VERSION 5.8 ;
BUSBITCHARS "[]" ;
DIVIDERCHAR "/" ;
UNITS
    DATABASE MICRONS 1000 ;
END UNITS

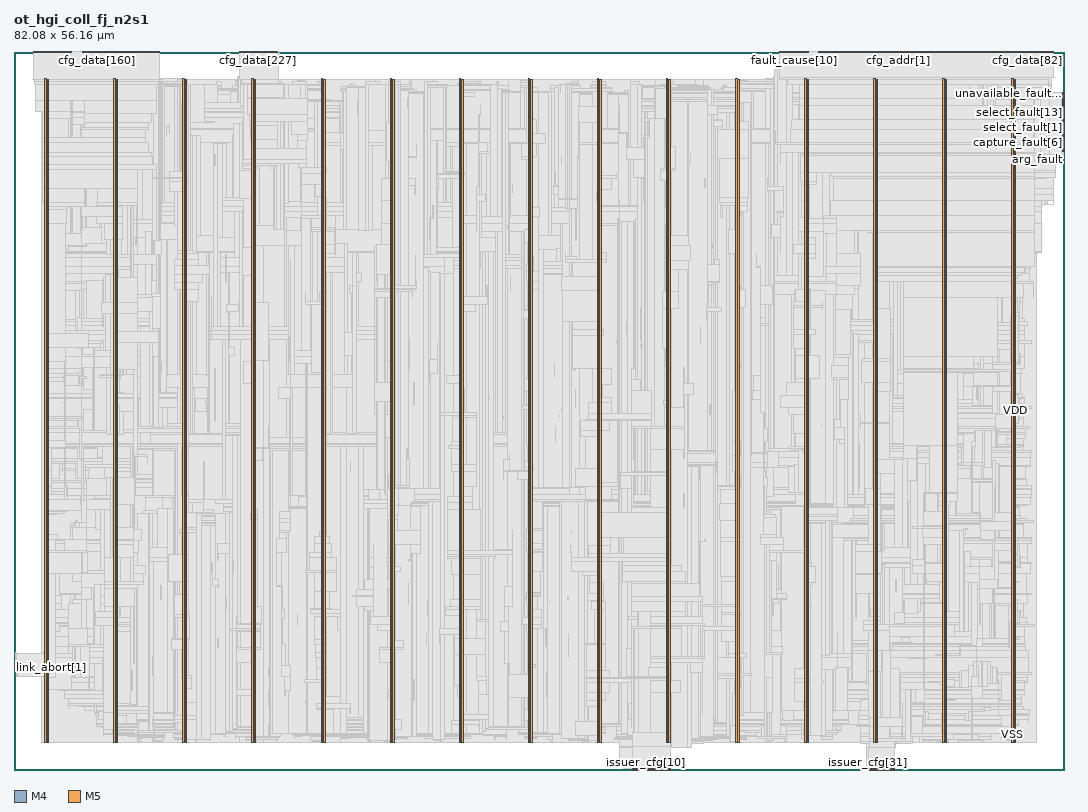
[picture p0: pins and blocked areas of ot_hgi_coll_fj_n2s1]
MACRO ot_hgi_coll_fj_n2s1
  FOREIGN ot_hgi_coll_fj_n2s1 0 0 ;
  CLASS BLOCK ;
  SIZE 82.08 BY 56.16 ;
  PIN arg_fault
    DIRECTION INPUT ;
    USE SIGNAL ;
    PORT
      LAYER M4 ;
        RECT  81.996 48.336 82.08 48.36 ;
    END
  END arg_fault
  PIN capture_fault[0]
    DIRECTION INPUT ;
    USE SIGNAL ;
    PORT
      LAYER M4 ;
        RECT  81.996 48.432 82.08 48.456 ;
    END
  END capture_fault[0]
  PIN capture_fault[1]
    DIRECTION INPUT ;
    USE SIGNAL ;
    PORT
      LAYER M4 ;
        RECT  81.996 48.528 82.08 48.552 ;
    END
  END capture_fault[1]
  PIN capture_fault[2]
    DIRECTION INPUT ;
    USE SIGNAL ;
    PORT
      LAYER M4 ;
        RECT  81.996 48.624 82.08 48.648 ;
    END
  END capture_fault[2]
  PIN capture_fault[3]
    DIRECTION INPUT ;
    USE SIGNAL ;
    PORT
      LAYER M4 ;
        RECT  81.996 48.72 82.08 48.744 ;
    END
  END capture_fault[3]
  PIN capture_fault[4]
    DIRECTION INPUT ;
    USE SIGNAL ;
    PORT
      LAYER M4 ;
        RECT  81.996 48.816 82.08 48.84 ;
    END
  END capture_fault[4]
  PIN capture_fault[5]
    DIRECTION INPUT ;
    USE SIGNAL ;
    PORT
      LAYER M4 ;
        RECT  81.996 48.912 82.08 48.936 ;
    END
  END capture_fault[5]
  PIN capture_fault[6]
    DIRECTION INPUT ;
    USE SIGNAL ;
    PORT
      LAYER M4 ;
        RECT  81.996 49.008 82.08 49.032 ;
    END
  END capture_fault[6]
  PIN capture_fault[7]
    DIRECTION INPUT ;
    USE SIGNAL ;
    PORT
      LAYER M4 ;
        RECT  81.996 49.104 82.08 49.128 ;
    END
  END capture_fault[7]
  PIN capture_fault[8]
    DIRECTION INPUT ;
    USE SIGNAL ;
    PORT
      LAYER M4 ;
        RECT  81.996 49.2 82.08 49.224 ;
    END
  END capture_fault[8]
  PIN capture_fault[9]
    DIRECTION INPUT ;
    USE SIGNAL ;
    PORT
      LAYER M4 ;
        RECT  81.996 49.296 82.08 49.32 ;
    END
  END capture_fault[9]
  PIN cfg_addr[0]
    DIRECTION INPUT ;
    USE SIGNAL ;
    PORT
      LAYER M5 ;
        RECT  69.072 56.076 69.096 56.16 ;
    END
  END cfg_addr[0]
  PIN cfg_addr[10]
    DIRECTION INPUT ;
    USE SIGNAL ;
    PORT
      LAYER M5 ;
        RECT  70.032 56.076 70.056 56.16 ;
    END
  END cfg_addr[10]
  PIN cfg_addr[11]
    DIRECTION INPUT ;
    USE SIGNAL ;
    PORT
      LAYER M5 ;
        RECT  70.128 56.076 70.152 56.16 ;
    END
  END cfg_addr[11]
  PIN cfg_addr[1]
    DIRECTION INPUT ;
    USE SIGNAL ;
    PORT
      LAYER M5 ;
        RECT  69.168 56.076 69.192 56.16 ;
    END
  END cfg_addr[1]
  PIN cfg_addr[2]
    DIRECTION INPUT ;
    USE SIGNAL ;
    PORT
      LAYER M5 ;
        RECT  69.264 56.076 69.288 56.16 ;
    END
  END cfg_addr[2]
  PIN cfg_addr[3]
    DIRECTION INPUT ;
    USE SIGNAL ;
    PORT
      LAYER M5 ;
        RECT  69.36 56.076 69.384 56.16 ;
    END
  END cfg_addr[3]
  PIN cfg_addr[4]
    DIRECTION INPUT ;
    USE SIGNAL ;
    PORT
      LAYER M5 ;
        RECT  69.456 56.076 69.48 56.16 ;
    END
  END cfg_addr[4]
  PIN cfg_addr[5]
    DIRECTION INPUT ;
    USE SIGNAL ;
    PORT
      LAYER M5 ;
        RECT  69.552 56.076 69.576 56.16 ;
    END
  END cfg_addr[5]
  PIN cfg_addr[6]
    DIRECTION INPUT ;
    USE SIGNAL ;
    PORT
      LAYER M5 ;
        RECT  69.648 56.076 69.672 56.16 ;
    END
  END cfg_addr[6]
  PIN cfg_addr[7]
    DIRECTION INPUT ;
    USE SIGNAL ;
    PORT
      LAYER M5 ;
        RECT  69.744 56.076 69.768 56.16 ;
    END
  END cfg_addr[7]
  PIN cfg_addr[8]
    DIRECTION INPUT ;
    USE SIGNAL ;
    PORT
      LAYER M5 ;
        RECT  69.84 56.076 69.864 56.16 ;
    END
  END cfg_addr[8]
  PIN cfg_addr[9]
    DIRECTION INPUT ;
    USE SIGNAL ;
    PORT
      LAYER M5 ;
        RECT  69.936 56.076 69.96 56.16 ;
    END
  END cfg_addr[9]
  PIN cfg_data[0]
    DIRECTION INPUT ;
    USE SIGNAL ;
    PORT
      LAYER M5 ;
        RECT  70.224 56.076 70.248 56.16 ;
    END
  END cfg_data[0]
  PIN cfg_data[100]
    DIRECTION INPUT ;
    USE SIGNAL ;
    PORT
      LAYER M5 ;
        RECT  64.464 56.076 64.488 56.16 ;
    END
  END cfg_data[100]
  PIN cfg_data[101]
    DIRECTION INPUT ;
    USE SIGNAL ;
    PORT
      LAYER M5 ;
        RECT  64.56 56.076 64.584 56.16 ;
    END
  END cfg_data[101]
  PIN cfg_data[102]
    DIRECTION INPUT ;
    USE SIGNAL ;
    PORT
      LAYER M5 ;
        RECT  64.656 56.076 64.68 56.16 ;
    END
  END cfg_data[102]
  PIN cfg_data[103]
    DIRECTION INPUT ;
    USE SIGNAL ;
    PORT
      LAYER M5 ;
        RECT  64.752 56.076 64.776 56.16 ;
    END
  END cfg_data[103]
  PIN cfg_data[104]
    DIRECTION INPUT ;
    USE SIGNAL ;
    PORT
      LAYER M5 ;
        RECT  64.848 56.076 64.872 56.16 ;
    END
  END cfg_data[104]
  PIN cfg_data[105]
    DIRECTION INPUT ;
    USE SIGNAL ;
    PORT
      LAYER M5 ;
        RECT  64.944 56.076 64.968 56.16 ;
    END
  END cfg_data[105]
  PIN cfg_data[106]
    DIRECTION INPUT ;
    USE SIGNAL ;
    PORT
      LAYER M5 ;
        RECT  65.04 56.076 65.064 56.16 ;
    END
  END cfg_data[106]
  PIN cfg_data[107]
    DIRECTION INPUT ;
    USE SIGNAL ;
    PORT
      LAYER M5 ;
        RECT  65.136 56.076 65.16 56.16 ;
    END
  END cfg_data[107]
  PIN cfg_data[108]
    DIRECTION INPUT ;
    USE SIGNAL ;
    PORT
      LAYER M5 ;
        RECT  65.232 56.076 65.256 56.16 ;
    END
  END cfg_data[108]
  PIN cfg_data[109]
    DIRECTION INPUT ;
    USE SIGNAL ;
    PORT
      LAYER M5 ;
        RECT  65.328 56.076 65.352 56.16 ;
    END
  END cfg_data[109]
  PIN cfg_data[10]
    DIRECTION INPUT ;
    USE SIGNAL ;
    PORT
      LAYER M5 ;
        RECT  71.184 56.076 71.208 56.16 ;
    END
  END cfg_data[10]
  PIN cfg_data[110]
    DIRECTION INPUT ;
    USE SIGNAL ;
    PORT
      LAYER M5 ;
        RECT  65.424 56.076 65.448 56.16 ;
    END
  END cfg_data[110]
  PIN cfg_data[111]
    DIRECTION INPUT ;
    USE SIGNAL ;
    PORT
      LAYER M5 ;
        RECT  65.52 56.076 65.544 56.16 ;
    END
  END cfg_data[111]
  PIN cfg_data[112]
    DIRECTION INPUT ;
    USE SIGNAL ;
    PORT
      LAYER M5 ;
        RECT  65.616 56.076 65.64 56.16 ;
    END
  END cfg_data[112]
  PIN cfg_data[113]
    DIRECTION INPUT ;
    USE SIGNAL ;
    PORT
      LAYER M5 ;
        RECT  65.712 56.076 65.736 56.16 ;
    END
  END cfg_data[113]
  PIN cfg_data[114]
    DIRECTION INPUT ;
    USE SIGNAL ;
    PORT
      LAYER M5 ;
        RECT  65.808 56.076 65.832 56.16 ;
    END
  END cfg_data[114]
  PIN cfg_data[115]
    DIRECTION INPUT ;
    USE SIGNAL ;
    PORT
      LAYER M5 ;
        RECT  65.904 56.076 65.928 56.16 ;
    END
  END cfg_data[115]
  PIN cfg_data[116]
    DIRECTION INPUT ;
    USE SIGNAL ;
    PORT
      LAYER M5 ;
        RECT  1.488 56.076 1.512 56.16 ;
    END
  END cfg_data[116]
  PIN cfg_data[117]
    DIRECTION INPUT ;
    USE SIGNAL ;
    PORT
      LAYER M5 ;
        RECT  1.584 56.076 1.608 56.16 ;
    END
  END cfg_data[117]
  PIN cfg_data[118]
    DIRECTION INPUT ;
    USE SIGNAL ;
    PORT
      LAYER M5 ;
        RECT  1.68 56.076 1.704 56.16 ;
    END
  END cfg_data[118]
  PIN cfg_data[119]
    DIRECTION INPUT ;
    USE SIGNAL ;
    PORT
      LAYER M5 ;
        RECT  1.776 56.076 1.8 56.16 ;
    END
  END cfg_data[119]
  PIN cfg_data[11]
    DIRECTION INPUT ;
    USE SIGNAL ;
    PORT
      LAYER M5 ;
        RECT  71.28 56.076 71.304 56.16 ;
    END
  END cfg_data[11]
  PIN cfg_data[120]
    DIRECTION INPUT ;
    USE SIGNAL ;
    PORT
      LAYER M5 ;
        RECT  1.872 56.076 1.896 56.16 ;
    END
  END cfg_data[120]
  PIN cfg_data[121]
    DIRECTION INPUT ;
    USE SIGNAL ;
    PORT
      LAYER M5 ;
        RECT  1.968 56.076 1.992 56.16 ;
    END
  END cfg_data[121]
  PIN cfg_data[122]
    DIRECTION INPUT ;
    USE SIGNAL ;
    PORT
      LAYER M5 ;
        RECT  2.064 56.076 2.088 56.16 ;
    END
  END cfg_data[122]
  PIN cfg_data[123]
    DIRECTION INPUT ;
    USE SIGNAL ;
    PORT
      LAYER M5 ;
        RECT  2.16 56.076 2.184 56.16 ;
    END
  END cfg_data[123]
  PIN cfg_data[124]
    DIRECTION INPUT ;
    USE SIGNAL ;
    PORT
      LAYER M5 ;
        RECT  2.256 56.076 2.28 56.16 ;
    END
  END cfg_data[124]
  PIN cfg_data[125]
    DIRECTION INPUT ;
    USE SIGNAL ;
    PORT
      LAYER M5 ;
        RECT  2.352 56.076 2.376 56.16 ;
    END
  END cfg_data[125]
  PIN cfg_data[126]
    DIRECTION INPUT ;
    USE SIGNAL ;
    PORT
      LAYER M5 ;
        RECT  2.448 56.076 2.472 56.16 ;
    END
  END cfg_data[126]
  PIN cfg_data[127]
    DIRECTION INPUT ;
    USE SIGNAL ;
    PORT
      LAYER M5 ;
        RECT  2.544 56.076 2.568 56.16 ;
    END
  END cfg_data[127]
  PIN cfg_data[128]
    DIRECTION INPUT ;
    USE SIGNAL ;
    PORT
      LAYER M5 ;
        RECT  2.64 56.076 2.664 56.16 ;
    END
  END cfg_data[128]
  PIN cfg_data[129]
    DIRECTION INPUT ;
    USE SIGNAL ;
    PORT
      LAYER M5 ;
        RECT  2.736 56.076 2.76 56.16 ;
    END
  END cfg_data[129]
  PIN cfg_data[12]
    DIRECTION INPUT ;
    USE SIGNAL ;
    PORT
      LAYER M5 ;
        RECT  71.376 56.076 71.4 56.16 ;
    END
  END cfg_data[12]
  PIN cfg_data[130]
    DIRECTION INPUT ;
    USE SIGNAL ;
    PORT
      LAYER M5 ;
        RECT  2.832 56.076 2.856 56.16 ;
    END
  END cfg_data[130]
  PIN cfg_data[131]
    DIRECTION INPUT ;
    USE SIGNAL ;
    PORT
      LAYER M5 ;
        RECT  2.928 56.076 2.952 56.16 ;
    END
  END cfg_data[131]
  PIN cfg_data[132]
    DIRECTION INPUT ;
    USE SIGNAL ;
    PORT
      LAYER M5 ;
        RECT  3.024 56.076 3.048 56.16 ;
    END
  END cfg_data[132]
  PIN cfg_data[133]
    DIRECTION INPUT ;
    USE SIGNAL ;
    PORT
      LAYER M5 ;
        RECT  3.12 56.076 3.144 56.16 ;
    END
  END cfg_data[133]
  PIN cfg_data[134]
    DIRECTION INPUT ;
    USE SIGNAL ;
    PORT
      LAYER M5 ;
        RECT  3.216 56.076 3.24 56.16 ;
    END
  END cfg_data[134]
  PIN cfg_data[135]
    DIRECTION INPUT ;
    USE SIGNAL ;
    PORT
      LAYER M5 ;
        RECT  3.312 56.076 3.336 56.16 ;
    END
  END cfg_data[135]
  PIN cfg_data[136]
    DIRECTION INPUT ;
    USE SIGNAL ;
    PORT
      LAYER M5 ;
        RECT  3.408 56.076 3.432 56.16 ;
    END
  END cfg_data[136]
  PIN cfg_data[137]
    DIRECTION INPUT ;
    USE SIGNAL ;
    PORT
      LAYER M5 ;
        RECT  3.504 56.076 3.528 56.16 ;
    END
  END cfg_data[137]
  PIN cfg_data[138]
    DIRECTION INPUT ;
    USE SIGNAL ;
    PORT
      LAYER M5 ;
        RECT  3.6 56.076 3.624 56.16 ;
    END
  END cfg_data[138]
  PIN cfg_data[139]
    DIRECTION INPUT ;
    USE SIGNAL ;
    PORT
      LAYER M5 ;
        RECT  3.696 56.076 3.72 56.16 ;
    END
  END cfg_data[139]
  PIN cfg_data[13]
    DIRECTION INPUT ;
    USE SIGNAL ;
    PORT
      LAYER M5 ;
        RECT  71.472 56.076 71.496 56.16 ;
    END
  END cfg_data[13]
  PIN cfg_data[140]
    DIRECTION INPUT ;
    USE SIGNAL ;
    PORT
      LAYER M5 ;
        RECT  3.792 56.076 3.816 56.16 ;
    END
  END cfg_data[140]
  PIN cfg_data[141]
    DIRECTION INPUT ;
    USE SIGNAL ;
    PORT
      LAYER M5 ;
        RECT  3.888 56.076 3.912 56.16 ;
    END
  END cfg_data[141]
  PIN cfg_data[142]
    DIRECTION INPUT ;
    USE SIGNAL ;
    PORT
      LAYER M5 ;
        RECT  3.984 56.076 4.008 56.16 ;
    END
  END cfg_data[142]
  PIN cfg_data[143]
    DIRECTION INPUT ;
    USE SIGNAL ;
    PORT
      LAYER M5 ;
        RECT  4.08 56.076 4.104 56.16 ;
    END
  END cfg_data[143]
  PIN cfg_data[144]
    DIRECTION INPUT ;
    USE SIGNAL ;
    PORT
      LAYER M5 ;
        RECT  4.176 56.076 4.2 56.16 ;
    END
  END cfg_data[144]
  PIN cfg_data[145]
    DIRECTION INPUT ;
    USE SIGNAL ;
    PORT
      LAYER M5 ;
        RECT  4.272 56.076 4.296 56.16 ;
    END
  END cfg_data[145]
  PIN cfg_data[146]
    DIRECTION INPUT ;
    USE SIGNAL ;
    PORT
      LAYER M5 ;
        RECT  4.368 56.076 4.392 56.16 ;
    END
  END cfg_data[146]
  PIN cfg_data[147]
    DIRECTION INPUT ;
    USE SIGNAL ;
    PORT
      LAYER M5 ;
        RECT  4.464 56.076 4.488 56.16 ;
    END
  END cfg_data[147]
  PIN cfg_data[148]
    DIRECTION INPUT ;
    USE SIGNAL ;
    PORT
      LAYER M5 ;
        RECT  5.328 56.076 5.352 56.16 ;
    END
  END cfg_data[148]
  PIN cfg_data[149]
    DIRECTION INPUT ;
    USE SIGNAL ;
    PORT
      LAYER M5 ;
        RECT  5.424 56.076 5.448 56.16 ;
    END
  END cfg_data[149]
  PIN cfg_data[14]
    DIRECTION INPUT ;
    USE SIGNAL ;
    PORT
      LAYER M5 ;
        RECT  71.568 56.076 71.592 56.16 ;
    END
  END cfg_data[14]
  PIN cfg_data[150]
    DIRECTION INPUT ;
    USE SIGNAL ;
    PORT
      LAYER M5 ;
        RECT  5.52 56.076 5.544 56.16 ;
    END
  END cfg_data[150]
  PIN cfg_data[151]
    DIRECTION INPUT ;
    USE SIGNAL ;
    PORT
      LAYER M5 ;
        RECT  5.616 56.076 5.64 56.16 ;
    END
  END cfg_data[151]
  PIN cfg_data[152]
    DIRECTION INPUT ;
    USE SIGNAL ;
    PORT
      LAYER M5 ;
        RECT  5.712 56.076 5.736 56.16 ;
    END
  END cfg_data[152]
  PIN cfg_data[153]
    DIRECTION INPUT ;
    USE SIGNAL ;
    PORT
      LAYER M5 ;
        RECT  5.808 56.076 5.832 56.16 ;
    END
  END cfg_data[153]
  PIN cfg_data[154]
    DIRECTION INPUT ;
    USE SIGNAL ;
    PORT
      LAYER M5 ;
        RECT  5.904 56.076 5.928 56.16 ;
    END
  END cfg_data[154]
  PIN cfg_data[155]
    DIRECTION INPUT ;
    USE SIGNAL ;
    PORT
      LAYER M5 ;
        RECT  6 56.076 6.024 56.16 ;
    END
  END cfg_data[155]
  PIN cfg_data[156]
    DIRECTION INPUT ;
    USE SIGNAL ;
    PORT
      LAYER M5 ;
        RECT  6.096 56.076 6.12 56.16 ;
    END
  END cfg_data[156]
  PIN cfg_data[157]
    DIRECTION INPUT ;
    USE SIGNAL ;
    PORT
      LAYER M5 ;
        RECT  6.192 56.076 6.216 56.16 ;
    END
  END cfg_data[157]
  PIN cfg_data[158]
    DIRECTION INPUT ;
    USE SIGNAL ;
    PORT
      LAYER M5 ;
        RECT  6.288 56.076 6.312 56.16 ;
    END
  END cfg_data[158]
  PIN cfg_data[159]
    DIRECTION INPUT ;
    USE SIGNAL ;
    PORT
      LAYER M5 ;
        RECT  6.384 56.076 6.408 56.16 ;
    END
  END cfg_data[159]
  PIN cfg_data[15]
    DIRECTION INPUT ;
    USE SIGNAL ;
    PORT
      LAYER M5 ;
        RECT  71.664 56.076 71.688 56.16 ;
    END
  END cfg_data[15]
  PIN cfg_data[160]
    DIRECTION INPUT ;
    USE SIGNAL ;
    PORT
      LAYER M5 ;
        RECT  6.48 56.076 6.504 56.16 ;
    END
  END cfg_data[160]
  PIN cfg_data[161]
    DIRECTION INPUT ;
    USE SIGNAL ;
    PORT
      LAYER M5 ;
        RECT  6.576 56.076 6.6 56.16 ;
    END
  END cfg_data[161]
  PIN cfg_data[162]
    DIRECTION INPUT ;
    USE SIGNAL ;
    PORT
      LAYER M5 ;
        RECT  6.672 56.076 6.696 56.16 ;
    END
  END cfg_data[162]
  PIN cfg_data[163]
    DIRECTION INPUT ;
    USE SIGNAL ;
    PORT
      LAYER M5 ;
        RECT  6.768 56.076 6.792 56.16 ;
    END
  END cfg_data[163]
  PIN cfg_data[164]
    DIRECTION INPUT ;
    USE SIGNAL ;
    PORT
      LAYER M5 ;
        RECT  6.864 56.076 6.888 56.16 ;
    END
  END cfg_data[164]
  PIN cfg_data[165]
    DIRECTION INPUT ;
    USE SIGNAL ;
    PORT
      LAYER M5 ;
        RECT  6.96 56.076 6.984 56.16 ;
    END
  END cfg_data[165]
  PIN cfg_data[166]
    DIRECTION INPUT ;
    USE SIGNAL ;
    PORT
      LAYER M5 ;
        RECT  7.056 56.076 7.08 56.16 ;
    END
  END cfg_data[166]
  PIN cfg_data[167]
    DIRECTION INPUT ;
    USE SIGNAL ;
    PORT
      LAYER M5 ;
        RECT  7.152 56.076 7.176 56.16 ;
    END
  END cfg_data[167]
  PIN cfg_data[168]
    DIRECTION INPUT ;
    USE SIGNAL ;
    PORT
      LAYER M5 ;
        RECT  7.248 56.076 7.272 56.16 ;
    END
  END cfg_data[168]
  PIN cfg_data[169]
    DIRECTION INPUT ;
    USE SIGNAL ;
    PORT
      LAYER M5 ;
        RECT  7.344 56.076 7.368 56.16 ;
    END
  END cfg_data[169]
  PIN cfg_data[16]
    DIRECTION INPUT ;
    USE SIGNAL ;
    PORT
      LAYER M5 ;
        RECT  71.76 56.076 71.784 56.16 ;
    END
  END cfg_data[16]
  PIN cfg_data[170]
    DIRECTION INPUT ;
    USE SIGNAL ;
    PORT
      LAYER M5 ;
        RECT  7.44 56.076 7.464 56.16 ;
    END
  END cfg_data[170]
  PIN cfg_data[171]
    DIRECTION INPUT ;
    USE SIGNAL ;
    PORT
      LAYER M5 ;
        RECT  7.536 56.076 7.56 56.16 ;
    END
  END cfg_data[171]
  PIN cfg_data[172]
    DIRECTION INPUT ;
    USE SIGNAL ;
    PORT
      LAYER M5 ;
        RECT  7.632 56.076 7.656 56.16 ;
    END
  END cfg_data[172]
  PIN cfg_data[173]
    DIRECTION INPUT ;
    USE SIGNAL ;
    PORT
      LAYER M5 ;
        RECT  7.728 56.076 7.752 56.16 ;
    END
  END cfg_data[173]
  PIN cfg_data[174]
    DIRECTION INPUT ;
    USE SIGNAL ;
    PORT
      LAYER M5 ;
        RECT  7.824 56.076 7.848 56.16 ;
    END
  END cfg_data[174]
  PIN cfg_data[175]
    DIRECTION INPUT ;
    USE SIGNAL ;
    PORT
      LAYER M5 ;
        RECT  7.92 56.076 7.944 56.16 ;
    END
  END cfg_data[175]
  PIN cfg_data[176]
    DIRECTION INPUT ;
    USE SIGNAL ;
    PORT
      LAYER M5 ;
        RECT  8.016 56.076 8.04 56.16 ;
    END
  END cfg_data[176]
  PIN cfg_data[177]
    DIRECTION INPUT ;
    USE SIGNAL ;
    PORT
      LAYER M5 ;
        RECT  8.112 56.076 8.136 56.16 ;
    END
  END cfg_data[177]
  PIN cfg_data[178]
    DIRECTION INPUT ;
    USE SIGNAL ;
    PORT
      LAYER M5 ;
        RECT  8.208 56.076 8.232 56.16 ;
    END
  END cfg_data[178]
  PIN cfg_data[179]
    DIRECTION INPUT ;
    USE SIGNAL ;
    PORT
      LAYER M5 ;
        RECT  8.304 56.076 8.328 56.16 ;
    END
  END cfg_data[179]
  PIN cfg_data[17]
    DIRECTION INPUT ;
    USE SIGNAL ;
    PORT
      LAYER M5 ;
        RECT  71.856 56.076 71.88 56.16 ;
    END
  END cfg_data[17]
  PIN cfg_data[180]
    DIRECTION INPUT ;
    USE SIGNAL ;
    PORT
      LAYER M5 ;
        RECT  8.4 56.076 8.424 56.16 ;
    END
  END cfg_data[180]
  PIN cfg_data[181]
    DIRECTION INPUT ;
    USE SIGNAL ;
    PORT
      LAYER M5 ;
        RECT  8.496 56.076 8.52 56.16 ;
    END
  END cfg_data[181]
  PIN cfg_data[182]
    DIRECTION INPUT ;
    USE SIGNAL ;
    PORT
      LAYER M5 ;
        RECT  8.592 56.076 8.616 56.16 ;
    END
  END cfg_data[182]
  PIN cfg_data[183]
    DIRECTION INPUT ;
    USE SIGNAL ;
    PORT
      LAYER M5 ;
        RECT  8.688 56.076 8.712 56.16 ;
    END
  END cfg_data[183]
  PIN cfg_data[184]
    DIRECTION INPUT ;
    USE SIGNAL ;
    PORT
      LAYER M5 ;
        RECT  8.784 56.076 8.808 56.16 ;
    END
  END cfg_data[184]
  PIN cfg_data[185]
    DIRECTION INPUT ;
    USE SIGNAL ;
    PORT
      LAYER M5 ;
        RECT  8.88 56.076 8.904 56.16 ;
    END
  END cfg_data[185]
  PIN cfg_data[186]
    DIRECTION INPUT ;
    USE SIGNAL ;
    PORT
      LAYER M5 ;
        RECT  8.976 56.076 9 56.16 ;
    END
  END cfg_data[186]
  PIN cfg_data[187]
    DIRECTION INPUT ;
    USE SIGNAL ;
    PORT
      LAYER M5 ;
        RECT  9.072 56.076 9.096 56.16 ;
    END
  END cfg_data[187]
  PIN cfg_data[188]
    DIRECTION INPUT ;
    USE SIGNAL ;
    PORT
      LAYER M5 ;
        RECT  9.168 56.076 9.192 56.16 ;
    END
  END cfg_data[188]
  PIN cfg_data[189]
    DIRECTION INPUT ;
    USE SIGNAL ;
    PORT
      LAYER M5 ;
        RECT  9.264 56.076 9.288 56.16 ;
    END
  END cfg_data[189]
  PIN cfg_data[18]
    DIRECTION INPUT ;
    USE SIGNAL ;
    PORT
      LAYER M5 ;
        RECT  71.952 56.076 71.976 56.16 ;
    END
  END cfg_data[18]
  PIN cfg_data[190]
    DIRECTION INPUT ;
    USE SIGNAL ;
    PORT
      LAYER M5 ;
        RECT  9.36 56.076 9.384 56.16 ;
    END
  END cfg_data[190]
  PIN cfg_data[191]
    DIRECTION INPUT ;
    USE SIGNAL ;
    PORT
      LAYER M5 ;
        RECT  9.456 56.076 9.48 56.16 ;
    END
  END cfg_data[191]
  PIN cfg_data[192]
    DIRECTION INPUT ;
    USE SIGNAL ;
    PORT
      LAYER M5 ;
        RECT  9.552 56.076 9.576 56.16 ;
    END
  END cfg_data[192]
  PIN cfg_data[193]
    DIRECTION INPUT ;
    USE SIGNAL ;
    PORT
      LAYER M5 ;
        RECT  9.648 56.076 9.672 56.16 ;
    END
  END cfg_data[193]
  PIN cfg_data[194]
    DIRECTION INPUT ;
    USE SIGNAL ;
    PORT
      LAYER M5 ;
        RECT  9.744 56.076 9.768 56.16 ;
    END
  END cfg_data[194]
  PIN cfg_data[195]
    DIRECTION INPUT ;
    USE SIGNAL ;
    PORT
      LAYER M5 ;
        RECT  9.84 56.076 9.864 56.16 ;
    END
  END cfg_data[195]
  PIN cfg_data[196]
    DIRECTION INPUT ;
    USE SIGNAL ;
    PORT
      LAYER M5 ;
        RECT  9.936 56.076 9.96 56.16 ;
    END
  END cfg_data[196]
  PIN cfg_data[197]
    DIRECTION INPUT ;
    USE SIGNAL ;
    PORT
      LAYER M5 ;
        RECT  10.032 56.076 10.056 56.16 ;
    END
  END cfg_data[197]
  PIN cfg_data[198]
    DIRECTION INPUT ;
    USE SIGNAL ;
    PORT
      LAYER M5 ;
        RECT  10.128 56.076 10.152 56.16 ;
    END
  END cfg_data[198]
  PIN cfg_data[199]
    DIRECTION INPUT ;
    USE SIGNAL ;
    PORT
      LAYER M5 ;
        RECT  10.224 56.076 10.248 56.16 ;
    END
  END cfg_data[199]
  PIN cfg_data[19]
    DIRECTION INPUT ;
    USE SIGNAL ;
    PORT
      LAYER M5 ;
        RECT  72.048 56.076 72.072 56.16 ;
    END
  END cfg_data[19]
  PIN cfg_data[1]
    DIRECTION INPUT ;
    USE SIGNAL ;
    PORT
      LAYER M5 ;
        RECT  70.32 56.076 70.344 56.16 ;
    END
  END cfg_data[1]
  PIN cfg_data[200]
    DIRECTION INPUT ;
    USE SIGNAL ;
    PORT
      LAYER M5 ;
        RECT  10.32 56.076 10.344 56.16 ;
    END
  END cfg_data[200]
  PIN cfg_data[201]
    DIRECTION INPUT ;
    USE SIGNAL ;
    PORT
      LAYER M5 ;
        RECT  10.416 56.076 10.44 56.16 ;
    END
  END cfg_data[201]
  PIN cfg_data[202]
    DIRECTION INPUT ;
    USE SIGNAL ;
    PORT
      LAYER M5 ;
        RECT  10.512 56.076 10.536 56.16 ;
    END
  END cfg_data[202]
  PIN cfg_data[203]
    DIRECTION INPUT ;
    USE SIGNAL ;
    PORT
      LAYER M5 ;
        RECT  10.608 56.076 10.632 56.16 ;
    END
  END cfg_data[203]
  PIN cfg_data[204]
    DIRECTION INPUT ;
    USE SIGNAL ;
    PORT
      LAYER M5 ;
        RECT  10.704 56.076 10.728 56.16 ;
    END
  END cfg_data[204]
  PIN cfg_data[205]
    DIRECTION INPUT ;
    USE SIGNAL ;
    PORT
      LAYER M5 ;
        RECT  10.8 56.076 10.824 56.16 ;
    END
  END cfg_data[205]
  PIN cfg_data[206]
    DIRECTION INPUT ;
    USE SIGNAL ;
    PORT
      LAYER M5 ;
        RECT  10.896 56.076 10.92 56.16 ;
    END
  END cfg_data[206]
  PIN cfg_data[207]
    DIRECTION INPUT ;
    USE SIGNAL ;
    PORT
      LAYER M5 ;
        RECT  10.992 56.076 11.016 56.16 ;
    END
  END cfg_data[207]
  PIN cfg_data[208]
    DIRECTION INPUT ;
    USE SIGNAL ;
    PORT
      LAYER M5 ;
        RECT  11.088 56.076 11.112 56.16 ;
    END
  END cfg_data[208]
  PIN cfg_data[209]
    DIRECTION INPUT ;
    USE SIGNAL ;
    PORT
      LAYER M5 ;
        RECT  11.184 56.076 11.208 56.16 ;
    END
  END cfg_data[209]
  PIN cfg_data[20]
    DIRECTION INPUT ;
    USE SIGNAL ;
    PORT
      LAYER M5 ;
        RECT  72.144 56.076 72.168 56.16 ;
    END
  END cfg_data[20]
  PIN cfg_data[210]
    DIRECTION INPUT ;
    USE SIGNAL ;
    PORT
      LAYER M5 ;
        RECT  11.28 56.076 11.304 56.16 ;
    END
  END cfg_data[210]
  PIN cfg_data[211]
    DIRECTION INPUT ;
    USE SIGNAL ;
    PORT
      LAYER M5 ;
        RECT  11.376 56.076 11.4 56.16 ;
    END
  END cfg_data[211]
  PIN cfg_data[212]
    DIRECTION INPUT ;
    USE SIGNAL ;
    PORT
      LAYER M5 ;
        RECT  17.616 56.076 17.64 56.16 ;
    END
  END cfg_data[212]
  PIN cfg_data[213]
    DIRECTION INPUT ;
    USE SIGNAL ;
    PORT
      LAYER M5 ;
        RECT  17.712 56.076 17.736 56.16 ;
    END
  END cfg_data[213]
  PIN cfg_data[214]
    DIRECTION INPUT ;
    USE SIGNAL ;
    PORT
      LAYER M5 ;
        RECT  17.808 56.076 17.832 56.16 ;
    END
  END cfg_data[214]
  PIN cfg_data[215]
    DIRECTION INPUT ;
    USE SIGNAL ;
    PORT
      LAYER M5 ;
        RECT  17.904 56.076 17.928 56.16 ;
    END
  END cfg_data[215]
  PIN cfg_data[216]
    DIRECTION INPUT ;
    USE SIGNAL ;
    PORT
      LAYER M5 ;
        RECT  18 56.076 18.024 56.16 ;
    END
  END cfg_data[216]
  PIN cfg_data[217]
    DIRECTION INPUT ;
    USE SIGNAL ;
    PORT
      LAYER M5 ;
        RECT  18.096 56.076 18.12 56.16 ;
    END
  END cfg_data[217]
  PIN cfg_data[218]
    DIRECTION INPUT ;
    USE SIGNAL ;
    PORT
      LAYER M5 ;
        RECT  18.192 56.076 18.216 56.16 ;
    END
  END cfg_data[218]
  PIN cfg_data[219]
    DIRECTION INPUT ;
    USE SIGNAL ;
    PORT
      LAYER M5 ;
        RECT  18.288 56.076 18.312 56.16 ;
    END
  END cfg_data[219]
  PIN cfg_data[21]
    DIRECTION INPUT ;
    USE SIGNAL ;
    PORT
      LAYER M5 ;
        RECT  72.24 56.076 72.264 56.16 ;
    END
  END cfg_data[21]
  PIN cfg_data[220]
    DIRECTION INPUT ;
    USE SIGNAL ;
    PORT
      LAYER M5 ;
        RECT  18.384 56.076 18.408 56.16 ;
    END
  END cfg_data[220]
  PIN cfg_data[221]
    DIRECTION INPUT ;
    USE SIGNAL ;
    PORT
      LAYER M5 ;
        RECT  18.48 56.076 18.504 56.16 ;
    END
  END cfg_data[221]
  PIN cfg_data[222]
    DIRECTION INPUT ;
    USE SIGNAL ;
    PORT
      LAYER M5 ;
        RECT  18.576 56.076 18.6 56.16 ;
    END
  END cfg_data[222]
  PIN cfg_data[223]
    DIRECTION INPUT ;
    USE SIGNAL ;
    PORT
      LAYER M5 ;
        RECT  18.672 56.076 18.696 56.16 ;
    END
  END cfg_data[223]
  PIN cfg_data[224]
    DIRECTION INPUT ;
    USE SIGNAL ;
    PORT
      LAYER M5 ;
        RECT  18.768 56.076 18.792 56.16 ;
    END
  END cfg_data[224]
  PIN cfg_data[225]
    DIRECTION INPUT ;
    USE SIGNAL ;
    PORT
      LAYER M5 ;
        RECT  18.864 56.076 18.888 56.16 ;
    END
  END cfg_data[225]
  PIN cfg_data[226]
    DIRECTION INPUT ;
    USE SIGNAL ;
    PORT
      LAYER M5 ;
        RECT  18.96 56.076 18.984 56.16 ;
    END
  END cfg_data[226]
  PIN cfg_data[227]
    DIRECTION INPUT ;
    USE SIGNAL ;
    PORT
      LAYER M5 ;
        RECT  19.056 56.076 19.08 56.16 ;
    END
  END cfg_data[227]
  PIN cfg_data[228]
    DIRECTION INPUT ;
    USE SIGNAL ;
    PORT
      LAYER M5 ;
        RECT  19.152 56.076 19.176 56.16 ;
    END
  END cfg_data[228]
  PIN cfg_data[229]
    DIRECTION INPUT ;
    USE SIGNAL ;
    PORT
      LAYER M5 ;
        RECT  19.248 56.076 19.272 56.16 ;
    END
  END cfg_data[229]
  PIN cfg_data[22]
    DIRECTION INPUT ;
    USE SIGNAL ;
    PORT
      LAYER M5 ;
        RECT  72.336 56.076 72.36 56.16 ;
    END
  END cfg_data[22]
  PIN cfg_data[230]
    DIRECTION INPUT ;
    USE SIGNAL ;
    PORT
      LAYER M5 ;
        RECT  19.344 56.076 19.368 56.16 ;
    END
  END cfg_data[230]
  PIN cfg_data[231]
    DIRECTION INPUT ;
    USE SIGNAL ;
    PORT
      LAYER M5 ;
        RECT  19.44 56.076 19.464 56.16 ;
    END
  END cfg_data[231]
  PIN cfg_data[232]
    DIRECTION INPUT ;
    USE SIGNAL ;
    PORT
      LAYER M5 ;
        RECT  19.536 56.076 19.56 56.16 ;
    END
  END cfg_data[232]
  PIN cfg_data[233]
    DIRECTION INPUT ;
    USE SIGNAL ;
    PORT
      LAYER M5 ;
        RECT  19.632 56.076 19.656 56.16 ;
    END
  END cfg_data[233]
  PIN cfg_data[234]
    DIRECTION INPUT ;
    USE SIGNAL ;
    PORT
      LAYER M5 ;
        RECT  19.728 56.076 19.752 56.16 ;
    END
  END cfg_data[234]
  PIN cfg_data[235]
    DIRECTION INPUT ;
    USE SIGNAL ;
    PORT
      LAYER M5 ;
        RECT  19.824 56.076 19.848 56.16 ;
    END
  END cfg_data[235]
  PIN cfg_data[236]
    DIRECTION INPUT ;
    USE SIGNAL ;
    PORT
      LAYER M5 ;
        RECT  19.92 56.076 19.944 56.16 ;
    END
  END cfg_data[236]
  PIN cfg_data[237]
    DIRECTION INPUT ;
    USE SIGNAL ;
    PORT
      LAYER M5 ;
        RECT  20.016 56.076 20.04 56.16 ;
    END
  END cfg_data[237]
  PIN cfg_data[238]
    DIRECTION INPUT ;
    USE SIGNAL ;
    PORT
      LAYER M5 ;
        RECT  20.112 56.076 20.136 56.16 ;
    END
  END cfg_data[238]
  PIN cfg_data[239]
    DIRECTION INPUT ;
    USE SIGNAL ;
    PORT
      LAYER M5 ;
        RECT  20.208 56.076 20.232 56.16 ;
    END
  END cfg_data[239]
  PIN cfg_data[23]
    DIRECTION INPUT ;
    USE SIGNAL ;
    PORT
      LAYER M5 ;
        RECT  72.432 56.076 72.456 56.16 ;
    END
  END cfg_data[23]
  PIN cfg_data[240]
    DIRECTION INPUT ;
    USE SIGNAL ;
    PORT
      LAYER M5 ;
        RECT  20.304 56.076 20.328 56.16 ;
    END
  END cfg_data[240]
  PIN cfg_data[241]
    DIRECTION INPUT ;
    USE SIGNAL ;
    PORT
      LAYER M5 ;
        RECT  20.4 56.076 20.424 56.16 ;
    END
  END cfg_data[241]
  PIN cfg_data[242]
    DIRECTION INPUT ;
    USE SIGNAL ;
    PORT
      LAYER M5 ;
        RECT  20.496 56.076 20.52 56.16 ;
    END
  END cfg_data[242]
  PIN cfg_data[243]
    DIRECTION INPUT ;
    USE SIGNAL ;
    PORT
      LAYER M5 ;
        RECT  20.592 56.076 20.616 56.16 ;
    END
  END cfg_data[243]
  PIN cfg_data[244]
    DIRECTION INPUT ;
    USE SIGNAL ;
    PORT
      LAYER M5 ;
        RECT  66 56.076 66.024 56.16 ;
    END
  END cfg_data[244]
  PIN cfg_data[245]
    DIRECTION INPUT ;
    USE SIGNAL ;
    PORT
      LAYER M5 ;
        RECT  66.096 56.076 66.12 56.16 ;
    END
  END cfg_data[245]
  PIN cfg_data[246]
    DIRECTION INPUT ;
    USE SIGNAL ;
    PORT
      LAYER M5 ;
        RECT  66.192 56.076 66.216 56.16 ;
    END
  END cfg_data[246]
  PIN cfg_data[247]
    DIRECTION INPUT ;
    USE SIGNAL ;
    PORT
      LAYER M5 ;
        RECT  66.288 56.076 66.312 56.16 ;
    END
  END cfg_data[247]
  PIN cfg_data[248]
    DIRECTION INPUT ;
    USE SIGNAL ;
    PORT
      LAYER M5 ;
        RECT  66.384 56.076 66.408 56.16 ;
    END
  END cfg_data[248]
  PIN cfg_data[249]
    DIRECTION INPUT ;
    USE SIGNAL ;
    PORT
      LAYER M5 ;
        RECT  66.48 56.076 66.504 56.16 ;
    END
  END cfg_data[249]
  PIN cfg_data[24]
    DIRECTION INPUT ;
    USE SIGNAL ;
    PORT
      LAYER M5 ;
        RECT  72.528 56.076 72.552 56.16 ;
    END
  END cfg_data[24]
  PIN cfg_data[250]
    DIRECTION INPUT ;
    USE SIGNAL ;
    PORT
      LAYER M5 ;
        RECT  66.576 56.076 66.6 56.16 ;
    END
  END cfg_data[250]
  PIN cfg_data[251]
    DIRECTION INPUT ;
    USE SIGNAL ;
    PORT
      LAYER M5 ;
        RECT  66.672 56.076 66.696 56.16 ;
    END
  END cfg_data[251]
  PIN cfg_data[252]
    DIRECTION INPUT ;
    USE SIGNAL ;
    PORT
      LAYER M5 ;
        RECT  66.768 56.076 66.792 56.16 ;
    END
  END cfg_data[252]
  PIN cfg_data[253]
    DIRECTION INPUT ;
    USE SIGNAL ;
    PORT
      LAYER M5 ;
        RECT  66.864 56.076 66.888 56.16 ;
    END
  END cfg_data[253]
  PIN cfg_data[254]
    DIRECTION INPUT ;
    USE SIGNAL ;
    PORT
      LAYER M5 ;
        RECT  66.96 56.076 66.984 56.16 ;
    END
  END cfg_data[254]
  PIN cfg_data[255]
    DIRECTION INPUT ;
    USE SIGNAL ;
    PORT
      LAYER M5 ;
        RECT  67.056 56.076 67.08 56.16 ;
    END
  END cfg_data[255]
  PIN cfg_data[25]
    DIRECTION INPUT ;
    USE SIGNAL ;
    PORT
      LAYER M5 ;
        RECT  72.624 56.076 72.648 56.16 ;
    END
  END cfg_data[25]
  PIN cfg_data[26]
    DIRECTION INPUT ;
    USE SIGNAL ;
    PORT
      LAYER M5 ;
        RECT  72.72 56.076 72.744 56.16 ;
    END
  END cfg_data[26]
  PIN cfg_data[27]
    DIRECTION INPUT ;
    USE SIGNAL ;
    PORT
      LAYER M5 ;
        RECT  72.816 56.076 72.84 56.16 ;
    END
  END cfg_data[27]
  PIN cfg_data[28]
    DIRECTION INPUT ;
    USE SIGNAL ;
    PORT
      LAYER M5 ;
        RECT  72.912 56.076 72.936 56.16 ;
    END
  END cfg_data[28]
  PIN cfg_data[29]
    DIRECTION INPUT ;
    USE SIGNAL ;
    PORT
      LAYER M5 ;
        RECT  73.008 56.076 73.032 56.16 ;
    END
  END cfg_data[29]
  PIN cfg_data[2]
    DIRECTION INPUT ;
    USE SIGNAL ;
    PORT
      LAYER M5 ;
        RECT  70.416 56.076 70.44 56.16 ;
    END
  END cfg_data[2]
  PIN cfg_data[30]
    DIRECTION INPUT ;
    USE SIGNAL ;
    PORT
      LAYER M5 ;
        RECT  73.104 56.076 73.128 56.16 ;
    END
  END cfg_data[30]
  PIN cfg_data[31]
    DIRECTION INPUT ;
    USE SIGNAL ;
    PORT
      LAYER M5 ;
        RECT  73.2 56.076 73.224 56.16 ;
    END
  END cfg_data[31]
  PIN cfg_data[32]
    DIRECTION INPUT ;
    USE SIGNAL ;
    PORT
      LAYER M5 ;
        RECT  73.296 56.076 73.32 56.16 ;
    END
  END cfg_data[32]
  PIN cfg_data[33]
    DIRECTION INPUT ;
    USE SIGNAL ;
    PORT
      LAYER M5 ;
        RECT  73.392 56.076 73.416 56.16 ;
    END
  END cfg_data[33]
  PIN cfg_data[34]
    DIRECTION INPUT ;
    USE SIGNAL ;
    PORT
      LAYER M5 ;
        RECT  73.488 56.076 73.512 56.16 ;
    END
  END cfg_data[34]
  PIN cfg_data[35]
    DIRECTION INPUT ;
    USE SIGNAL ;
    PORT
      LAYER M5 ;
        RECT  73.584 56.076 73.608 56.16 ;
    END
  END cfg_data[35]
  PIN cfg_data[36]
    DIRECTION INPUT ;
    USE SIGNAL ;
    PORT
      LAYER M5 ;
        RECT  73.68 56.076 73.704 56.16 ;
    END
  END cfg_data[36]
  PIN cfg_data[37]
    DIRECTION INPUT ;
    USE SIGNAL ;
    PORT
      LAYER M5 ;
        RECT  73.776 56.076 73.8 56.16 ;
    END
  END cfg_data[37]
  PIN cfg_data[38]
    DIRECTION INPUT ;
    USE SIGNAL ;
    PORT
      LAYER M5 ;
        RECT  73.872 56.076 73.896 56.16 ;
    END
  END cfg_data[38]
  PIN cfg_data[39]
    DIRECTION INPUT ;
    USE SIGNAL ;
    PORT
      LAYER M5 ;
        RECT  73.968 56.076 73.992 56.16 ;
    END
  END cfg_data[39]
  PIN cfg_data[3]
    DIRECTION INPUT ;
    USE SIGNAL ;
    PORT
      LAYER M5 ;
        RECT  70.512 56.076 70.536 56.16 ;
    END
  END cfg_data[3]
  PIN cfg_data[40]
    DIRECTION INPUT ;
    USE SIGNAL ;
    PORT
      LAYER M5 ;
        RECT  74.064 56.076 74.088 56.16 ;
    END
  END cfg_data[40]
  PIN cfg_data[41]
    DIRECTION INPUT ;
    USE SIGNAL ;
    PORT
      LAYER M5 ;
        RECT  74.16 56.076 74.184 56.16 ;
    END
  END cfg_data[41]
  PIN cfg_data[42]
    DIRECTION INPUT ;
    USE SIGNAL ;
    PORT
      LAYER M5 ;
        RECT  74.256 56.076 74.28 56.16 ;
    END
  END cfg_data[42]
  PIN cfg_data[43]
    DIRECTION INPUT ;
    USE SIGNAL ;
    PORT
      LAYER M5 ;
        RECT  74.352 56.076 74.376 56.16 ;
    END
  END cfg_data[43]
  PIN cfg_data[44]
    DIRECTION INPUT ;
    USE SIGNAL ;
    PORT
      LAYER M5 ;
        RECT  74.448 56.076 74.472 56.16 ;
    END
  END cfg_data[44]
  PIN cfg_data[45]
    DIRECTION INPUT ;
    USE SIGNAL ;
    PORT
      LAYER M5 ;
        RECT  74.544 56.076 74.568 56.16 ;
    END
  END cfg_data[45]
  PIN cfg_data[46]
    DIRECTION INPUT ;
    USE SIGNAL ;
    PORT
      LAYER M5 ;
        RECT  74.64 56.076 74.664 56.16 ;
    END
  END cfg_data[46]
  PIN cfg_data[47]
    DIRECTION INPUT ;
    USE SIGNAL ;
    PORT
      LAYER M5 ;
        RECT  74.736 56.076 74.76 56.16 ;
    END
  END cfg_data[47]
  PIN cfg_data[48]
    DIRECTION INPUT ;
    USE SIGNAL ;
    PORT
      LAYER M5 ;
        RECT  74.832 56.076 74.856 56.16 ;
    END
  END cfg_data[48]
  PIN cfg_data[49]
    DIRECTION INPUT ;
    USE SIGNAL ;
    PORT
      LAYER M5 ;
        RECT  74.928 56.076 74.952 56.16 ;
    END
  END cfg_data[49]
  PIN cfg_data[4]
    DIRECTION INPUT ;
    USE SIGNAL ;
    PORT
      LAYER M5 ;
        RECT  70.608 56.076 70.632 56.16 ;
    END
  END cfg_data[4]
  PIN cfg_data[50]
    DIRECTION INPUT ;
    USE SIGNAL ;
    PORT
      LAYER M5 ;
        RECT  75.024 56.076 75.048 56.16 ;
    END
  END cfg_data[50]
  PIN cfg_data[51]
    DIRECTION INPUT ;
    USE SIGNAL ;
    PORT
      LAYER M5 ;
        RECT  75.12 56.076 75.144 56.16 ;
    END
  END cfg_data[51]
  PIN cfg_data[52]
    DIRECTION INPUT ;
    USE SIGNAL ;
    PORT
      LAYER M5 ;
        RECT  78.288 56.076 78.312 56.16 ;
    END
  END cfg_data[52]
  PIN cfg_data[53]
    DIRECTION INPUT ;
    USE SIGNAL ;
    PORT
      LAYER M5 ;
        RECT  78.384 56.076 78.408 56.16 ;
    END
  END cfg_data[53]
  PIN cfg_data[54]
    DIRECTION INPUT ;
    USE SIGNAL ;
    PORT
      LAYER M5 ;
        RECT  78.48 56.076 78.504 56.16 ;
    END
  END cfg_data[54]
  PIN cfg_data[55]
    DIRECTION INPUT ;
    USE SIGNAL ;
    PORT
      LAYER M5 ;
        RECT  78.576 56.076 78.6 56.16 ;
    END
  END cfg_data[55]
  PIN cfg_data[56]
    DIRECTION INPUT ;
    USE SIGNAL ;
    PORT
      LAYER M5 ;
        RECT  78.672 56.076 78.696 56.16 ;
    END
  END cfg_data[56]
  PIN cfg_data[57]
    DIRECTION INPUT ;
    USE SIGNAL ;
    PORT
      LAYER M5 ;
        RECT  78.768 56.076 78.792 56.16 ;
    END
  END cfg_data[57]
  PIN cfg_data[58]
    DIRECTION INPUT ;
    USE SIGNAL ;
    PORT
      LAYER M5 ;
        RECT  78.864 56.076 78.888 56.16 ;
    END
  END cfg_data[58]
  PIN cfg_data[59]
    DIRECTION INPUT ;
    USE SIGNAL ;
    PORT
      LAYER M5 ;
        RECT  78.96 56.076 78.984 56.16 ;
    END
  END cfg_data[59]
  PIN cfg_data[5]
    DIRECTION INPUT ;
    USE SIGNAL ;
    PORT
      LAYER M5 ;
        RECT  70.704 56.076 70.728 56.16 ;
    END
  END cfg_data[5]
  PIN cfg_data[60]
    DIRECTION INPUT ;
    USE SIGNAL ;
    PORT
      LAYER M5 ;
        RECT  79.056 56.076 79.08 56.16 ;
    END
  END cfg_data[60]
  PIN cfg_data[61]
    DIRECTION INPUT ;
    USE SIGNAL ;
    PORT
      LAYER M5 ;
        RECT  79.152 56.076 79.176 56.16 ;
    END
  END cfg_data[61]
  PIN cfg_data[62]
    DIRECTION INPUT ;
    USE SIGNAL ;
    PORT
      LAYER M5 ;
        RECT  79.248 56.076 79.272 56.16 ;
    END
  END cfg_data[62]
  PIN cfg_data[63]
    DIRECTION INPUT ;
    USE SIGNAL ;
    PORT
      LAYER M5 ;
        RECT  79.344 56.076 79.368 56.16 ;
    END
  END cfg_data[63]
  PIN cfg_data[64]
    DIRECTION INPUT ;
    USE SIGNAL ;
    PORT
      LAYER M5 ;
        RECT  79.44 56.076 79.464 56.16 ;
    END
  END cfg_data[64]
  PIN cfg_data[65]
    DIRECTION INPUT ;
    USE SIGNAL ;
    PORT
      LAYER M5 ;
        RECT  79.536 56.076 79.56 56.16 ;
    END
  END cfg_data[65]
  PIN cfg_data[66]
    DIRECTION INPUT ;
    USE SIGNAL ;
    PORT
      LAYER M5 ;
        RECT  79.632 56.076 79.656 56.16 ;
    END
  END cfg_data[66]
  PIN cfg_data[67]
    DIRECTION INPUT ;
    USE SIGNAL ;
    PORT
      LAYER M5 ;
        RECT  79.728 56.076 79.752 56.16 ;
    END
  END cfg_data[67]
  PIN cfg_data[68]
    DIRECTION INPUT ;
    USE SIGNAL ;
    PORT
      LAYER M5 ;
        RECT  79.824 56.076 79.848 56.16 ;
    END
  END cfg_data[68]
  PIN cfg_data[69]
    DIRECTION INPUT ;
    USE SIGNAL ;
    PORT
      LAYER M5 ;
        RECT  79.92 56.076 79.944 56.16 ;
    END
  END cfg_data[69]
  PIN cfg_data[6]
    DIRECTION INPUT ;
    USE SIGNAL ;
    PORT
      LAYER M5 ;
        RECT  70.8 56.076 70.824 56.16 ;
    END
  END cfg_data[6]
  PIN cfg_data[70]
    DIRECTION INPUT ;
    USE SIGNAL ;
    PORT
      LAYER M5 ;
        RECT  80.016 56.076 80.04 56.16 ;
    END
  END cfg_data[70]
  PIN cfg_data[71]
    DIRECTION INPUT ;
    USE SIGNAL ;
    PORT
      LAYER M5 ;
        RECT  80.112 56.076 80.136 56.16 ;
    END
  END cfg_data[71]
  PIN cfg_data[72]
    DIRECTION INPUT ;
    USE SIGNAL ;
    PORT
      LAYER M5 ;
        RECT  80.208 56.076 80.232 56.16 ;
    END
  END cfg_data[72]
  PIN cfg_data[73]
    DIRECTION INPUT ;
    USE SIGNAL ;
    PORT
      LAYER M5 ;
        RECT  80.304 56.076 80.328 56.16 ;
    END
  END cfg_data[73]
  PIN cfg_data[74]
    DIRECTION INPUT ;
    USE SIGNAL ;
    PORT
      LAYER M5 ;
        RECT  80.4 56.076 80.424 56.16 ;
    END
  END cfg_data[74]
  PIN cfg_data[75]
    DIRECTION INPUT ;
    USE SIGNAL ;
    PORT
      LAYER M5 ;
        RECT  80.496 56.076 80.52 56.16 ;
    END
  END cfg_data[75]
  PIN cfg_data[76]
    DIRECTION INPUT ;
    USE SIGNAL ;
    PORT
      LAYER M5 ;
        RECT  80.592 56.076 80.616 56.16 ;
    END
  END cfg_data[76]
  PIN cfg_data[77]
    DIRECTION INPUT ;
    USE SIGNAL ;
    PORT
      LAYER M5 ;
        RECT  80.688 56.076 80.712 56.16 ;
    END
  END cfg_data[77]
  PIN cfg_data[78]
    DIRECTION INPUT ;
    USE SIGNAL ;
    PORT
      LAYER M5 ;
        RECT  80.784 56.076 80.808 56.16 ;
    END
  END cfg_data[78]
  PIN cfg_data[79]
    DIRECTION INPUT ;
    USE SIGNAL ;
    PORT
      LAYER M5 ;
        RECT  80.88 56.076 80.904 56.16 ;
    END
  END cfg_data[79]
  PIN cfg_data[7]
    DIRECTION INPUT ;
    USE SIGNAL ;
    PORT
      LAYER M5 ;
        RECT  70.896 56.076 70.92 56.16 ;
    END
  END cfg_data[7]
  PIN cfg_data[80]
    DIRECTION INPUT ;
    USE SIGNAL ;
    PORT
      LAYER M5 ;
        RECT  80.976 56.076 81 56.16 ;
    END
  END cfg_data[80]
  PIN cfg_data[81]
    DIRECTION INPUT ;
    USE SIGNAL ;
    PORT
      LAYER M5 ;
        RECT  81.072 56.076 81.096 56.16 ;
    END
  END cfg_data[81]
  PIN cfg_data[82]
    DIRECTION INPUT ;
    USE SIGNAL ;
    PORT
      LAYER M5 ;
        RECT  81.168 56.076 81.192 56.16 ;
    END
  END cfg_data[82]
  PIN cfg_data[83]
    DIRECTION INPUT ;
    USE SIGNAL ;
    PORT
      LAYER M5 ;
        RECT  81.264 56.076 81.288 56.16 ;
    END
  END cfg_data[83]
  PIN cfg_data[84]
    DIRECTION INPUT ;
    USE SIGNAL ;
    PORT
      LAYER M5 ;
        RECT  62.928 56.076 62.952 56.16 ;
    END
  END cfg_data[84]
  PIN cfg_data[85]
    DIRECTION INPUT ;
    USE SIGNAL ;
    PORT
      LAYER M5 ;
        RECT  63.024 56.076 63.048 56.16 ;
    END
  END cfg_data[85]
  PIN cfg_data[86]
    DIRECTION INPUT ;
    USE SIGNAL ;
    PORT
      LAYER M5 ;
        RECT  63.12 56.076 63.144 56.16 ;
    END
  END cfg_data[86]
  PIN cfg_data[87]
    DIRECTION INPUT ;
    USE SIGNAL ;
    PORT
      LAYER M5 ;
        RECT  63.216 56.076 63.24 56.16 ;
    END
  END cfg_data[87]
  PIN cfg_data[88]
    DIRECTION INPUT ;
    USE SIGNAL ;
    PORT
      LAYER M5 ;
        RECT  63.312 56.076 63.336 56.16 ;
    END
  END cfg_data[88]
  PIN cfg_data[89]
    DIRECTION INPUT ;
    USE SIGNAL ;
    PORT
      LAYER M5 ;
        RECT  63.408 56.076 63.432 56.16 ;
    END
  END cfg_data[89]
  PIN cfg_data[8]
    DIRECTION INPUT ;
    USE SIGNAL ;
    PORT
      LAYER M5 ;
        RECT  70.992 56.076 71.016 56.16 ;
    END
  END cfg_data[8]
  PIN cfg_data[90]
    DIRECTION INPUT ;
    USE SIGNAL ;
    PORT
      LAYER M5 ;
        RECT  63.504 56.076 63.528 56.16 ;
    END
  END cfg_data[90]
  PIN cfg_data[91]
    DIRECTION INPUT ;
    USE SIGNAL ;
    PORT
      LAYER M5 ;
        RECT  63.6 56.076 63.624 56.16 ;
    END
  END cfg_data[91]
  PIN cfg_data[92]
    DIRECTION INPUT ;
    USE SIGNAL ;
    PORT
      LAYER M5 ;
        RECT  63.696 56.076 63.72 56.16 ;
    END
  END cfg_data[92]
  PIN cfg_data[93]
    DIRECTION INPUT ;
    USE SIGNAL ;
    PORT
      LAYER M5 ;
        RECT  63.792 56.076 63.816 56.16 ;
    END
  END cfg_data[93]
  PIN cfg_data[94]
    DIRECTION INPUT ;
    USE SIGNAL ;
    PORT
      LAYER M5 ;
        RECT  63.888 56.076 63.912 56.16 ;
    END
  END cfg_data[94]
  PIN cfg_data[95]
    DIRECTION INPUT ;
    USE SIGNAL ;
    PORT
      LAYER M5 ;
        RECT  63.984 56.076 64.008 56.16 ;
    END
  END cfg_data[95]
  PIN cfg_data[96]
    DIRECTION INPUT ;
    USE SIGNAL ;
    PORT
      LAYER M5 ;
        RECT  64.08 56.076 64.104 56.16 ;
    END
  END cfg_data[96]
  PIN cfg_data[97]
    DIRECTION INPUT ;
    USE SIGNAL ;
    PORT
      LAYER M5 ;
        RECT  64.176 56.076 64.2 56.16 ;
    END
  END cfg_data[97]
  PIN cfg_data[98]
    DIRECTION INPUT ;
    USE SIGNAL ;
    PORT
      LAYER M5 ;
        RECT  64.272 56.076 64.296 56.16 ;
    END
  END cfg_data[98]
  PIN cfg_data[99]
    DIRECTION INPUT ;
    USE SIGNAL ;
    PORT
      LAYER M5 ;
        RECT  64.368 56.076 64.392 56.16 ;
    END
  END cfg_data[99]
  PIN cfg_data[9]
    DIRECTION INPUT ;
    USE SIGNAL ;
    PORT
      LAYER M5 ;
        RECT  71.088 56.076 71.112 56.16 ;
    END
  END cfg_data[9]
  PIN cfg_target[0]
    DIRECTION INPUT ;
    USE SIGNAL ;
    PORT
      LAYER M5 ;
        RECT  67.152 56.076 67.176 56.16 ;
    END
  END cfg_target[0]
  PIN cfg_target[1]
    DIRECTION INPUT ;
    USE SIGNAL ;
    PORT
      LAYER M5 ;
        RECT  67.248 56.076 67.272 56.16 ;
    END
  END cfg_target[1]
  PIN cfg_target[2]
    DIRECTION INPUT ;
    USE SIGNAL ;
    PORT
      LAYER M5 ;
        RECT  67.344 56.076 67.368 56.16 ;
    END
  END cfg_target[2]
  PIN cfg_target[3]
    DIRECTION INPUT ;
    USE SIGNAL ;
    PORT
      LAYER M5 ;
        RECT  67.44 56.076 67.464 56.16 ;
    END
  END cfg_target[3]
  PIN cfg_target[4]
    DIRECTION INPUT ;
    USE SIGNAL ;
    PORT
      LAYER M5 ;
        RECT  67.536 56.076 67.56 56.16 ;
    END
  END cfg_target[4]
  PIN cfg_target[5]
    DIRECTION INPUT ;
    USE SIGNAL ;
    PORT
      LAYER M5 ;
        RECT  67.632 56.076 67.656 56.16 ;
    END
  END cfg_target[5]
  PIN cfg_target[6]
    DIRECTION INPUT ;
    USE SIGNAL ;
    PORT
      LAYER M5 ;
        RECT  67.728 56.076 67.752 56.16 ;
    END
  END cfg_target[6]
  PIN cfg_target[7]
    DIRECTION INPUT ;
    USE SIGNAL ;
    PORT
      LAYER M5 ;
        RECT  67.824 56.076 67.848 56.16 ;
    END
  END cfg_target[7]
  PIN cfg_v
    DIRECTION INPUT ;
    USE SIGNAL ;
    PORT
      LAYER M5 ;
        RECT  67.92 56.076 67.944 56.16 ;
    END
  END cfg_v
  PIN clk
    DIRECTION INPUT ;
    USE SIGNAL ;
    PORT
      LAYER M5 ;
        RECT  68.016 56.076 68.04 56.16 ;
    END
  END clk
  PIN configured
    DIRECTION OUTPUT ;
    USE SIGNAL ;
    PORT
      LAYER M5 ;
        RECT  68.112 56.076 68.136 56.16 ;
    END
  END configured
  PIN desc_base[0]
    DIRECTION INPUT ;
    USE SIGNAL ;
    PORT
      LAYER M5 ;
        RECT  68.208 56.076 68.232 56.16 ;
    END
  END desc_base[0]
  PIN desc_base[10]
    DIRECTION INPUT ;
    USE SIGNAL ;
    PORT
      LAYER M5 ;
        RECT  75.312 56.076 75.336 56.16 ;
    END
  END desc_base[10]
  PIN desc_base[11]
    DIRECTION INPUT ;
    USE SIGNAL ;
    PORT
      LAYER M5 ;
        RECT  75.408 56.076 75.432 56.16 ;
    END
  END desc_base[11]
  PIN desc_base[1]
    DIRECTION INPUT ;
    USE SIGNAL ;
    PORT
      LAYER M5 ;
        RECT  68.304 56.076 68.328 56.16 ;
    END
  END desc_base[1]
  PIN desc_base[2]
    DIRECTION INPUT ;
    USE SIGNAL ;
    PORT
      LAYER M5 ;
        RECT  68.4 56.076 68.424 56.16 ;
    END
  END desc_base[2]
  PIN desc_base[3]
    DIRECTION INPUT ;
    USE SIGNAL ;
    PORT
      LAYER M5 ;
        RECT  68.496 56.076 68.52 56.16 ;
    END
  END desc_base[3]
  PIN desc_base[4]
    DIRECTION INPUT ;
    USE SIGNAL ;
    PORT
      LAYER M5 ;
        RECT  68.592 56.076 68.616 56.16 ;
    END
  END desc_base[4]
  PIN desc_base[5]
    DIRECTION INPUT ;
    USE SIGNAL ;
    PORT
      LAYER M5 ;
        RECT  68.688 56.076 68.712 56.16 ;
    END
  END desc_base[5]
  PIN desc_base[6]
    DIRECTION INPUT ;
    USE SIGNAL ;
    PORT
      LAYER M5 ;
        RECT  68.784 56.076 68.808 56.16 ;
    END
  END desc_base[6]
  PIN desc_base[7]
    DIRECTION INPUT ;
    USE SIGNAL ;
    PORT
      LAYER M5 ;
        RECT  68.88 56.076 68.904 56.16 ;
    END
  END desc_base[7]
  PIN desc_base[8]
    DIRECTION INPUT ;
    USE SIGNAL ;
    PORT
      LAYER M5 ;
        RECT  68.976 56.076 69 56.16 ;
    END
  END desc_base[8]
  PIN desc_base[9]
    DIRECTION INPUT ;
    USE SIGNAL ;
    PORT
      LAYER M5 ;
        RECT  75.216 56.076 75.24 56.16 ;
    END
  END desc_base[9]
  PIN desc_limit[0]
    DIRECTION INPUT ;
    USE SIGNAL ;
    PORT
      LAYER M5 ;
        RECT  75.504 56.076 75.528 56.16 ;
    END
  END desc_limit[0]
  PIN desc_limit[10]
    DIRECTION INPUT ;
    USE SIGNAL ;
    PORT
      LAYER M5 ;
        RECT  76.464 56.076 76.488 56.16 ;
    END
  END desc_limit[10]
  PIN desc_limit[11]
    DIRECTION INPUT ;
    USE SIGNAL ;
    PORT
      LAYER M5 ;
        RECT  76.56 56.076 76.584 56.16 ;
    END
  END desc_limit[11]
  PIN desc_limit[12]
    DIRECTION INPUT ;
    USE SIGNAL ;
    PORT
      LAYER M5 ;
        RECT  76.656 56.076 76.68 56.16 ;
    END
  END desc_limit[12]
  PIN desc_limit[1]
    DIRECTION INPUT ;
    USE SIGNAL ;
    PORT
      LAYER M5 ;
        RECT  75.6 56.076 75.624 56.16 ;
    END
  END desc_limit[1]
  PIN desc_limit[2]
    DIRECTION INPUT ;
    USE SIGNAL ;
    PORT
      LAYER M5 ;
        RECT  75.696 56.076 75.72 56.16 ;
    END
  END desc_limit[2]
  PIN desc_limit[3]
    DIRECTION INPUT ;
    USE SIGNAL ;
    PORT
      LAYER M5 ;
        RECT  75.792 56.076 75.816 56.16 ;
    END
  END desc_limit[3]
  PIN desc_limit[4]
    DIRECTION INPUT ;
    USE SIGNAL ;
    PORT
      LAYER M5 ;
        RECT  75.888 56.076 75.912 56.16 ;
    END
  END desc_limit[4]
  PIN desc_limit[5]
    DIRECTION INPUT ;
    USE SIGNAL ;
    PORT
      LAYER M5 ;
        RECT  75.984 56.076 76.008 56.16 ;
    END
  END desc_limit[5]
  PIN desc_limit[6]
    DIRECTION INPUT ;
    USE SIGNAL ;
    PORT
      LAYER M5 ;
        RECT  76.08 56.076 76.104 56.16 ;
    END
  END desc_limit[6]
  PIN desc_limit[7]
    DIRECTION INPUT ;
    USE SIGNAL ;
    PORT
      LAYER M5 ;
        RECT  76.176 56.076 76.2 56.16 ;
    END
  END desc_limit[7]
  PIN desc_limit[8]
    DIRECTION INPUT ;
    USE SIGNAL ;
    PORT
      LAYER M5 ;
        RECT  76.272 56.076 76.296 56.16 ;
    END
  END desc_limit[8]
  PIN desc_limit[9]
    DIRECTION INPUT ;
    USE SIGNAL ;
    PORT
      LAYER M5 ;
        RECT  76.368 56.076 76.392 56.16 ;
    END
  END desc_limit[9]
  PIN desc_loops[0]
    DIRECTION INPUT ;
    USE SIGNAL ;
    PORT
      LAYER M5 ;
        RECT  76.752 56.076 76.776 56.16 ;
    END
  END desc_loops[0]
  PIN desc_loops[10]
    DIRECTION INPUT ;
    USE SIGNAL ;
    PORT
      LAYER M5 ;
        RECT  77.712 56.076 77.736 56.16 ;
    END
  END desc_loops[10]
  PIN desc_loops[11]
    DIRECTION INPUT ;
    USE SIGNAL ;
    PORT
      LAYER M5 ;
        RECT  77.808 56.076 77.832 56.16 ;
    END
  END desc_loops[11]
  PIN desc_loops[12]
    DIRECTION INPUT ;
    USE SIGNAL ;
    PORT
      LAYER M5 ;
        RECT  77.904 56.076 77.928 56.16 ;
    END
  END desc_loops[12]
  PIN desc_loops[13]
    DIRECTION INPUT ;
    USE SIGNAL ;
    PORT
      LAYER M5 ;
        RECT  78 56.076 78.024 56.16 ;
    END
  END desc_loops[13]
  PIN desc_loops[14]
    DIRECTION INPUT ;
    USE SIGNAL ;
    PORT
      LAYER M5 ;
        RECT  78.096 56.076 78.12 56.16 ;
    END
  END desc_loops[14]
  PIN desc_loops[15]
    DIRECTION INPUT ;
    USE SIGNAL ;
    PORT
      LAYER M5 ;
        RECT  78.192 56.076 78.216 56.16 ;
    END
  END desc_loops[15]
  PIN desc_loops[1]
    DIRECTION INPUT ;
    USE SIGNAL ;
    PORT
      LAYER M5 ;
        RECT  76.848 56.076 76.872 56.16 ;
    END
  END desc_loops[1]
  PIN desc_loops[2]
    DIRECTION INPUT ;
    USE SIGNAL ;
    PORT
      LAYER M5 ;
        RECT  76.944 56.076 76.968 56.16 ;
    END
  END desc_loops[2]
  PIN desc_loops[3]
    DIRECTION INPUT ;
    USE SIGNAL ;
    PORT
      LAYER M5 ;
        RECT  77.04 56.076 77.064 56.16 ;
    END
  END desc_loops[3]
  PIN desc_loops[4]
    DIRECTION INPUT ;
    USE SIGNAL ;
    PORT
      LAYER M5 ;
        RECT  77.136 56.076 77.16 56.16 ;
    END
  END desc_loops[4]
  PIN desc_loops[5]
    DIRECTION INPUT ;
    USE SIGNAL ;
    PORT
      LAYER M5 ;
        RECT  77.232 56.076 77.256 56.16 ;
    END
  END desc_loops[5]
  PIN desc_loops[6]
    DIRECTION INPUT ;
    USE SIGNAL ;
    PORT
      LAYER M5 ;
        RECT  77.328 56.076 77.352 56.16 ;
    END
  END desc_loops[6]
  PIN desc_loops[7]
    DIRECTION INPUT ;
    USE SIGNAL ;
    PORT
      LAYER M5 ;
        RECT  77.424 56.076 77.448 56.16 ;
    END
  END desc_loops[7]
  PIN desc_loops[8]
    DIRECTION INPUT ;
    USE SIGNAL ;
    PORT
      LAYER M5 ;
        RECT  77.52 56.076 77.544 56.16 ;
    END
  END desc_loops[8]
  PIN desc_loops[9]
    DIRECTION INPUT ;
    USE SIGNAL ;
    PORT
      LAYER M5 ;
        RECT  77.616 56.076 77.64 56.16 ;
    END
  END desc_loops[9]
  PIN desc_v
    DIRECTION INPUT ;
    USE SIGNAL ;
    PORT
      LAYER M5 ;
        RECT  59.856 56.076 59.88 56.16 ;
    END
  END desc_v
  PIN fault
    DIRECTION OUTPUT ;
    USE SIGNAL ;
    PORT
      LAYER M5 ;
        RECT  59.952 56.076 59.976 56.16 ;
    END
  END fault
  PIN fault_cause[0]
    DIRECTION OUTPUT ;
    USE SIGNAL ;
    PORT
      LAYER M5 ;
        RECT  60.048 56.076 60.072 56.16 ;
    END
  END fault_cause[0]
  PIN fault_cause[10]
    DIRECTION OUTPUT ;
    USE SIGNAL ;
    PORT
      LAYER M5 ;
        RECT  61.008 56.076 61.032 56.16 ;
    END
  END fault_cause[10]
  PIN fault_cause[11]
    DIRECTION OUTPUT ;
    USE SIGNAL ;
    PORT
      LAYER M5 ;
        RECT  61.104 56.076 61.128 56.16 ;
    END
  END fault_cause[11]
  PIN fault_cause[12]
    DIRECTION OUTPUT ;
    USE SIGNAL ;
    PORT
      LAYER M5 ;
        RECT  61.2 56.076 61.224 56.16 ;
    END
  END fault_cause[12]
  PIN fault_cause[13]
    DIRECTION OUTPUT ;
    USE SIGNAL ;
    PORT
      LAYER M5 ;
        RECT  61.296 56.076 61.32 56.16 ;
    END
  END fault_cause[13]
  PIN fault_cause[14]
    DIRECTION OUTPUT ;
    USE SIGNAL ;
    PORT
      LAYER M5 ;
        RECT  61.392 56.076 61.416 56.16 ;
    END
  END fault_cause[14]
  PIN fault_cause[15]
    DIRECTION OUTPUT ;
    USE SIGNAL ;
    PORT
      LAYER M5 ;
        RECT  61.488 56.076 61.512 56.16 ;
    END
  END fault_cause[15]
  PIN fault_cause[1]
    DIRECTION OUTPUT ;
    USE SIGNAL ;
    PORT
      LAYER M5 ;
        RECT  60.144 56.076 60.168 56.16 ;
    END
  END fault_cause[1]
  PIN fault_cause[2]
    DIRECTION OUTPUT ;
    USE SIGNAL ;
    PORT
      LAYER M5 ;
        RECT  60.24 56.076 60.264 56.16 ;
    END
  END fault_cause[2]
  PIN fault_cause[3]
    DIRECTION OUTPUT ;
    USE SIGNAL ;
    PORT
      LAYER M5 ;
        RECT  60.336 56.076 60.36 56.16 ;
    END
  END fault_cause[3]
  PIN fault_cause[4]
    DIRECTION OUTPUT ;
    USE SIGNAL ;
    PORT
      LAYER M5 ;
        RECT  60.432 56.076 60.456 56.16 ;
    END
  END fault_cause[4]
  PIN fault_cause[5]
    DIRECTION OUTPUT ;
    USE SIGNAL ;
    PORT
      LAYER M5 ;
        RECT  60.528 56.076 60.552 56.16 ;
    END
  END fault_cause[5]
  PIN fault_cause[6]
    DIRECTION OUTPUT ;
    USE SIGNAL ;
    PORT
      LAYER M5 ;
        RECT  60.624 56.076 60.648 56.16 ;
    END
  END fault_cause[6]
  PIN fault_cause[7]
    DIRECTION OUTPUT ;
    USE SIGNAL ;
    PORT
      LAYER M5 ;
        RECT  60.72 56.076 60.744 56.16 ;
    END
  END fault_cause[7]
  PIN fault_cause[8]
    DIRECTION OUTPUT ;
    USE SIGNAL ;
    PORT
      LAYER M5 ;
        RECT  60.816 56.076 60.84 56.16 ;
    END
  END fault_cause[8]
  PIN fault_cause[9]
    DIRECTION OUTPUT ;
    USE SIGNAL ;
    PORT
      LAYER M5 ;
        RECT  60.912 56.076 60.936 56.16 ;
    END
  END fault_cause[9]
  PIN init_busy
    DIRECTION OUTPUT ;
    USE SIGNAL ;
    PORT
      LAYER M5 ;
        RECT  61.584 56.076 61.608 56.16 ;
    END
  END init_busy
  PIN issuer_busy
    DIRECTION INPUT ;
    USE SIGNAL ;
    PORT
      LAYER M5 ;
        RECT  48.336 0 48.36 0.084 ;
    END
  END issuer_busy
  PIN issuer_cfg[0]
    DIRECTION OUTPUT ;
    USE SIGNAL ;
    PORT
      LAYER M5 ;
        RECT  48.432 0 48.456 0.084 ;
    END
  END issuer_cfg[0]
  PIN issuer_cfg[10]
    DIRECTION OUTPUT ;
    USE SIGNAL ;
    PORT
      LAYER M5 ;
        RECT  49.392 0 49.416 0.084 ;
    END
  END issuer_cfg[10]
  PIN issuer_cfg[11]
    DIRECTION OUTPUT ;
    USE SIGNAL ;
    PORT
      LAYER M5 ;
        RECT  49.488 0 49.512 0.084 ;
    END
  END issuer_cfg[11]
  PIN issuer_cfg[12]
    DIRECTION OUTPUT ;
    USE SIGNAL ;
    PORT
      LAYER M5 ;
        RECT  49.584 0 49.608 0.084 ;
    END
  END issuer_cfg[12]
  PIN issuer_cfg[13]
    DIRECTION OUTPUT ;
    USE SIGNAL ;
    PORT
      LAYER M5 ;
        RECT  49.68 0 49.704 0.084 ;
    END
  END issuer_cfg[13]
  PIN issuer_cfg[14]
    DIRECTION OUTPUT ;
    USE SIGNAL ;
    PORT
      LAYER M5 ;
        RECT  49.776 0 49.8 0.084 ;
    END
  END issuer_cfg[14]
  PIN issuer_cfg[15]
    DIRECTION OUTPUT ;
    USE SIGNAL ;
    PORT
      LAYER M5 ;
        RECT  49.872 0 49.896 0.084 ;
    END
  END issuer_cfg[15]
  PIN issuer_cfg[16]
    DIRECTION OUTPUT ;
    USE SIGNAL ;
    PORT
      LAYER M5 ;
        RECT  49.968 0 49.992 0.084 ;
    END
  END issuer_cfg[16]
  PIN issuer_cfg[17]
    DIRECTION OUTPUT ;
    USE SIGNAL ;
    PORT
      LAYER M5 ;
        RECT  50.064 0 50.088 0.084 ;
    END
  END issuer_cfg[17]
  PIN issuer_cfg[18]
    DIRECTION OUTPUT ;
    USE SIGNAL ;
    PORT
      LAYER M5 ;
        RECT  50.16 0 50.184 0.084 ;
    END
  END issuer_cfg[18]
  PIN issuer_cfg[19]
    DIRECTION OUTPUT ;
    USE SIGNAL ;
    PORT
      LAYER M5 ;
        RECT  50.256 0 50.28 0.084 ;
    END
  END issuer_cfg[19]
  PIN issuer_cfg[1]
    DIRECTION OUTPUT ;
    USE SIGNAL ;
    PORT
      LAYER M5 ;
        RECT  48.528 0 48.552 0.084 ;
    END
  END issuer_cfg[1]
  PIN issuer_cfg[20]
    DIRECTION OUTPUT ;
    USE SIGNAL ;
    PORT
      LAYER M5 ;
        RECT  50.352 0 50.376 0.084 ;
    END
  END issuer_cfg[20]
  PIN issuer_cfg[21]
    DIRECTION OUTPUT ;
    USE SIGNAL ;
    PORT
      LAYER M5 ;
        RECT  50.448 0 50.472 0.084 ;
    END
  END issuer_cfg[21]
  PIN issuer_cfg[22]
    DIRECTION OUTPUT ;
    USE SIGNAL ;
    PORT
      LAYER M5 ;
        RECT  50.544 0 50.568 0.084 ;
    END
  END issuer_cfg[22]
  PIN issuer_cfg[23]
    DIRECTION OUTPUT ;
    USE SIGNAL ;
    PORT
      LAYER M5 ;
        RECT  50.64 0 50.664 0.084 ;
    END
  END issuer_cfg[23]
  PIN issuer_cfg[24]
    DIRECTION OUTPUT ;
    USE SIGNAL ;
    PORT
      LAYER M5 ;
        RECT  50.736 0 50.76 0.084 ;
    END
  END issuer_cfg[24]
  PIN issuer_cfg[25]
    DIRECTION OUTPUT ;
    USE SIGNAL ;
    PORT
      LAYER M5 ;
        RECT  50.832 0 50.856 0.084 ;
    END
  END issuer_cfg[25]
  PIN issuer_cfg[26]
    DIRECTION OUTPUT ;
    USE SIGNAL ;
    PORT
      LAYER M5 ;
        RECT  50.928 0 50.952 0.084 ;
    END
  END issuer_cfg[26]
  PIN issuer_cfg[27]
    DIRECTION OUTPUT ;
    USE SIGNAL ;
    PORT
      LAYER M5 ;
        RECT  51.024 0 51.048 0.084 ;
    END
  END issuer_cfg[27]
  PIN issuer_cfg[28]
    DIRECTION OUTPUT ;
    USE SIGNAL ;
    PORT
      LAYER M5 ;
        RECT  51.12 0 51.144 0.084 ;
    END
  END issuer_cfg[28]
  PIN issuer_cfg[29]
    DIRECTION OUTPUT ;
    USE SIGNAL ;
    PORT
      LAYER M5 ;
        RECT  51.216 0 51.24 0.084 ;
    END
  END issuer_cfg[29]
  PIN issuer_cfg[2]
    DIRECTION OUTPUT ;
    USE SIGNAL ;
    PORT
      LAYER M5 ;
        RECT  48.624 0 48.648 0.084 ;
    END
  END issuer_cfg[2]
  PIN issuer_cfg[30]
    DIRECTION OUTPUT ;
    USE SIGNAL ;
    PORT
      LAYER M5 ;
        RECT  51.312 0 51.336 0.084 ;
    END
  END issuer_cfg[30]
  PIN issuer_cfg[31]
    DIRECTION OUTPUT ;
    USE SIGNAL ;
    PORT
      LAYER M5 ;
        RECT  66.768 0 66.792 0.084 ;
    END
  END issuer_cfg[31]
  PIN issuer_cfg[32]
    DIRECTION OUTPUT ;
    USE SIGNAL ;
    PORT
      LAYER M5 ;
        RECT  66.864 0 66.888 0.084 ;
    END
  END issuer_cfg[32]
  PIN issuer_cfg[33]
    DIRECTION OUTPUT ;
    USE SIGNAL ;
    PORT
      LAYER M5 ;
        RECT  66.96 0 66.984 0.084 ;
    END
  END issuer_cfg[33]
  PIN issuer_cfg[34]
    DIRECTION OUTPUT ;
    USE SIGNAL ;
    PORT
      LAYER M5 ;
        RECT  67.056 0 67.08 0.084 ;
    END
  END issuer_cfg[34]
  PIN issuer_cfg[35]
    DIRECTION OUTPUT ;
    USE SIGNAL ;
    PORT
      LAYER M5 ;
        RECT  67.152 0 67.176 0.084 ;
    END
  END issuer_cfg[35]
  PIN issuer_cfg[36]
    DIRECTION OUTPUT ;
    USE SIGNAL ;
    PORT
      LAYER M5 ;
        RECT  67.248 0 67.272 0.084 ;
    END
  END issuer_cfg[36]
  PIN issuer_cfg[3]
    DIRECTION OUTPUT ;
    USE SIGNAL ;
    PORT
      LAYER M5 ;
        RECT  48.72 0 48.744 0.084 ;
    END
  END issuer_cfg[3]
  PIN issuer_cfg[4]
    DIRECTION OUTPUT ;
    USE SIGNAL ;
    PORT
      LAYER M5 ;
        RECT  48.816 0 48.84 0.084 ;
    END
  END issuer_cfg[4]
  PIN issuer_cfg[5]
    DIRECTION OUTPUT ;
    USE SIGNAL ;
    PORT
      LAYER M5 ;
        RECT  48.912 0 48.936 0.084 ;
    END
  END issuer_cfg[5]
  PIN issuer_cfg[6]
    DIRECTION OUTPUT ;
    USE SIGNAL ;
    PORT
      LAYER M5 ;
        RECT  49.008 0 49.032 0.084 ;
    END
  END issuer_cfg[6]
  PIN issuer_cfg[7]
    DIRECTION OUTPUT ;
    USE SIGNAL ;
    PORT
      LAYER M5 ;
        RECT  49.104 0 49.128 0.084 ;
    END
  END issuer_cfg[7]
  PIN issuer_cfg[8]
    DIRECTION OUTPUT ;
    USE SIGNAL ;
    PORT
      LAYER M5 ;
        RECT  49.2 0 49.224 0.084 ;
    END
  END issuer_cfg[8]
  PIN issuer_cfg[9]
    DIRECTION OUTPUT ;
    USE SIGNAL ;
    PORT
      LAYER M5 ;
        RECT  49.296 0 49.32 0.084 ;
    END
  END issuer_cfg[9]
  PIN issuer_fault
    DIRECTION INPUT ;
    USE SIGNAL ;
    PORT
      LAYER M5 ;
        RECT  67.344 0 67.368 0.084 ;
    END
  END issuer_fault
  PIN issuer_start
    DIRECTION OUTPUT ;
    USE SIGNAL ;
    PORT
      LAYER M5 ;
        RECT  67.44 0 67.464 0.084 ;
    END
  END issuer_start
  PIN issuer_start_pc[0]
    DIRECTION OUTPUT ;
    USE SIGNAL ;
    PORT
      LAYER M5 ;
        RECT  67.536 0 67.56 0.084 ;
    END
  END issuer_start_pc[0]
  PIN issuer_start_pc[1]
    DIRECTION OUTPUT ;
    USE SIGNAL ;
    PORT
      LAYER M5 ;
        RECT  67.632 0 67.656 0.084 ;
    END
  END issuer_start_pc[1]
  PIN issuer_start_pc[2]
    DIRECTION OUTPUT ;
    USE SIGNAL ;
    PORT
      LAYER M5 ;
        RECT  67.728 0 67.752 0.084 ;
    END
  END issuer_start_pc[2]
  PIN issuer_start_pc[3]
    DIRECTION OUTPUT ;
    USE SIGNAL ;
    PORT
      LAYER M5 ;
        RECT  67.824 0 67.848 0.084 ;
    END
  END issuer_start_pc[3]
  PIN issuer_start_pc[4]
    DIRECTION OUTPUT ;
    USE SIGNAL ;
    PORT
      LAYER M5 ;
        RECT  67.92 0 67.944 0.084 ;
    END
  END issuer_start_pc[4]
  PIN issuer_start_pc[5]
    DIRECTION OUTPUT ;
    USE SIGNAL ;
    PORT
      LAYER M5 ;
        RECT  68.016 0 68.04 0.084 ;
    END
  END issuer_start_pc[5]
  PIN issuer_uop_pc[0]
    DIRECTION INPUT ;
    USE SIGNAL ;
    PORT
      LAYER M5 ;
        RECT  68.112 0 68.136 0.084 ;
    END
  END issuer_uop_pc[0]
  PIN issuer_uop_pc[1]
    DIRECTION INPUT ;
    USE SIGNAL ;
    PORT
      LAYER M5 ;
        RECT  68.208 0 68.232 0.084 ;
    END
  END issuer_uop_pc[1]
  PIN issuer_uop_pc[2]
    DIRECTION INPUT ;
    USE SIGNAL ;
    PORT
      LAYER M5 ;
        RECT  68.304 0 68.328 0.084 ;
    END
  END issuer_uop_pc[2]
  PIN issuer_uop_pc[3]
    DIRECTION INPUT ;
    USE SIGNAL ;
    PORT
      LAYER M5 ;
        RECT  68.4 0 68.424 0.084 ;
    END
  END issuer_uop_pc[3]
  PIN issuer_uop_pc[4]
    DIRECTION INPUT ;
    USE SIGNAL ;
    PORT
      LAYER M5 ;
        RECT  68.496 0 68.52 0.084 ;
    END
  END issuer_uop_pc[4]
  PIN issuer_uop_pc[5]
    DIRECTION INPUT ;
    USE SIGNAL ;
    PORT
      LAYER M5 ;
        RECT  68.592 0 68.616 0.084 ;
    END
  END issuer_uop_pc[5]
  PIN issuer_uop_v
    DIRECTION INPUT ;
    USE SIGNAL ;
    PORT
      LAYER M5 ;
        RECT  68.688 0 68.712 0.084 ;
    END
  END issuer_uop_v
  PIN launch_v
    DIRECTION INPUT ;
    USE SIGNAL ;
    PORT
      LAYER M5 ;
        RECT  61.68 56.076 61.704 56.16 ;
    END
  END launch_v
  PIN link_abort[0]
    DIRECTION INPUT ;
    USE SIGNAL ;
    PORT
      LAYER M4 ;
        RECT  0 7.92 0.084 7.944 ;
    END
  END link_abort[0]
  PIN link_abort[1]
    DIRECTION INPUT ;
    USE SIGNAL ;
    PORT
      LAYER M4 ;
        RECT  0 8.016 0.084 8.04 ;
    END
  END link_abort[1]
  PIN program_active
    DIRECTION INPUT ;
    USE SIGNAL ;
    PORT
      LAYER M5 ;
        RECT  68.784 0 68.808 0.084 ;
    END
  END program_active
  PIN program_fault
    DIRECTION OUTPUT ;
    USE SIGNAL ;
    PORT
      LAYER M5 ;
        RECT  61.776 56.076 61.8 56.16 ;
    END
  END program_fault
  PIN protocol_fault
    DIRECTION INPUT ;
    USE SIGNAL ;
    PORT
      LAYER M4 ;
        RECT  81.996 49.392 82.08 49.416 ;
    END
  END protocol_fault
  PIN qid[0]
    DIRECTION INPUT ;
    USE SIGNAL ;
    PORT
      LAYER M5 ;
        RECT  61.872 56.076 61.896 56.16 ;
    END
  END qid[0]
  PIN qid[1]
    DIRECTION INPUT ;
    USE SIGNAL ;
    PORT
      LAYER M5 ;
        RECT  61.968 56.076 61.992 56.16 ;
    END
  END qid[1]
  PIN reduce_fault
    DIRECTION INPUT ;
    USE SIGNAL ;
    PORT
      LAYER M4 ;
        RECT  0 8.112 0.084 8.136 ;
    END
  END reduce_fault
  PIN ring_fault
    DIRECTION INPUT ;
    USE SIGNAL ;
    PORT
      LAYER M4 ;
        RECT  0 8.208 0.084 8.232 ;
    END
  END ring_fault
  PIN rst_n
    DIRECTION INPUT ;
    USE SIGNAL ;
    PORT
      LAYER M5 ;
        RECT  62.064 56.076 62.088 56.16 ;
    END
  END rst_n
  PIN select_fault[0]
    DIRECTION INPUT ;
    USE SIGNAL ;
    PORT
      LAYER M4 ;
        RECT  81.996 49.488 82.08 49.512 ;
    END
  END select_fault[0]
  PIN select_fault[10]
    DIRECTION INPUT ;
    USE SIGNAL ;
    PORT
      LAYER M4 ;
        RECT  81.996 50.448 82.08 50.472 ;
    END
  END select_fault[10]
  PIN select_fault[11]
    DIRECTION INPUT ;
    USE SIGNAL ;
    PORT
      LAYER M4 ;
        RECT  81.996 50.544 82.08 50.568 ;
    END
  END select_fault[11]
  PIN select_fault[12]
    DIRECTION INPUT ;
    USE SIGNAL ;
    PORT
      LAYER M4 ;
        RECT  81.996 50.64 82.08 50.664 ;
    END
  END select_fault[12]
  PIN select_fault[13]
    DIRECTION INPUT ;
    USE SIGNAL ;
    PORT
      LAYER M4 ;
        RECT  81.996 50.736 82.08 50.76 ;
    END
  END select_fault[13]
  PIN select_fault[14]
    DIRECTION INPUT ;
    USE SIGNAL ;
    PORT
      LAYER M4 ;
        RECT  81.996 50.832 82.08 50.856 ;
    END
  END select_fault[14]
  PIN select_fault[15]
    DIRECTION INPUT ;
    USE SIGNAL ;
    PORT
      LAYER M4 ;
        RECT  81.996 50.928 82.08 50.952 ;
    END
  END select_fault[15]
  PIN select_fault[16]
    DIRECTION INPUT ;
    USE SIGNAL ;
    PORT
      LAYER M4 ;
        RECT  81.996 51.024 82.08 51.048 ;
    END
  END select_fault[16]
  PIN select_fault[17]
    DIRECTION INPUT ;
    USE SIGNAL ;
    PORT
      LAYER M4 ;
        RECT  81.996 51.12 82.08 51.144 ;
    END
  END select_fault[17]
  PIN select_fault[1]
    DIRECTION INPUT ;
    USE SIGNAL ;
    PORT
      LAYER M4 ;
        RECT  81.996 49.584 82.08 49.608 ;
    END
  END select_fault[1]
  PIN select_fault[2]
    DIRECTION INPUT ;
    USE SIGNAL ;
    PORT
      LAYER M4 ;
        RECT  81.996 49.68 82.08 49.704 ;
    END
  END select_fault[2]
  PIN select_fault[3]
    DIRECTION INPUT ;
    USE SIGNAL ;
    PORT
      LAYER M4 ;
        RECT  81.996 49.776 82.08 49.8 ;
    END
  END select_fault[3]
  PIN select_fault[4]
    DIRECTION INPUT ;
    USE SIGNAL ;
    PORT
      LAYER M4 ;
        RECT  81.996 49.872 82.08 49.896 ;
    END
  END select_fault[4]
  PIN select_fault[5]
    DIRECTION INPUT ;
    USE SIGNAL ;
    PORT
      LAYER M4 ;
        RECT  81.996 49.968 82.08 49.992 ;
    END
  END select_fault[5]
  PIN select_fault[6]
    DIRECTION INPUT ;
    USE SIGNAL ;
    PORT
      LAYER M4 ;
        RECT  81.996 50.064 82.08 50.088 ;
    END
  END select_fault[6]
  PIN select_fault[7]
    DIRECTION INPUT ;
    USE SIGNAL ;
    PORT
      LAYER M4 ;
        RECT  81.996 50.16 82.08 50.184 ;
    END
  END select_fault[7]
  PIN select_fault[8]
    DIRECTION INPUT ;
    USE SIGNAL ;
    PORT
      LAYER M4 ;
        RECT  81.996 50.256 82.08 50.28 ;
    END
  END select_fault[8]
  PIN select_fault[9]
    DIRECTION INPUT ;
    USE SIGNAL ;
    PORT
      LAYER M4 ;
        RECT  81.996 50.352 82.08 50.376 ;
    END
  END select_fault[9]
  PIN tkm_fault
    DIRECTION INPUT ;
    USE SIGNAL ;
    PORT
      LAYER M4 ;
        RECT  81.996 51.216 82.08 51.24 ;
    END
  END tkm_fault
  PIN unavailable_fault[0]
    DIRECTION INPUT ;
    USE SIGNAL ;
    PORT
      LAYER M4 ;
        RECT  81.996 51.312 82.08 51.336 ;
    END
  END unavailable_fault[0]
  PIN unavailable_fault[10]
    DIRECTION INPUT ;
    USE SIGNAL ;
    PORT
      LAYER M4 ;
        RECT  81.996 52.272 82.08 52.296 ;
    END
  END unavailable_fault[10]
  PIN unavailable_fault[11]
    DIRECTION INPUT ;
    USE SIGNAL ;
    PORT
      LAYER M4 ;
        RECT  81.996 52.368 82.08 52.392 ;
    END
  END unavailable_fault[11]
  PIN unavailable_fault[12]
    DIRECTION INPUT ;
    USE SIGNAL ;
    PORT
      LAYER M4 ;
        RECT  81.996 52.464 82.08 52.488 ;
    END
  END unavailable_fault[12]
  PIN unavailable_fault[13]
    DIRECTION INPUT ;
    USE SIGNAL ;
    PORT
      LAYER M4 ;
        RECT  81.996 52.56 82.08 52.584 ;
    END
  END unavailable_fault[13]
  PIN unavailable_fault[14]
    DIRECTION INPUT ;
    USE SIGNAL ;
    PORT
      LAYER M4 ;
        RECT  81.996 52.656 82.08 52.68 ;
    END
  END unavailable_fault[14]
  PIN unavailable_fault[15]
    DIRECTION INPUT ;
    USE SIGNAL ;
    PORT
      LAYER M4 ;
        RECT  81.996 52.752 82.08 52.776 ;
    END
  END unavailable_fault[15]
  PIN unavailable_fault[16]
    DIRECTION INPUT ;
    USE SIGNAL ;
    PORT
      LAYER M4 ;
        RECT  81.996 52.848 82.08 52.872 ;
    END
  END unavailable_fault[16]
  PIN unavailable_fault[17]
    DIRECTION INPUT ;
    USE SIGNAL ;
    PORT
      LAYER M4 ;
        RECT  81.996 52.944 82.08 52.968 ;
    END
  END unavailable_fault[17]
  PIN unavailable_fault[1]
    DIRECTION INPUT ;
    USE SIGNAL ;
    PORT
      LAYER M4 ;
        RECT  81.996 51.408 82.08 51.432 ;
    END
  END unavailable_fault[1]
  PIN unavailable_fault[2]
    DIRECTION INPUT ;
    USE SIGNAL ;
    PORT
      LAYER M4 ;
        RECT  81.996 51.504 82.08 51.528 ;
    END
  END unavailable_fault[2]
  PIN unavailable_fault[3]
    DIRECTION INPUT ;
    USE SIGNAL ;
    PORT
      LAYER M4 ;
        RECT  81.996 51.6 82.08 51.624 ;
    END
  END unavailable_fault[3]
  PIN unavailable_fault[4]
    DIRECTION INPUT ;
    USE SIGNAL ;
    PORT
      LAYER M4 ;
        RECT  81.996 51.696 82.08 51.72 ;
    END
  END unavailable_fault[4]
  PIN unavailable_fault[5]
    DIRECTION INPUT ;
    USE SIGNAL ;
    PORT
      LAYER M4 ;
        RECT  81.996 51.792 82.08 51.816 ;
    END
  END unavailable_fault[5]
  PIN unavailable_fault[6]
    DIRECTION INPUT ;
    USE SIGNAL ;
    PORT
      LAYER M4 ;
        RECT  81.996 51.888 82.08 51.912 ;
    END
  END unavailable_fault[6]
  PIN unavailable_fault[7]
    DIRECTION INPUT ;
    USE SIGNAL ;
    PORT
      LAYER M4 ;
        RECT  81.996 51.984 82.08 52.008 ;
    END
  END unavailable_fault[7]
  PIN unavailable_fault[8]
    DIRECTION INPUT ;
    USE SIGNAL ;
    PORT
      LAYER M4 ;
        RECT  81.996 52.08 82.08 52.104 ;
    END
  END unavailable_fault[8]
  PIN unavailable_fault[9]
    DIRECTION INPUT ;
    USE SIGNAL ;
    PORT
      LAYER M4 ;
        RECT  81.996 52.176 82.08 52.2 ;
    END
  END unavailable_fault[9]
  PIN writer_fault
    DIRECTION INPUT ;
    USE SIGNAL ;
    PORT
      LAYER M4 ;
        RECT  0 8.304 0.084 8.328 ;
    END
  END writer_fault
  PIN VDD
    DIRECTION INOUT ;
    USE POWER ;
    PORT
      LAYER M5 ;
        RECT  78.192 2.151 78.312 54.009 ;
        RECT  72.792 2.151 72.912 54.009 ;
        RECT  67.392 2.151 67.512 54.009 ;
        RECT  61.992 2.151 62.112 54.009 ;
        RECT  56.592 2.151 56.712 54.009 ;
        RECT  51.192 2.151 51.312 54.009 ;
        RECT  45.792 2.151 45.912 54.009 ;
        RECT  40.392 2.151 40.512 54.009 ;
        RECT  34.992 2.151 35.112 54.009 ;
        RECT  29.592 2.151 29.712 54.009 ;
        RECT  24.192 2.151 24.312 54.009 ;
        RECT  18.792 2.151 18.912 54.009 ;
        RECT  13.392 2.151 13.512 54.009 ;
        RECT  7.992 2.151 8.112 54.009 ;
        RECT  2.592 2.151 2.712 54.009 ;
    END
  END VDD
  PIN VSS
    DIRECTION INOUT ;
    USE GROUND ;
    PORT
      LAYER M5 ;
        RECT  78 2.137 78.12 54.023 ;
        RECT  72.6 2.137 72.72 54.023 ;
        RECT  67.2 2.137 67.32 54.023 ;
        RECT  61.8 2.137 61.92 54.023 ;
        RECT  56.4 2.137 56.52 54.023 ;
        RECT  51 2.137 51.12 54.023 ;
        RECT  45.6 2.137 45.72 54.023 ;
        RECT  40.2 2.137 40.32 54.023 ;
        RECT  34.8 2.137 34.92 54.023 ;
        RECT  29.4 2.137 29.52 54.023 ;
        RECT  24 2.137 24.12 54.023 ;
        RECT  18.6 2.137 18.72 54.023 ;
        RECT  13.2 2.137 13.32 54.023 ;
        RECT  7.8 2.137 7.92 54.023 ;
        RECT  2.4 2.137 2.52 54.023 ;
    END
  END VSS
  OBS
    LAYER RVTN ;
     RECT  2.16 2.16 79.92 2.295 ;
     RECT  2.16 2.565 79.92 2.835 ;
     RECT  2.16 3.105 79.92 3.375 ;
     RECT  2.16 3.645 79.92 3.915 ;
     RECT  2.16 4.185 79.92 4.455 ;
     RECT  2.16 4.725 79.92 4.995 ;
     RECT  2.16 5.265 79.92 5.535 ;
     RECT  2.16 5.805 79.92 6.075 ;
     RECT  2.16 6.345 79.92 6.615 ;
     RECT  2.16 6.885 79.92 7.155 ;
     RECT  2.16 7.425 79.92 7.695 ;
     RECT  2.16 7.965 79.92 8.235 ;
     RECT  2.16 8.505 79.92 8.775 ;
     RECT  2.16 9.045 79.92 9.315 ;
     RECT  2.16 9.585 79.92 9.855 ;
     RECT  2.16 10.125 79.92 10.395 ;
     RECT  2.16 10.665 79.92 10.935 ;
     RECT  2.16 11.205 79.92 11.475 ;
     RECT  2.16 11.745 79.92 12.015 ;
     RECT  2.16 12.285 79.92 12.555 ;
     RECT  2.16 12.825 79.92 13.095 ;
     RECT  2.16 13.365 79.92 13.635 ;
     RECT  2.16 13.905 79.92 14.175 ;
     RECT  2.16 14.445 79.92 14.715 ;
     RECT  2.16 14.985 79.92 15.255 ;
     RECT  2.16 15.525 79.92 15.795 ;
     RECT  2.16 16.065 79.92 16.335 ;
     RECT  2.16 16.605 79.92 16.875 ;
     RECT  2.16 17.145 79.92 17.415 ;
     RECT  2.16 17.685 79.92 17.955 ;
     RECT  2.16 18.225 79.92 18.495 ;
     RECT  2.16 18.765 79.92 19.035 ;
     RECT  2.16 19.305 79.92 19.575 ;
     RECT  2.16 19.845 79.92 20.115 ;
     RECT  2.16 20.385 79.92 20.655 ;
     RECT  2.16 20.925 79.92 21.195 ;
     RECT  2.16 21.465 79.92 21.735 ;
     RECT  2.16 22.005 79.92 22.275 ;
     RECT  2.16 22.545 79.92 22.815 ;
     RECT  2.16 23.085 79.92 23.355 ;
     RECT  2.16 23.625 79.92 23.895 ;
     RECT  2.16 24.165 79.92 24.435 ;
     RECT  2.16 24.705 79.92 24.975 ;
     RECT  2.16 25.245 79.92 25.515 ;
     RECT  2.16 25.785 79.92 26.055 ;
     RECT  2.16 26.325 79.92 26.595 ;
     RECT  2.16 26.865 79.92 27.135 ;
     RECT  2.16 27.405 79.92 27.675 ;
     RECT  2.16 27.945 79.92 28.215 ;
     RECT  2.16 28.485 79.92 28.755 ;
     RECT  2.16 29.025 79.92 29.295 ;
     RECT  2.16 29.565 79.92 29.835 ;
     RECT  2.16 30.105 79.92 30.375 ;
     RECT  2.16 30.645 79.92 30.915 ;
     RECT  2.16 31.185 79.92 31.455 ;
     RECT  2.16 31.725 79.92 31.995 ;
     RECT  2.16 32.265 79.92 32.535 ;
     RECT  2.16 32.805 79.92 33.075 ;
     RECT  2.16 33.345 79.92 33.615 ;
     RECT  2.16 33.885 79.92 34.155 ;
     RECT  2.16 34.425 79.92 34.695 ;
     RECT  2.16 34.965 79.92 35.235 ;
     RECT  2.16 35.505 79.92 35.775 ;
     RECT  2.16 36.045 79.92 36.315 ;
     RECT  2.16 36.585 79.92 36.855 ;
     RECT  2.16 37.125 79.92 37.395 ;
     RECT  2.16 37.665 79.92 37.935 ;
     RECT  2.16 38.205 79.92 38.475 ;
     RECT  2.16 38.745 79.92 39.015 ;
     RECT  2.16 39.285 79.92 39.555 ;
     RECT  2.16 39.825 79.92 40.095 ;
     RECT  2.16 40.365 79.92 40.635 ;
     RECT  2.16 40.905 79.92 41.175 ;
     RECT  2.16 41.445 79.92 41.715 ;
     RECT  2.16 41.985 79.92 42.255 ;
     RECT  2.16 42.525 79.92 42.795 ;
     RECT  2.16 43.065 79.92 43.335 ;
     RECT  2.16 43.605 79.92 43.875 ;
     RECT  2.16 44.145 79.92 44.415 ;
     RECT  2.16 44.685 79.92 44.955 ;
     RECT  2.16 45.225 79.92 45.495 ;
     RECT  2.16 45.765 79.92 46.035 ;
     RECT  2.16 46.305 79.92 46.575 ;
     RECT  2.16 46.845 79.92 47.115 ;
     RECT  2.16 47.385 79.92 47.655 ;
     RECT  2.16 47.925 79.92 48.195 ;
     RECT  2.16 48.465 79.92 48.735 ;
     RECT  2.16 49.005 79.92 49.275 ;
     RECT  2.16 49.545 79.92 49.815 ;
     RECT  2.16 50.085 79.92 50.355 ;
     RECT  2.16 50.625 79.92 50.895 ;
     RECT  2.16 51.165 79.92 51.435 ;
     RECT  2.16 51.705 79.92 51.975 ;
     RECT  2.16 52.245 79.92 52.515 ;
     RECT  2.16 52.785 79.92 53.055 ;
     RECT  2.16 53.325 79.92 53.595 ;
     RECT  2.16 53.865 79.92 54 ;
    LAYER RVTP ;
     RECT  2.16 2.295 79.92 2.565 ;
     RECT  2.16 2.835 79.92 3.105 ;
     RECT  2.16 3.375 79.92 3.645 ;
     RECT  2.16 3.915 79.92 4.185 ;
     RECT  2.16 4.455 79.92 4.725 ;
     RECT  2.16 4.995 79.92 5.265 ;
     RECT  2.16 5.535 79.92 5.805 ;
     RECT  2.16 6.075 79.92 6.345 ;
     RECT  2.16 6.615 79.92 6.885 ;
     RECT  2.16 7.155 79.92 7.425 ;
     RECT  2.16 7.695 79.92 7.965 ;
     RECT  2.16 8.235 79.92 8.505 ;
     RECT  2.16 8.775 79.92 9.045 ;
     RECT  2.16 9.315 79.92 9.585 ;
     RECT  2.16 9.855 79.92 10.125 ;
     RECT  2.16 10.395 79.92 10.665 ;
     RECT  2.16 10.935 79.92 11.205 ;
     RECT  2.16 11.475 79.92 11.745 ;
     RECT  2.16 12.015 79.92 12.285 ;
     RECT  2.16 12.555 79.92 12.825 ;
     RECT  2.16 13.095 79.92 13.365 ;
     RECT  2.16 13.635 79.92 13.905 ;
     RECT  2.16 14.175 79.92 14.445 ;
     RECT  2.16 14.715 79.92 14.985 ;
     RECT  2.16 15.255 79.92 15.525 ;
     RECT  2.16 15.795 79.92 16.065 ;
     RECT  2.16 16.335 79.92 16.605 ;
     RECT  2.16 16.875 79.92 17.145 ;
     RECT  2.16 17.415 79.92 17.685 ;
     RECT  2.16 17.955 79.92 18.225 ;
     RECT  2.16 18.495 79.92 18.765 ;
     RECT  2.16 19.035 79.92 19.305 ;
     RECT  2.16 19.575 79.92 19.845 ;
     RECT  2.16 20.115 79.92 20.385 ;
     RECT  2.16 20.655 79.92 20.925 ;
     RECT  2.16 21.195 79.92 21.465 ;
     RECT  2.16 21.735 79.92 22.005 ;
     RECT  2.16 22.275 79.92 22.545 ;
     RECT  2.16 22.815 79.92 23.085 ;
     RECT  2.16 23.355 79.92 23.625 ;
     RECT  2.16 23.895 79.92 24.165 ;
     RECT  2.16 24.435 79.92 24.705 ;
     RECT  2.16 24.975 79.92 25.245 ;
     RECT  2.16 25.515 79.92 25.785 ;
     RECT  2.16 26.055 79.92 26.325 ;
     RECT  2.16 26.595 79.92 26.865 ;
     RECT  2.16 27.135 79.92 27.405 ;
     RECT  2.16 27.675 79.92 27.945 ;
     RECT  2.16 28.215 79.92 28.485 ;
     RECT  2.16 28.755 79.92 29.025 ;
     RECT  2.16 29.295 79.92 29.565 ;
     RECT  2.16 29.835 79.92 30.105 ;
     RECT  2.16 30.375 79.92 30.645 ;
     RECT  2.16 30.915 79.92 31.185 ;
     RECT  2.16 31.455 79.92 31.725 ;
     RECT  2.16 31.995 79.92 32.265 ;
     RECT  2.16 32.535 79.92 32.805 ;
     RECT  2.16 33.075 79.92 33.345 ;
     RECT  2.16 33.615 79.92 33.885 ;
     RECT  2.16 34.155 79.92 34.425 ;
     RECT  2.16 34.695 79.92 34.965 ;
     RECT  2.16 35.235 79.92 35.505 ;
     RECT  2.16 35.775 79.92 36.045 ;
     RECT  2.16 36.315 79.92 36.585 ;
     RECT  2.16 36.855 79.92 37.125 ;
     RECT  2.16 37.395 79.92 37.665 ;
     RECT  2.16 37.935 79.92 38.205 ;
     RECT  2.16 38.475 79.92 38.745 ;
     RECT  2.16 39.015 79.92 39.285 ;
     RECT  2.16 39.555 79.92 39.825 ;
     RECT  2.16 40.095 79.92 40.365 ;
     RECT  2.16 40.635 79.92 40.905 ;
     RECT  2.16 41.175 79.92 41.445 ;
     RECT  2.16 41.715 79.92 41.985 ;
     RECT  2.16 42.255 79.92 42.525 ;
     RECT  2.16 42.795 79.92 43.065 ;
     RECT  2.16 43.335 79.92 43.605 ;
     RECT  2.16 43.875 79.92 44.145 ;
     RECT  2.16 44.415 79.92 44.685 ;
     RECT  2.16 44.955 79.92 45.225 ;
     RECT  2.16 45.495 79.92 45.765 ;
     RECT  2.16 46.035 79.92 46.305 ;
     RECT  2.16 46.575 79.92 46.845 ;
     RECT  2.16 47.115 79.92 47.385 ;
     RECT  2.16 47.655 79.92 47.925 ;
     RECT  2.16 48.195 79.92 48.465 ;
     RECT  2.16 48.735 79.92 49.005 ;
     RECT  2.16 49.275 79.92 49.545 ;
     RECT  2.16 49.815 79.92 50.085 ;
     RECT  2.16 50.355 79.92 50.625 ;
     RECT  2.16 50.895 79.92 51.165 ;
     RECT  2.16 51.435 79.92 51.705 ;
     RECT  2.16 51.975 79.92 52.245 ;
     RECT  2.16 52.515 79.92 52.785 ;
     RECT  2.16 53.055 79.92 53.325 ;
     RECT  2.16 53.595 79.92 53.865 ;
    LAYER M1 ;
     RECT  2.16 2.151 79.92 54.009 ;
    LAYER M2 ;
     RECT  2.119 51.408 2.155 51.426 ;
     RECT  2.119 50.13 2.16 50.148 ;
     RECT  2.155 51.21 2.16 51.426 ;
     RECT  2.155 53.064 2.16 53.082 ;
     RECT  2.16 2.151 10.867 54.009 ;
     RECT  10.867 2.151 12.803 54.054 ;
     RECT  12.803 2.151 17.599 54.009 ;
     RECT  17.599 2.151 18.959 54.054 ;
     RECT  18.959 2.151 50.179 54.009 ;
     RECT  50.179 2.106 51.251 54.009 ;
     RECT  51.251 2.151 53.239 54.009 ;
     RECT  53.239 2.106 53.879 54.009 ;
     RECT  53.879 2.151 58.711 54.009 ;
     RECT  58.711 2.151 66.163 54.054 ;
     RECT  66.163 2.106 66.703 54.054 ;
     RECT  66.703 2.106 67.055 54.126 ;
     RECT  67.055 2.151 68.719 54.126 ;
     RECT  68.719 2.106 70.223 54.126 ;
     RECT  70.223 2.151 70.771 54.126 ;
     RECT  70.771 2.151 71.555 54.198 ;
     RECT  71.555 2.151 74.471 54.126 ;
     RECT  74.471 2.151 75.595 54.009 ;
     RECT  75.595 2.151 75.803 54.702 ;
     RECT  75.803 2.151 79.92 54.009 ;
     RECT  79.92 40.104 79.943 41.202 ;
     RECT  79.92 43.308 79.979 45.054 ;
     RECT  79.943 40.41 80.015 41.202 ;
     RECT  79.92 50.832 80.015 51.498 ;
     RECT  79.979 43.686 80.051 45.054 ;
     RECT  80.015 40.446 80.087 41.202 ;
     RECT  80.051 44.19 80.159 45.054 ;
     RECT  80.087 40.446 80.303 40.464 ;
     RECT  79.92 52.254 80.411 53.928 ;
     RECT  80.159 44.19 80.663 44.91 ;
     RECT  80.663 44.19 80.771 44.514 ;
     RECT  79.92 46.314 80.987 49.914 ;
     RECT  80.411 53.532 80.987 53.928 ;
     RECT  80.411 52.254 81.059 52.776 ;
     RECT  80.987 53.532 81.095 53.55 ;
     RECT  80.987 46.314 81.239 49.536 ;
     RECT  80.771 44.19 81.275 44.208 ;
     RECT  81.239 46.314 81.311 46.368 ;
     RECT  81.311 46.35 81.383 46.368 ;
     RECT  81.239 47.322 81.491 49.536 ;
     RECT  81.059 52.254 81.491 52.272 ;
     RECT  81.491 49.32 81.527 49.536 ;
     RECT  81.491 47.322 81.599 48.564 ;
     RECT  81.599 47.862 81.707 48.564 ;
     RECT  80.015 50.832 81.787 51.264 ;
     RECT  81.787 50.751 81.895 51.264 ;
     RECT  81.707 47.862 81.923 48.294 ;
     RECT  81.527 49.32 81.923 49.5 ;
     RECT  81.895 50.751 81.967 51.354 ;
     RECT  81.923 47.898 81.995 48.294 ;
     RECT  81.967 50.751 81.995 51.894 ;
     RECT  81.923 49.482 82.031 49.5 ;
     RECT  81.995 50.751 82.031 50.769 ;
     RECT  81.995 47.898 82.067 47.916 ;
     RECT  81.995 51.876 82.067 51.894 ;
    LAYER M3 ;
     RECT  47.628 0.091 47.646 0.139 ;
     RECT  48.6 0.091 48.618 0.139 ;
     RECT  66.852 0.091 67.374 0.139 ;
     RECT  66.636 0.139 67.374 0.187 ;
     RECT  47.628 0.139 48.618 0.571 ;
     RECT  49.788 0.091 49.806 1.147 ;
     RECT  66.636 0.187 67.662 1.147 ;
     RECT  47.304 0.571 48.618 1.723 ;
     RECT  49.788 1.147 50.274 1.723 ;
     RECT  66.636 1.147 67.878 1.723 ;
     RECT  47.304 1.723 50.49 1.771 ;
     RECT  52.92 1.723 52.938 1.771 ;
     RECT  66.636 1.723 67.95 1.771 ;
     RECT  68.868 1.723 68.886 1.771 ;
     RECT  47.304 1.771 50.958 1.819 ;
     RECT  52.596 1.771 52.938 2.101 ;
     RECT  66.636 1.771 68.886 2.101 ;
     RECT  66.168 2.101 68.886 2.107 ;
     RECT  24.015 2.143 24.105 2.191 ;
     RECT  29.415 2.143 29.505 2.191 ;
     RECT  52.596 2.101 53.874 2.191 ;
     RECT  66.168 2.107 69.03 2.191 ;
     RECT  70.2 2.101 70.218 2.191 ;
     RECT  72.615 2.143 72.705 2.191 ;
     RECT  56.415 2.143 56.505 2.227 ;
     RECT  60.228 2.191 60.246 2.227 ;
     RECT  9.864 2.191 9.882 2.251 ;
     RECT  23.976 2.191 24.105 2.263 ;
     RECT  27.792 2.227 27.81 2.263 ;
     RECT  33.408 2.191 33.426 2.263 ;
     RECT  27.792 2.263 27.954 2.293 ;
     RECT  23.328 2.263 24.105 2.299 ;
     RECT  28.944 2.191 29.505 2.299 ;
     RECT  33.336 2.263 33.426 2.299 ;
     RECT  43.308 2.263 43.326 2.299 ;
     RECT  44.46 2.263 44.874 2.299 ;
     RECT  52.308 2.191 53.874 2.299 ;
     RECT  71.172 2.191 71.19 2.299 ;
     RECT  72.108 2.191 73.026 2.299 ;
     RECT  73.836 2.191 73.854 2.299 ;
     RECT  78.015 2.143 78.105 2.299 ;
     RECT  18.615 2.143 18.705 2.335 ;
     RECT  43.308 2.299 44.874 2.335 ;
     RECT  45.615 2.143 45.705 2.335 ;
     RECT  52.308 2.299 54.306 2.335 ;
     RECT  58.716 2.227 59.238 2.335 ;
     RECT  71.172 2.299 73.026 2.335 ;
     RECT  73.764 2.299 73.854 2.335 ;
     RECT  74.844 2.299 75.618 2.335 ;
     RECT  14.22 2.227 14.238 2.347 ;
     RECT  15.3 2.335 15.318 2.347 ;
     RECT  70.992 2.335 73.026 2.347 ;
     RECT  73.764 2.335 75.618 2.347 ;
     RECT  11.592 2.227 11.61 2.371 ;
     RECT  13.215 2.143 13.305 2.371 ;
     RECT  14.22 2.347 14.31 2.371 ;
     RECT  15.3 2.347 15.354 2.371 ;
     RECT  18.108 2.335 18.705 2.371 ;
     RECT  19.476 2.263 19.494 2.371 ;
     RECT  20.556 2.335 20.574 2.371 ;
     RECT  28.764 2.299 29.505 2.371 ;
     RECT  32.868 2.299 33.426 2.371 ;
     RECT  40.215 2.143 40.305 2.371 ;
     RECT  41.904 2.263 42.102 2.371 ;
     RECT  47.304 1.819 51.57 2.371 ;
     RECT  52.308 2.335 54.63 2.371 ;
     RECT  55.98 2.227 56.505 2.371 ;
     RECT  57.276 2.335 57.294 2.371 ;
     RECT  63.252 2.335 63.27 2.371 ;
     RECT  70.992 2.347 76.302 2.371 ;
     RECT  77.58 2.299 78.105 2.371 ;
     RECT  32.688 2.371 33.426 2.395 ;
     RECT  2.415 2.143 2.505 2.413 ;
     RECT  7.815 2.143 7.905 2.413 ;
     RECT  12.528 2.371 13.338 2.413 ;
     RECT  34.815 2.143 34.905 2.413 ;
     RECT  40.215 2.371 40.338 2.413 ;
     RECT  43.308 2.335 45.705 2.413 ;
     RECT  61.815 2.143 61.905 2.413 ;
     RECT  77.544 2.371 78.105 2.413 ;
     RECT  9.684 2.251 9.882 2.461 ;
     RECT  25.488 2.227 25.506 2.461 ;
     RECT  28.764 2.371 29.862 2.461 ;
     RECT  30.78 2.371 30.798 2.461 ;
     RECT  32.688 2.395 33.642 2.461 ;
     RECT  34.815 2.413 35.097 2.461 ;
     RECT  40.215 2.413 40.497 2.461 ;
     RECT  43.308 2.413 45.897 2.461 ;
     RECT  46.908 2.371 54.99 2.461 ;
     RECT  55.98 2.371 57.294 2.461 ;
     RECT  58.716 2.335 59.346 2.461 ;
     RECT  60.228 2.227 60.354 2.461 ;
     RECT  61.815 2.413 62.097 2.461 ;
     RECT  42.948 2.461 45.897 2.491 ;
     RECT  12.528 2.413 13.497 2.497 ;
     RECT  14.22 2.371 15.354 2.497 ;
     RECT  27.648 2.293 27.954 2.497 ;
     RECT  77.544 2.413 78.297 2.497 ;
     RECT  46.908 2.461 57.294 2.525 ;
     RECT  9.684 2.461 10.062 2.533 ;
     RECT  10.8 2.263 10.818 2.533 ;
     RECT  11.592 2.371 11.754 2.533 ;
     RECT  12.528 2.497 15.354 2.533 ;
     RECT  18.108 2.371 20.574 2.533 ;
     RECT  25.488 2.461 26.19 2.533 ;
     RECT  27.576 2.497 27.954 2.533 ;
     RECT  28.764 2.461 30.798 2.569 ;
     RECT  38.52 2.371 38.538 2.569 ;
     RECT  39.888 2.461 40.806 2.569 ;
     RECT  58.14 2.461 60.354 2.587 ;
     RECT  9.684 2.533 11.754 2.605 ;
     RECT  17.28 2.461 17.298 2.605 ;
     RECT  18.108 2.533 20.754 2.605 ;
     RECT  21.924 2.461 21.942 2.605 ;
     RECT  25.488 2.533 27.954 2.605 ;
     RECT  28.764 2.569 30.87 2.605 ;
     RECT  32.112 2.461 35.694 2.605 ;
     RECT  37.584 2.371 37.602 2.605 ;
     RECT  38.412 2.569 38.538 2.605 ;
     RECT  39.888 2.569 40.914 2.605 ;
     RECT  41.724 2.371 42.102 2.605 ;
     RECT  16.344 2.605 16.362 2.641 ;
     RECT  17.28 2.605 20.754 2.641 ;
     RECT  23.184 2.299 24.354 2.641 ;
     RECT  25.2 2.605 27.954 2.641 ;
     RECT  28.764 2.605 35.694 2.641 ;
     RECT  47.088 2.525 57.294 2.641 ;
     RECT  58.068 2.587 60.354 2.641 ;
     RECT  63.144 2.371 63.99 2.641 ;
     RECT  66.168 2.191 70.218 2.641 ;
     RECT  70.992 2.371 76.41 2.641 ;
     RECT  7.815 2.413 8.097 2.731 ;
     RECT  8.892 2.605 11.754 2.731 ;
     RECT  21.924 2.605 22.446 2.731 ;
     RECT  23.184 2.641 35.694 2.731 ;
     RECT  36.72 2.605 36.738 2.731 ;
     RECT  37.512 2.605 38.538 2.731 ;
     RECT  16.344 2.641 16.506 2.767 ;
     RECT  21.924 2.731 35.694 2.767 ;
     RECT  36.72 2.731 38.538 2.767 ;
     RECT  39.888 2.605 42.102 2.767 ;
     RECT  47.088 2.641 60.354 2.779 ;
     RECT  6.984 2.731 7.002 2.803 ;
     RECT  7.815 2.731 11.754 2.803 ;
     RECT  12.492 2.533 15.354 2.803 ;
     RECT  16.164 2.767 16.506 2.803 ;
     RECT  21.924 2.767 38.538 2.803 ;
     RECT  39.456 2.767 42.102 2.803 ;
     RECT  42.84 2.491 45.897 2.803 ;
     RECT  47.088 2.779 60.426 2.803 ;
     RECT  61.56 2.461 62.097 2.803 ;
     RECT  63.072 2.641 63.99 2.803 ;
     RECT  12.492 2.803 16.506 2.827 ;
     RECT  12.492 2.827 16.542 2.839 ;
     RECT  17.28 2.641 20.826 2.839 ;
     RECT  12.492 2.839 20.826 2.858 ;
     RECT  39.456 2.803 45.897 2.875 ;
     RECT  66.168 2.641 76.446 2.875 ;
     RECT  77.184 2.497 78.297 2.875 ;
     RECT  6.984 2.803 11.754 2.911 ;
     RECT  12.492 2.858 20.862 2.911 ;
     RECT  39.456 2.875 46.242 2.911 ;
     RECT  63.072 2.803 64.314 2.911 ;
     RECT  47.088 2.803 62.097 3.073 ;
     RECT  63.072 2.911 64.422 3.073 ;
     RECT  6.984 2.911 20.862 3.109 ;
     RECT  47.088 3.073 64.422 3.115 ;
     RECT  6.984 3.109 20.934 3.145 ;
     RECT  21.672 2.803 38.538 3.145 ;
     RECT  39.42 2.911 46.242 3.145 ;
     RECT  6.984 3.145 46.242 3.307 ;
     RECT  6.84 3.307 46.242 3.379 ;
     RECT  47.088 3.115 64.71 3.379 ;
     RECT  6.48 3.379 46.242 3.415 ;
     RECT  47.016 3.379 64.71 3.415 ;
     RECT  66.168 2.875 78.297 3.415 ;
     RECT  65.88 3.415 78.297 3.451 ;
     RECT  6.48 3.415 64.71 3.541 ;
     RECT  65.88 3.451 78.498 3.541 ;
     RECT  6.48 3.541 78.498 3.569 ;
     RECT  6.48 3.569 65.25 3.641 ;
     RECT  9.576 3.641 65.25 3.839 ;
     RECT  9.576 3.839 60.138 3.911 ;
     RECT  9.576 3.911 60.066 3.917 ;
     RECT  60.948 3.839 65.25 3.947 ;
     RECT  65.988 3.569 78.498 3.955 ;
     RECT  79.272 3.721 79.29 3.955 ;
     RECT  6.48 3.641 8.802 4.261 ;
     RECT  65.988 3.955 79.29 4.261 ;
     RECT  9.576 3.917 39.078 4.379 ;
     RECT  6.336 4.261 8.802 4.387 ;
     RECT  9.576 4.379 39.006 4.387 ;
     RECT  6.336 4.387 39.006 4.621 ;
     RECT  65.988 4.261 79.362 4.721 ;
     RECT  65.988 4.721 78.894 4.729 ;
     RECT  60.948 3.947 65.214 4.765 ;
     RECT  65.952 4.729 78.894 4.765 ;
     RECT  40.215 3.917 60.066 4.801 ;
     RECT  60.948 4.765 78.894 4.955 ;
     RECT  5.508 4.621 39.006 4.963 ;
     RECT  5.148 4.963 39.006 4.999 ;
     RECT  40.215 4.801 60.21 4.999 ;
     RECT  60.948 4.955 78.786 4.999 ;
     RECT  4.248 4.801 4.266 5.071 ;
     RECT  5.04 4.999 39.006 5.071 ;
     RECT  40.215 4.999 78.786 5.131 ;
     RECT  4.248 5.071 39.006 5.161 ;
     RECT  39.78 5.131 78.786 5.161 ;
     RECT  4.248 5.161 78.786 5.611 ;
     RECT  3.924 5.611 78.786 5.881 ;
     RECT  3.924 5.881 78.966 6.241 ;
     RECT  2.415 2.413 2.697 6.283 ;
     RECT  3.564 6.241 78.966 6.283 ;
     RECT  2.415 6.283 78.966 6.817 ;
     RECT  2.415 6.817 79.254 7.195 ;
     RECT  2.304 7.195 79.254 7.465 ;
     RECT  2.304 7.465 79.578 7.619 ;
     RECT  2.304 7.619 79.29 8.771 ;
     RECT  2.304 8.771 13.986 9.275 ;
     RECT  14.832 8.771 79.29 9.347 ;
     RECT  2.415 9.275 13.986 9.581 ;
     RECT  14.832 9.347 79.074 9.661 ;
     RECT  5.364 9.581 13.986 9.787 ;
     RECT  14.76 9.661 79.074 9.787 ;
     RECT  5.364 9.787 79.074 9.887 ;
     RECT  2.415 9.581 4.59 10.399 ;
     RECT  5.364 9.887 78.966 10.399 ;
     RECT  2.415 10.399 78.966 11.209 ;
     RECT  2.415 11.209 79.218 11.245 ;
     RECT  2.415 11.245 79.794 11.399 ;
     RECT  2.415 11.399 79.218 11.543 ;
     RECT  2.415 11.543 79.146 11.939 ;
     RECT  2.415 11.939 78.93 13.027 ;
     RECT  2.415 13.027 79.218 13.711 ;
     RECT  2.415 13.711 79.578 13.829 ;
     RECT  2.415 13.829 79.146 15.331 ;
     RECT  2.415 15.331 79.47 16.105 ;
     RECT  2.415 16.105 79.506 16.259 ;
     RECT  2.415 16.259 79.254 16.601 ;
     RECT  2.415 16.601 79.218 17.725 ;
     RECT  2.415 17.725 79.506 17.915 ;
     RECT  2.415 17.915 22.338 18.029 ;
     RECT  23.076 17.915 79.506 18.059 ;
     RECT  23.364 18.059 79.506 18.149 ;
     RECT  23.364 18.149 79.074 18.185 ;
     RECT  2.415 18.029 3.438 18.419 ;
     RECT  4.428 18.029 22.338 18.955 ;
     RECT  4.392 18.955 22.338 19.111 ;
     RECT  23.364 18.185 78.93 19.201 ;
     RECT  4.392 19.111 22.41 19.237 ;
     RECT  23.328 19.201 78.93 19.237 ;
     RECT  4.392 19.237 78.93 19.265 ;
     RECT  4.68 19.265 78.93 19.345 ;
     RECT  4.68 19.345 79.218 19.373 ;
     RECT  65.412 19.373 79.218 19.381 ;
     RECT  4.788 19.373 4.95 19.499 ;
     RECT  5.724 19.373 64.386 19.499 ;
     RECT  65.412 19.381 79.686 19.499 ;
     RECT  4.788 19.499 4.806 19.535 ;
     RECT  65.412 19.499 79.218 19.643 ;
     RECT  65.412 19.643 78.642 19.679 ;
     RECT  5.76 19.499 64.386 19.805 ;
     RECT  65.628 19.679 78.642 19.877 ;
     RECT  5.76 19.805 25.65 19.913 ;
     RECT  5.76 19.913 11.646 19.949 ;
     RECT  26.532 19.805 64.386 19.949 ;
     RECT  2.415 18.419 2.697 20.011 ;
     RECT  12.384 19.913 25.65 20.075 ;
     RECT  26.64 19.949 30.114 20.075 ;
     RECT  2.415 20.011 3.294 20.083 ;
     RECT  12.384 20.075 15.606 20.147 ;
     RECT  2.415 20.083 3.978 20.191 ;
     RECT  16.38 20.075 25.65 20.219 ;
     RECT  5.76 19.949 9.378 20.281 ;
     RECT  10.152 19.949 11.646 20.309 ;
     RECT  2.415 20.191 4.122 20.317 ;
     RECT  5.04 20.281 9.378 20.317 ;
     RECT  14.832 20.147 15.606 20.345 ;
     RECT  16.38 20.219 25.218 20.489 ;
     RECT  30.852 19.949 64.386 20.551 ;
     RECT  65.628 19.877 78.606 20.551 ;
     RECT  16.38 20.489 24.498 20.579 ;
     RECT  30.852 20.551 78.606 20.579 ;
     RECT  30.996 20.579 78.606 20.659 ;
     RECT  30.996 20.659 78.678 20.669 ;
     RECT  61.815 20.669 78.678 20.695 ;
     RECT  61.815 20.695 79.038 20.731 ;
     RECT  16.38 20.579 21.474 20.821 ;
     RECT  26.784 20.075 30.114 20.849 ;
     RECT  30.996 20.669 61.074 20.849 ;
     RECT  31.104 20.849 61.074 20.885 ;
     RECT  12.384 20.147 13.95 20.893 ;
     RECT  14.832 20.345 14.85 20.893 ;
     RECT  31.176 20.885 61.074 20.957 ;
     RECT  31.176 20.957 45.954 20.993 ;
     RECT  25.452 21.091 25.686 21.115 ;
     RECT  26.784 20.849 30.078 21.119 ;
     RECT  15.768 20.821 21.474 21.127 ;
     RECT  2.415 20.317 9.378 21.155 ;
     RECT  15.588 21.127 21.474 21.155 ;
     RECT  31.284 20.993 45.954 21.155 ;
     RECT  25.452 21.115 25.83 21.163 ;
     RECT  26.784 21.119 27.738 21.163 ;
     RECT  6.156 21.155 9.378 21.191 ;
     RECT  12.384 20.893 14.85 21.211 ;
     RECT  15.588 21.155 21.15 21.211 ;
     RECT  10.296 20.309 11.646 21.271 ;
     RECT  12.384 21.211 21.15 21.271 ;
     RECT  61.815 20.731 79.47 21.271 ;
     RECT  22.212 20.579 24.498 21.361 ;
     RECT  25.452 21.163 27.738 21.361 ;
     RECT  22.212 21.361 27.738 21.433 ;
     RECT  6.372 21.191 9.378 21.505 ;
     RECT  10.296 21.271 21.15 21.505 ;
     RECT  46.728 20.957 61.074 21.541 ;
     RECT  61.815 21.271 79.578 21.541 ;
     RECT  6.372 21.505 21.15 21.569 ;
     RECT  31.284 21.155 45.897 21.569 ;
     RECT  12.888 21.569 21.15 21.901 ;
     RECT  22.068 21.433 27.738 21.937 ;
     RECT  28.584 21.119 30.078 21.937 ;
     RECT  46.728 21.541 79.578 21.965 ;
     RECT  12.888 21.901 21.222 21.973 ;
     RECT  22.032 21.937 27.738 21.973 ;
     RECT  28.476 21.937 30.078 21.973 ;
     RECT  2.415 21.155 5.382 21.979 ;
     RECT  6.372 21.569 12.006 21.979 ;
     RECT  77.472 21.965 79.578 22.001 ;
     RECT  31.284 21.569 43.434 22.009 ;
     RECT  12.888 21.973 27.738 22.171 ;
     RECT  28.476 21.973 30.222 22.171 ;
     RECT  44.172 21.569 45.897 22.171 ;
     RECT  46.728 21.965 76.662 22.171 ;
     RECT  31.14 22.009 43.434 22.199 ;
     RECT  77.544 22.001 79.578 22.235 ;
     RECT  12.888 22.171 30.222 22.243 ;
     RECT  31.14 22.199 36.486 22.243 ;
     RECT  2.415 21.979 12.006 22.441 ;
     RECT  12.888 22.243 36.486 22.441 ;
     RECT  37.548 22.199 43.434 22.441 ;
     RECT  44.172 22.171 76.662 22.441 ;
     RECT  2.415 22.441 36.486 22.469 ;
     RECT  37.548 22.441 76.662 22.547 ;
     RECT  2.415 22.469 6.066 22.649 ;
     RECT  6.876 22.469 36.486 22.739 ;
     RECT  77.544 22.235 79.182 22.739 ;
     RECT  37.872 22.547 76.662 22.747 ;
     RECT  77.544 22.739 79.038 22.747 ;
     RECT  37.872 22.747 79.038 22.775 ;
     RECT  7.056 22.739 36.486 22.811 ;
     RECT  56.304 22.775 79.038 22.811 ;
     RECT  37.872 22.775 55.278 23.275 ;
     RECT  33.372 22.811 36.486 23.359 ;
     RECT  37.8 23.275 55.278 23.371 ;
     RECT  37.692 23.371 55.278 23.419 ;
     RECT  2.415 22.649 5.85 23.431 ;
     RECT  33.372 23.359 36.774 23.521 ;
     RECT  37.584 23.419 55.278 23.521 ;
     RECT  56.304 22.811 74.79 23.585 ;
     RECT  2.415 23.431 5.922 23.629 ;
     RECT  7.056 22.811 32.598 23.629 ;
     RECT  75.816 22.811 79.038 23.701 ;
     RECT  33.372 23.521 55.278 23.791 ;
     RECT  59.724 23.585 74.79 23.791 ;
     RECT  75.744 23.701 79.47 23.791 ;
     RECT  2.415 23.629 32.598 23.863 ;
     RECT  33.336 23.791 55.278 23.863 ;
     RECT  2.415 23.863 55.278 23.891 ;
     RECT  28.764 23.891 55.278 24.061 ;
     RECT  56.304 23.585 58.878 24.061 ;
     RECT  2.415 23.891 27.774 24.089 ;
     RECT  2.415 24.089 16.29 24.359 ;
     RECT  59.724 23.791 79.47 24.467 ;
     RECT  28.764 24.061 58.878 24.745 ;
     RECT  70.632 24.467 79.47 24.781 ;
     RECT  28.512 24.745 58.878 24.871 ;
     RECT  59.724 24.467 69.894 24.871 ;
     RECT  17.064 24.089 27.774 24.907 ;
     RECT  28.512 24.871 69.894 24.907 ;
     RECT  70.632 24.781 79.506 25.007 ;
     RECT  2.415 24.359 12.258 25.141 ;
     RECT  13.032 24.359 16.29 25.141 ;
     RECT  17.064 24.907 69.894 25.141 ;
     RECT  2.415 25.141 69.894 25.285 ;
     RECT  70.632 25.007 78.93 25.285 ;
     RECT  2.415 25.285 78.93 25.475 ;
     RECT  2.415 25.475 76.842 25.511 ;
     RECT  77.58 25.475 78.93 25.951 ;
     RECT  10.692 25.511 76.842 26.221 ;
     RECT  77.58 25.951 79.038 26.221 ;
     RECT  2.415 25.511 9.918 26.401 ;
     RECT  10.692 26.221 79.038 26.401 ;
     RECT  2.415 26.401 79.038 26.671 ;
     RECT  2.415 26.671 79.398 26.861 ;
     RECT  2.415 26.861 78.93 27.473 ;
     RECT  2.415 27.473 14.238 27.635 ;
     RECT  15.012 27.473 78.93 27.869 ;
     RECT  15.084 27.869 78.93 27.913 ;
     RECT  15.084 27.913 78.966 28.291 ;
     RECT  15.084 28.291 79.578 28.409 ;
     RECT  15.084 28.409 78.966 28.687 ;
     RECT  2.415 27.635 14.202 29.035 ;
     RECT  14.94 28.687 78.966 29.035 ;
     RECT  2.415 29.035 78.966 29.093 ;
     RECT  2.415 29.093 78.858 29.399 ;
     RECT  2.415 29.399 78.714 30.991 ;
     RECT  2.415 30.991 78.75 31.351 ;
     RECT  2.415 31.351 78.966 32.305 ;
     RECT  2.376 32.305 78.966 33.349 ;
     RECT  2.376 33.349 79.506 33.539 ;
     RECT  2.376 33.539 78.966 34.079 ;
     RECT  2.415 34.079 78.966 34.321 ;
     RECT  2.415 34.321 79.002 34.771 ;
     RECT  2.415 34.771 79.254 35.033 ;
     RECT  2.415 35.033 79.002 35.267 ;
     RECT  2.415 35.267 78.822 36.931 ;
     RECT  2.415 36.931 78.93 38.011 ;
     RECT  79.704 36.931 79.722 38.011 ;
     RECT  2.415 38.011 79.722 38.201 ;
     RECT  2.415 38.201 79.398 38.849 ;
     RECT  34.38 38.849 79.398 39.181 ;
     RECT  2.415 38.849 33.642 39.341 ;
     RECT  34.38 39.181 79.47 39.451 ;
     RECT  34.38 39.451 79.614 39.865 ;
     RECT  3.78 39.341 33.642 40.027 ;
     RECT  34.38 39.865 79.758 40.027 ;
     RECT  3.78 40.027 79.758 40.099 ;
     RECT  3.78 40.099 79.938 40.405 ;
     RECT  3.78 40.405 80.01 40.441 ;
     RECT  2.415 39.341 2.934 40.531 ;
     RECT  3.78 40.441 80.298 40.531 ;
     RECT  2.415 40.531 80.298 42.755 ;
     RECT  2.415 42.755 26.946 43.681 ;
     RECT  27.72 42.755 80.298 43.681 ;
     RECT  2.415 43.681 80.298 44.059 ;
     RECT  2.376 44.059 80.298 44.491 ;
     RECT  81.252 44.185 81.27 44.491 ;
     RECT  2.376 44.491 81.27 45.023 ;
     RECT  2.376 45.023 41.022 45.301 ;
     RECT  41.796 45.023 81.27 45.419 ;
     RECT  41.796 45.419 58.122 45.797 ;
     RECT  2.304 45.301 41.022 45.995 ;
     RECT  32.796 45.995 41.022 46.027 ;
     RECT  41.796 45.797 57.87 46.027 ;
     RECT  58.896 45.419 81.27 46.309 ;
     RECT  58.896 46.309 81.306 46.345 ;
     RECT  32.796 46.027 57.87 46.535 ;
     RECT  52.2 46.535 57.87 46.741 ;
     RECT  58.896 46.345 81.378 46.741 ;
     RECT  52.2 46.741 81.378 46.841 ;
     RECT  2.304 45.995 32.058 46.849 ;
     RECT  32.796 46.535 51.297 46.849 ;
     RECT  2.304 46.849 51.297 47.047 ;
     RECT  58.932 46.841 81.378 47.317 ;
     RECT  58.932 47.317 81.594 47.417 ;
     RECT  52.2 46.841 58.122 47.623 ;
     RECT  52.2 47.623 58.266 47.851 ;
     RECT  59.256 47.417 81.594 47.857 ;
     RECT  59.256 47.857 81.918 47.893 ;
     RECT  2.196 47.047 51.297 48.091 ;
     RECT  52.128 47.851 58.266 48.091 ;
     RECT  59.256 47.893 82.062 48.125 ;
     RECT  2.196 48.091 58.266 48.475 ;
     RECT  2.196 48.475 58.662 49.081 ;
     RECT  59.4 48.125 82.062 49.081 ;
     RECT  2.196 49.081 82.062 50.045 ;
     RECT  2.196 50.045 46.17 50.125 ;
     RECT  2.124 50.125 46.17 50.153 ;
     RECT  46.944 50.045 82.062 50.891 ;
     RECT  2.124 50.153 45.954 50.971 ;
     RECT  2.124 50.971 46.098 51.431 ;
     RECT  46.944 50.891 51.498 51.503 ;
     RECT  2.16 51.431 46.098 51.511 ;
     RECT  46.944 51.503 48.222 51.511 ;
     RECT  2.16 51.511 48.222 51.701 ;
     RECT  49.032 51.503 51.498 51.745 ;
     RECT  52.308 50.891 82.062 51.745 ;
     RECT  49.032 51.745 82.062 51.899 ;
     RECT  49.032 51.899 81.99 51.917 ;
     RECT  30.78 51.701 48.222 52.267 ;
     RECT  49.032 51.917 81.954 52.267 ;
     RECT  2.16 51.701 29.97 52.301 ;
     RECT  2.16 52.301 24.858 52.439 ;
     RECT  25.668 52.301 29.97 52.447 ;
     RECT  30.78 52.267 81.954 52.447 ;
     RECT  25.668 52.447 81.954 52.589 ;
     RECT  25.668 52.589 81.522 52.877 ;
     RECT  25.668 52.877 81.342 52.973 ;
     RECT  25.668 52.973 81.09 52.979 ;
     RECT  25.668 52.979 46.782 53.015 ;
     RECT  41.832 53.015 46.674 53.021 ;
     RECT  32.292 53.015 40.95 53.051 ;
     RECT  25.668 53.015 31.482 53.059 ;
     RECT  2.16 52.439 24.354 53.087 ;
     RECT  47.7 52.979 81.09 53.087 ;
     RECT  32.292 53.051 38.79 53.123 ;
     RECT  47.7 53.087 54.486 53.123 ;
     RECT  2.196 53.087 24.354 53.159 ;
     RECT  25.488 53.059 31.482 53.159 ;
     RECT  32.292 53.123 38.682 53.165 ;
     RECT  48.168 53.123 54.486 53.168 ;
     RECT  2.196 53.159 24.297 53.249 ;
     RECT  25.488 53.159 31.194 53.249 ;
     RECT  41.94 53.021 46.674 53.249 ;
     RECT  48.168 53.168 54.45 53.249 ;
     RECT  55.332 53.087 81.09 53.249 ;
     RECT  48.168 53.249 54.414 53.309 ;
     RECT  39.6 53.051 40.95 53.321 ;
     RECT  45.036 53.249 46.674 53.321 ;
     RECT  48.204 53.309 54.414 53.321 ;
     RECT  2.196 53.249 16.254 53.393 ;
     RECT  25.56 53.249 31.086 53.393 ;
     RECT  48.204 53.321 54.378 53.393 ;
     RECT  55.332 53.249 55.674 53.393 ;
     RECT  25.56 53.393 26.694 53.429 ;
     RECT  2.196 53.393 14.67 53.519 ;
     RECT  15.48 53.393 16.254 53.519 ;
     RECT  17.1 53.249 24.297 53.519 ;
     RECT  32.328 53.165 38.682 53.519 ;
     RECT  39.6 53.321 40.554 53.519 ;
     RECT  41.94 53.249 44.262 53.519 ;
     RECT  45.036 53.321 46.35 53.519 ;
     RECT  48.204 53.393 54.198 53.519 ;
     RECT  55.44 53.393 55.674 53.519 ;
     RECT  2.196 53.519 14.562 53.549 ;
     RECT  14.508 53.549 14.562 53.555 ;
     RECT  17.316 53.519 24.297 53.555 ;
     RECT  26.172 53.429 26.694 53.555 ;
     RECT  32.328 53.519 33.858 53.555 ;
     RECT  34.668 53.519 37.89 53.555 ;
     RECT  50.544 53.519 52.362 53.555 ;
     RECT  55.44 53.519 55.458 53.555 ;
     RECT  26.172 53.555 26.55 53.591 ;
     RECT  27.468 53.393 31.086 53.591 ;
     RECT  32.328 53.555 33.714 53.591 ;
     RECT  34.668 53.555 36.486 53.591 ;
     RECT  45.036 53.519 46.314 53.591 ;
     RECT  50.544 53.555 51.57 53.591 ;
     RECT  27.468 53.591 30.186 53.597 ;
     RECT  37.296 53.555 37.89 53.597 ;
     RECT  42.588 53.519 44.154 53.597 ;
     RECT  48.204 53.519 49.122 53.597 ;
     RECT  50.976 53.591 51.57 53.597 ;
     RECT  52.344 53.555 52.362 53.597 ;
     RECT  53.424 53.519 53.442 53.597 ;
     RECT  56.415 53.249 81.09 53.6 ;
     RECT  56.415 53.6 79.866 53.645 ;
     RECT  26.352 53.591 26.37 53.663 ;
     RECT  34.704 53.591 36.486 53.663 ;
     RECT  2.196 53.549 13.554 53.693 ;
     RECT  43.164 53.597 44.154 53.699 ;
     RECT  23.76 53.555 24.297 53.747 ;
     RECT  39.6 53.519 40.497 53.747 ;
     RECT  2.196 53.693 9.63 53.789 ;
     RECT  10.728 53.693 13.554 53.789 ;
     RECT  15.84 53.519 16.254 53.789 ;
     RECT  17.316 53.555 20.934 53.789 ;
     RECT  23.76 53.747 24.105 53.789 ;
     RECT  27.468 53.597 28.566 53.789 ;
     RECT  30.924 53.591 31.086 53.789 ;
     RECT  32.328 53.591 33.102 53.789 ;
     RECT  34.815 53.663 36.486 53.789 ;
     RECT  37.728 53.597 37.89 53.789 ;
     RECT  38.664 53.519 38.682 53.789 ;
     RECT  45.252 53.591 46.206 53.789 ;
     RECT  48.204 53.597 48.906 53.789 ;
     RECT  51.015 53.597 51.57 53.789 ;
     RECT  56.415 53.645 79.83 53.789 ;
     RECT  2.196 53.789 9.45 53.825 ;
     RECT  17.316 53.789 20.79 53.825 ;
     RECT  21.78 53.555 22.842 53.825 ;
     RECT  27.468 53.789 27.486 53.825 ;
     RECT  29.304 53.597 30.186 53.825 ;
     RECT  32.328 53.789 32.814 53.825 ;
     RECT  37.728 53.789 37.746 53.825 ;
     RECT  43.56 53.699 44.154 53.825 ;
     RECT  48.204 53.789 48.222 53.825 ;
     RECT  2.196 53.825 4.518 53.861 ;
     RECT  5.256 53.825 9.198 53.861 ;
     RECT  17.316 53.825 20.502 53.861 ;
     RECT  32.796 53.825 32.814 53.897 ;
     RECT  44.136 53.825 44.154 53.897 ;
     RECT  51.015 53.789 51.174 53.897 ;
     RECT  56.415 53.789 57.33 53.897 ;
     RECT  5.256 53.861 9.162 53.933 ;
     RECT  22.14 53.825 22.734 53.933 ;
     RECT  28.224 53.789 28.242 53.933 ;
     RECT  29.34 53.825 29.505 53.933 ;
     RECT  31.068 53.789 31.086 53.933 ;
     RECT  39.6 53.747 40.305 53.933 ;
     RECT  10.728 53.789 11.646 53.969 ;
     RECT  12.78 53.789 13.554 53.969 ;
     RECT  22.716 53.933 22.734 53.969 ;
     RECT  36.216 53.789 36.234 53.969 ;
     RECT  40.032 53.933 40.305 53.969 ;
     RECT  45.615 53.789 45.774 53.969 ;
     RECT  57.312 53.897 57.33 53.969 ;
     RECT  58.716 53.789 79.83 53.969 ;
     RECT  2.304 53.861 4.518 53.981 ;
     RECT  5.256 53.933 8.838 53.981 ;
     RECT  10.728 53.969 11.286 53.981 ;
     RECT  17.46 53.861 20.502 53.981 ;
     RECT  63.252 53.969 79.83 53.981 ;
     RECT  12.78 53.969 13.305 54.017 ;
     RECT  24.015 53.789 24.105 54.017 ;
     RECT  29.415 53.933 29.505 54.017 ;
     RECT  34.815 53.789 34.905 54.017 ;
     RECT  40.215 53.969 40.305 54.017 ;
     RECT  45.615 53.969 45.705 54.017 ;
     RECT  51.015 53.897 51.105 54.017 ;
     RECT  56.415 53.897 56.505 54.017 ;
     RECT  3.96 53.981 4.518 54.029 ;
     RECT  65.952 53.981 79.83 54.029 ;
     RECT  10.872 53.981 11.286 54.059 ;
     RECT  12.78 54.017 12.798 54.059 ;
     RECT  58.716 53.969 62.154 54.059 ;
     RECT  5.544 53.981 5.706 54.077 ;
     RECT  11.268 54.059 11.286 54.077 ;
     RECT  17.496 53.981 20.502 54.077 ;
     RECT  2.376 53.981 2.754 54.125 ;
     RECT  5.544 54.077 5.562 54.125 ;
     RECT  6.732 53.981 8.37 54.125 ;
     RECT  17.496 54.077 20.358 54.125 ;
     RECT  59.4 54.059 62.154 54.125 ;
     RECT  63.756 53.981 64.674 54.125 ;
     RECT  66.636 54.029 79.83 54.125 ;
     RECT  70.488 54.125 74.466 54.131 ;
     RECT  2.376 54.125 2.574 54.173 ;
     RECT  6.768 54.125 8.01 54.173 ;
     RECT  17.496 54.125 17.586 54.173 ;
     RECT  18.576 54.125 19.17 54.173 ;
     RECT  59.4 54.125 61.974 54.173 ;
     RECT  71.532 54.131 74.286 54.173 ;
     RECT  75.42 54.125 76.23 54.173 ;
     RECT  80.604 53.6 81.09 54.173 ;
     RECT  70.488 54.131 70.794 54.203 ;
     RECT  71.532 54.173 72.234 54.203 ;
     RECT  2.556 54.173 2.574 54.221 ;
     RECT  17.568 54.173 17.586 54.221 ;
     RECT  18.576 54.173 18.81 54.221 ;
     RECT  66.636 54.125 68.31 54.221 ;
     RECT  18.792 54.221 18.81 54.269 ;
     RECT  67.644 54.221 68.31 54.269 ;
     RECT  72.216 54.203 72.234 54.701 ;
     RECT  75.42 54.173 76.194 54.701 ;
     RECT  75.6 54.701 76.194 54.707 ;
     RECT  6.768 54.173 7.254 54.749 ;
     RECT  73.296 54.173 73.602 54.749 ;
     RECT  78.48 54.125 79.83 54.749 ;
     RECT  80.604 54.173 81.054 54.749 ;
     RECT  59.472 54.173 61.65 54.797 ;
     RECT  66.636 54.221 66.654 55.229 ;
     RECT  59.724 54.797 60.75 55.277 ;
     RECT  6.768 54.749 6.786 55.325 ;
     RECT  59.724 55.277 59.742 55.325 ;
     RECT  61.596 54.797 61.65 55.325 ;
     RECT  68.292 54.269 68.31 55.325 ;
     RECT  69.084 54.125 69.606 55.325 ;
     RECT  70.488 54.203 70.722 55.325 ;
     RECT  73.296 54.749 73.314 55.325 ;
     RECT  75.78 54.707 76.194 55.325 ;
     RECT  76.968 54.125 77.562 55.325 ;
     RECT  80.604 54.749 81.018 55.325 ;
     RECT  69.588 55.325 69.606 55.373 ;
     RECT  70.668 55.325 70.722 55.373 ;
     RECT  78.48 54.749 79.686 55.373 ;
     RECT  79.668 55.373 79.686 55.421 ;
     RECT  60.732 55.277 60.75 56.045 ;
     RECT  61.596 55.325 61.614 56.045 ;
     RECT  70.668 55.373 70.686 56.045 ;
     RECT  77.544 55.325 77.562 56.045 ;
     RECT  78.768 55.373 78.786 56.045 ;
     RECT  80.604 55.325 80.622 56.045 ;
    LAYER M4 ;
     RECT  0.06 7.92 0.133 8.328 ;
     RECT  0.133 7.92 0.181 9.144 ;
     RECT  0.181 7.392 0.229 9.144 ;
     RECT  1.477 53.952 1.573 53.976 ;
     RECT  1.573 53.568 1.765 53.976 ;
     RECT  1.669 51.504 1.861 51.528 ;
     RECT  1.765 52.992 1.861 53.976 ;
     RECT  2.197 44.352 2.293 44.376 ;
     RECT  1.861 51.504 2.293 53.976 ;
     RECT  2.293 51.36 2.329 53.976 ;
     RECT  2.329 50.544 2.341 53.976 ;
     RECT  2.293 44.352 2.365 44.904 ;
     RECT  2.365 47.904 2.401 47.928 ;
     RECT  0.229 7.296 2.408 9.144 ;
     RECT  2.365 44.064 2.408 44.904 ;
     RECT  2.401 47.904 2.408 48.504 ;
     RECT  2.341 50.544 2.408 54.168 ;
     RECT  2.408 2.148 2.427 54.168 ;
     RECT  2.427 2.148 2.512 54.216 ;
     RECT  2.512 2.418 2.585 54.216 ;
     RECT  2.533 55.728 2.629 55.752 ;
     RECT  2.629 55.296 2.677 55.752 ;
     RECT  2.585 2.418 2.704 54.12 ;
     RECT  2.704 40.464 2.765 54.12 ;
     RECT  2.677 55.296 2.867 55.992 ;
     RECT  2.704 21.504 2.909 25.752 ;
     RECT  2.909 21.504 2.915 23.928 ;
     RECT  2.867 55.296 2.915 55.32 ;
     RECT  2.765 40.464 2.963 53.976 ;
     RECT  2.704 34.752 3.059 39.336 ;
     RECT  2.704 13.68 3.251 18.024 ;
     RECT  2.909 25.248 3.347 25.752 ;
     RECT  3.059 34.8 3.413 39.336 ;
     RECT  2.704 10.8 3.521 11.448 ;
     RECT  3.251 13.68 3.521 16.536 ;
     RECT  2.915 22.752 3.521 23.928 ;
     RECT  3.413 35.184 3.683 39.336 ;
     RECT  2.704 12.528 3.697 12.552 ;
     RECT  3.521 13.68 3.697 13.704 ;
     RECT  2.963 40.464 3.773 51.336 ;
     RECT  2.963 52.32 3.781 53.976 ;
     RECT  3.521 23.376 3.809 23.928 ;
     RECT  2.704 30.336 3.841 30.648 ;
     RECT  3.683 35.184 3.845 38.664 ;
     RECT  2.915 21.504 3.913 21.768 ;
     RECT  3.841 30.336 3.913 30.84 ;
     RECT  3.773 40.464 3.917 40.968 ;
     RECT  2.704 31.968 3.923 33.096 ;
     RECT  3.913 21.12 3.973 21.768 ;
     RECT  3.521 15.36 4.019 16.536 ;
     RECT  3.769 28.704 4.061 28.728 ;
     RECT  3.923 31.968 4.097 31.992 ;
     RECT  3.973 21.12 4.163 22.248 ;
     RECT  3.845 38.64 4.169 38.664 ;
     RECT  3.917 40.704 4.241 40.968 ;
     RECT  2.704 9.12 4.261 9.672 ;
     RECT  3.521 11.328 4.381 11.448 ;
     RECT  3.697 12.528 4.381 13.704 ;
     RECT  3.251 18 4.381 18.024 ;
     RECT  3.773 41.952 4.405 51.336 ;
     RECT  3.781 52.32 4.405 54.024 ;
     RECT  2.704 6.288 4.457 8.136 ;
     RECT  4.405 41.952 4.529 54.024 ;
     RECT  4.457 7.248 4.597 8.136 ;
     RECT  4.261 9.12 4.597 9.768 ;
     RECT  4.019 15.36 4.597 16.488 ;
     RECT  4.529 41.952 4.601 53.976 ;
     RECT  4.549 34.08 4.636 34.104 ;
     RECT  4.597 14.784 4.681 16.488 ;
     RECT  4.597 7.248 4.748 9.768 ;
     RECT  4.381 11.328 4.748 13.704 ;
     RECT  4.381 18 4.777 18.984 ;
     RECT  3.809 23.568 4.813 23.928 ;
     RECT  3.845 35.184 4.813 37.464 ;
     RECT  4.748 7.248 4.835 13.704 ;
     RECT  4.813 22.752 4.993 23.928 ;
     RECT  3.347 25.248 4.993 25.272 ;
     RECT  2.704 27.312 4.993 27.336 ;
     RECT  4.993 27.024 5.029 27.336 ;
     RECT  3.913 30.096 5.029 30.84 ;
     RECT  3.923 33.072 5.065 33.096 ;
     RECT  5.065 32.976 5.105 33.096 ;
     RECT  4.813 34.32 5.123 37.464 ;
     RECT  5.029 26.688 5.125 27.336 ;
     RECT  4.681 15.456 5.137 16.488 ;
     RECT  4.777 18 5.141 19.368 ;
     RECT  4.163 21.12 5.173 21.48 ;
     RECT  4.601 41.952 5.177 50.424 ;
     RECT  4.835 7.248 5.219 9.768 ;
     RECT  5.137 15.456 5.317 16.728 ;
     RECT  5.219 7.296 5.321 9.768 ;
     RECT  5.177 42.288 5.321 50.424 ;
     RECT  5.141 18.96 5.365 19.368 ;
     RECT  5.029 30.096 5.389 31.176 ;
     RECT  5.105 32.976 5.389 33.048 ;
     RECT  4.993 22.752 5.411 25.272 ;
     RECT  5.125 26.544 5.425 27.336 ;
     RECT  5.389 30.096 5.425 31.464 ;
     RECT  5.321 9.648 5.429 9.768 ;
     RECT  5.123 35.328 5.461 37.464 ;
     RECT  4.601 51.456 5.533 53.976 ;
     RECT  4.241 40.944 5.605 40.968 ;
     RECT  5.321 42.432 5.605 50.424 ;
     RECT  5.533 51.456 5.605 54.12 ;
     RECT  5.411 22.752 5.609 23.736 ;
     RECT  4.835 11.04 5.641 13.704 ;
     RECT  5.605 40.944 5.645 41.16 ;
     RECT  5.605 42.432 5.651 54.12 ;
     RECT  5.365 18.96 5.653 19.464 ;
     RECT  5.173 20.736 5.653 21.48 ;
     RECT  5.653 18.96 5.677 21.48 ;
     RECT  5.609 22.752 5.677 22.824 ;
     RECT  5.461 35.328 5.677 37.608 ;
     RECT  5.677 18.96 5.699 22.824 ;
     RECT  5.317 15.456 5.753 17.064 ;
     RECT  5.123 34.32 5.843 34.344 ;
     RECT  5.429 9.744 5.891 9.768 ;
     RECT  5.425 26.544 6.145 28.2 ;
     RECT  5.425 29.76 6.145 31.464 ;
     RECT  5.641 11.04 6.181 14.232 ;
     RECT  6.145 26.544 6.181 31.464 ;
     RECT  5.389 32.496 6.181 33.048 ;
     RECT  6.181 9.84 6.289 14.232 ;
     RECT  4.237 5.184 6.325 5.208 ;
     RECT  5.845 6.24 6.325 6.264 ;
     RECT  5.321 7.296 6.325 8.328 ;
     RECT  6.181 26.544 6.329 33.048 ;
     RECT  5.699 18.96 6.397 20.376 ;
     RECT  6.325 4.512 6.473 5.208 ;
     RECT  5.411 25.248 6.541 25.272 ;
     RECT  6.473 4.512 6.613 4.536 ;
     RECT  5.651 42.432 6.721 54.072 ;
     RECT  5.753 15.6 6.757 17.064 ;
     RECT  6.397 18.768 6.757 20.376 ;
     RECT  6.289 9.84 6.761 14.472 ;
     RECT  6.329 32.784 6.793 33.048 ;
     RECT  5.645 41.136 6.829 41.16 ;
     RECT  6.721 42.432 6.829 54.12 ;
     RECT  6.757 55.296 6.899 55.32 ;
     RECT  6.325 6.24 6.908 8.328 ;
     RECT  6.541 24.432 6.937 25.272 ;
     RECT  5.677 35.328 6.937 38.232 ;
     RECT  6.908 6.24 6.949 8.712 ;
     RECT  6.793 32.784 6.973 33.384 ;
     RECT  6.937 34.656 6.973 38.232 ;
     RECT  6.613 3.984 6.997 4.536 ;
     RECT  6.997 3.216 7.009 4.536 ;
     RECT  6.761 13.584 7.045 14.472 ;
     RECT  6.757 15.6 7.045 20.376 ;
     RECT  6.949 6 7.153 8.712 ;
     RECT  6.761 9.84 7.153 12.312 ;
     RECT  6.973 32.784 7.153 33.624 ;
     RECT  6.973 34.656 7.153 38.472 ;
     RECT  7.153 32.784 7.189 38.472 ;
     RECT  6.329 26.544 7.225 31.464 ;
     RECT  6.829 41.136 7.225 54.12 ;
     RECT  5.699 21.456 7.261 22.824 ;
     RECT  7.045 13.584 7.549 20.376 ;
     RECT  7.261 21.456 7.549 22.872 ;
     RECT  7.225 26.256 7.549 31.464 ;
     RECT  7.189 32.784 7.549 38.76 ;
     RECT  7.225 40.32 7.571 54.744 ;
     RECT  7.009 2.88 7.693 4.536 ;
     RECT  7.153 6 7.693 12.312 ;
     RECT  7.693 2.88 7.729 12.312 ;
     RECT  7.549 13.584 7.729 22.872 ;
     RECT  7.729 2.88 7.808 22.872 ;
     RECT  6.937 23.904 7.808 25.272 ;
     RECT  7.549 26.256 7.808 38.76 ;
     RECT  7.571 40.32 7.808 54.168 ;
     RECT  7.808 2.148 7.912 54.168 ;
     RECT  7.912 2.418 8.021 54.168 ;
     RECT  8.021 2.418 8.104 54.12 ;
     RECT  8.104 33.36 8.201 39.096 ;
     RECT  8.104 26.256 8.273 28.488 ;
     RECT  8.104 30.624 8.291 32.28 ;
     RECT  8.104 11.952 8.345 16.632 ;
     RECT  8.104 40.32 8.381 54.12 ;
     RECT  8.291 30.816 8.453 32.28 ;
     RECT  7.573 55.968 8.483 55.992 ;
     RECT  8.104 29.52 8.489 29.544 ;
     RECT  8.453 30.912 8.525 32.28 ;
     RECT  8.273 26.256 8.561 28.008 ;
     RECT  8.525 30.912 8.777 31.8 ;
     RECT  8.381 40.32 8.86 53.976 ;
     RECT  8.104 5.184 9.097 10.824 ;
     RECT  8.345 11.952 9.097 16.584 ;
     RECT  9.097 5.184 9.133 16.584 ;
     RECT  8.104 18.96 9.133 23.352 ;
     RECT  8.104 24.384 9.133 25.272 ;
     RECT  8.201 33.552 9.133 39.096 ;
     RECT  8.86 40.32 9.133 53.784 ;
     RECT  9.133 33.552 9.209 53.784 ;
     RECT  9.133 18.96 9.245 25.272 ;
     RECT  8.104 17.664 9.313 17.976 ;
     RECT  9.245 18.96 9.313 20.04 ;
     RECT  9.209 37.104 9.317 53.784 ;
     RECT  8.104 2.88 9.349 2.904 ;
     RECT  9.245 21.072 9.353 25.272 ;
     RECT  9.209 33.552 9.389 35.832 ;
     RECT  9.353 21.456 9.461 25.272 ;
     RECT  8.561 26.64 9.461 28.008 ;
     RECT  9.317 37.104 9.533 41.64 ;
     RECT  9.133 5.136 9.565 16.584 ;
     RECT  9.461 23.136 9.635 25.272 ;
     RECT  9.349 2.88 9.637 3.144 ;
     RECT  9.389 33.552 9.637 34.68 ;
     RECT  8.777 30.912 9.673 31.704 ;
     RECT  9.565 4.944 9.685 16.584 ;
     RECT  9.313 17.664 9.685 20.04 ;
     RECT  9.637 2.256 9.709 3.144 ;
     RECT  9.461 26.88 9.709 28.008 ;
     RECT  9.709 2.256 9.724 3.816 ;
     RECT  9.673 30.768 9.853 31.704 ;
     RECT  9.637 32.736 9.853 34.68 ;
     RECT  9.709 26.88 9.889 28.968 ;
     RECT  9.853 30.768 9.889 34.68 ;
     RECT  9.317 43.056 10.021 53.784 ;
     RECT  9.533 37.2 10.285 41.64 ;
     RECT  9.724 3.12 10.501 3.816 ;
     RECT  9.685 4.944 10.501 20.04 ;
     RECT  9.889 26.88 10.573 34.68 ;
     RECT  9.389 35.808 10.573 35.832 ;
     RECT  10.501 3.12 10.613 20.04 ;
     RECT  10.285 37.2 10.741 42.072 ;
     RECT  10.573 26.88 10.789 35.832 ;
     RECT  10.741 37.008 10.789 42.072 ;
     RECT  10.613 17.424 10.825 20.04 ;
     RECT  9.461 21.456 10.825 22.104 ;
     RECT  9.635 23.136 10.825 25.08 ;
     RECT  10.613 3.12 10.883 16.296 ;
     RECT  10.883 3.12 10.892 3.432 ;
     RECT  10.789 26.88 10.897 42.072 ;
     RECT  10.021 43.056 10.897 54.072 ;
     RECT  10.825 21.456 10.901 25.08 ;
     RECT  10.892 3.024 10.933 3.432 ;
     RECT  10.933 2.256 10.979 3.432 ;
     RECT  10.825 17.424 11.221 20.088 ;
     RECT  10.897 26.784 11.297 54.072 ;
     RECT  11.297 29.472 11.411 53.832 ;
     RECT  11.411 29.472 11.441 53.784 ;
     RECT  11.441 42.768 11.513 53.784 ;
     RECT  10.979 2.256 11.621 2.28 ;
     RECT  11.297 26.784 11.621 28.344 ;
     RECT  11.513 44.352 11.621 53.784 ;
     RECT  11.621 44.352 11.729 53.592 ;
     RECT  11.729 44.352 11.801 53.544 ;
     RECT  11.441 29.472 11.909 41.496 ;
     RECT  10.883 4.512 11.977 16.296 ;
     RECT  11.221 17.424 11.977 20.472 ;
     RECT  11.621 26.88 11.981 28.344 ;
     RECT  11.909 30.864 11.981 41.496 ;
     RECT  10.979 3.408 12.476 3.432 ;
     RECT  11.977 4.512 12.476 20.472 ;
     RECT  12.476 3.408 12.481 20.472 ;
     RECT  11.513 42.768 12.517 43.368 ;
     RECT  11.801 44.352 12.517 53.4 ;
     RECT  12.481 3.312 12.553 20.472 ;
     RECT  10.901 21.456 12.553 24.984 ;
     RECT  12.517 42.768 12.553 53.4 ;
     RECT  12.553 3.312 12.589 24.984 ;
     RECT  11.981 27.12 12.769 28.344 ;
     RECT  11.909 29.472 12.769 29.88 ;
     RECT  11.981 30.912 12.769 41.496 ;
     RECT  12.553 42.576 12.769 53.4 ;
     RECT  12.589 3.12 12.805 24.984 ;
     RECT  12.769 30.912 12.913 53.4 ;
     RECT  12.769 27.12 12.985 29.88 ;
     RECT  12.913 30.912 12.985 53.544 ;
     RECT  12.805 3.12 13.208 25.56 ;
     RECT  12.985 27.12 13.208 53.544 ;
     RECT  13.208 2.148 13.312 54.012 ;
     RECT  13.312 2.418 13.504 53.742 ;
     RECT  13.504 21.12 13.667 53.592 ;
     RECT  13.667 26.304 13.817 53.592 ;
     RECT  13.817 26.304 13.961 49.608 ;
     RECT  13.961 26.304 14.141 29.88 ;
     RECT  13.961 30.912 14.249 49.608 ;
     RECT  13.504 2.418 14.281 20.088 ;
     RECT  14.249 41.76 14.573 49.608 ;
     RECT  14.281 2.352 14.645 20.088 ;
     RECT  13.817 50.64 14.861 53.592 ;
     RECT  14.249 30.912 15.073 40.488 ;
     RECT  14.141 26.304 15.109 28.056 ;
     RECT  14.141 29.04 15.109 29.88 ;
     RECT  15.109 26.304 15.181 29.88 ;
     RECT  15.073 30.864 15.181 40.488 ;
     RECT  15.181 26.304 15.293 40.488 ;
     RECT  14.645 2.352 15.365 19.08 ;
     RECT  15.293 34.704 15.577 40.488 ;
     RECT  14.573 41.76 15.577 49.08 ;
     RECT  15.577 34.704 15.581 49.08 ;
     RECT  14.861 50.64 15.653 50.664 ;
     RECT  15.365 2.832 15.721 19.08 ;
     RECT  14.645 20.064 15.721 20.088 ;
     RECT  14.861 52.176 15.869 53.592 ;
     RECT  15.581 34.704 15.905 48.984 ;
     RECT  15.905 34.704 16.157 40.488 ;
     RECT  13.667 21.12 16.261 25.272 ;
     RECT  15.293 26.304 16.261 33.672 ;
     RECT  15.905 41.664 16.265 48.984 ;
     RECT  15.721 2.832 16.553 20.088 ;
     RECT  16.261 21.12 16.553 33.672 ;
     RECT  16.265 44.736 16.621 48.984 ;
     RECT  16.553 27.12 16.729 33.672 ;
     RECT  16.157 34.704 16.729 38.856 ;
     RECT  16.553 3.024 16.837 20.088 ;
     RECT  16.729 27.12 16.849 38.856 ;
     RECT  15.869 52.176 16.909 52.776 ;
     RECT  16.837 3.024 17.053 20.136 ;
     RECT  16.553 21.12 17.053 26.136 ;
     RECT  17.053 3.024 17.057 26.136 ;
     RECT  16.621 44.736 17.089 49.08 ;
     RECT  17.089 44.736 17.197 49.608 ;
     RECT  16.157 40.032 17.221 40.488 ;
     RECT  16.265 41.664 17.221 43.656 ;
     RECT  16.909 52.176 17.449 53.016 ;
     RECT  17.057 3.264 17.453 26.136 ;
     RECT  17.449 52.176 17.485 53.976 ;
     RECT  17.485 52.176 17.557 54.168 ;
     RECT  16.849 34.704 17.593 38.856 ;
     RECT  17.221 40.032 17.593 43.656 ;
     RECT  17.197 44.736 17.605 50.568 ;
     RECT  17.453 3.408 17.737 26.136 ;
     RECT  16.849 27.12 17.737 33.672 ;
     RECT  17.557 52.176 17.737 54.216 ;
     RECT  17.593 34.704 17.881 43.656 ;
     RECT  17.605 44.688 17.881 50.568 ;
     RECT  17.881 44.688 17.917 50.856 ;
     RECT  17.737 51.888 17.917 54.216 ;
     RECT  17.881 34.704 17.953 43.704 ;
     RECT  17.917 44.688 17.953 54.216 ;
     RECT  17.737 3.408 18.608 33.672 ;
     RECT  17.953 34.704 18.608 54.216 ;
     RECT  18.608 2.148 18.712 54.216 ;
     RECT  18.712 2.418 18.737 54.216 ;
     RECT  18.737 2.418 18.821 54.264 ;
     RECT  18.821 2.418 18.904 54.168 ;
     RECT  18.904 42.576 19.181 54.168 ;
     RECT  19.189 55.968 19.379 55.992 ;
     RECT  18.904 2.64 19.505 41.016 ;
     RECT  19.505 2.64 19.955 33.672 ;
     RECT  19.955 2.784 20.045 24.984 ;
     RECT  20.045 2.832 20.189 24.984 ;
     RECT  19.181 42.576 20.293 54.12 ;
     RECT  20.293 42.24 20.369 54.12 ;
     RECT  20.369 42.24 20.513 54.072 ;
     RECT  20.581 56.016 20.723 56.04 ;
     RECT  20.513 42.24 20.801 53.688 ;
     RECT  20.801 42.24 21.059 53.64 ;
     RECT  21.059 42.24 21.107 53.592 ;
     RECT  19.505 34.704 21.121 41.016 ;
     RECT  21.107 42.24 21.121 43.224 ;
     RECT  21.121 34.704 21.269 43.224 ;
     RECT  19.955 26.016 21.305 33.672 ;
     RECT  21.107 44.304 21.449 53.592 ;
     RECT  20.189 2.88 21.485 24.984 ;
     RECT  21.305 30.912 21.493 33.672 ;
     RECT  21.269 34.704 21.493 41.016 ;
     RECT  21.485 21.456 21.517 24.984 ;
     RECT  21.305 26.016 21.517 29.88 ;
     RECT  21.517 21.456 21.809 29.88 ;
     RECT  21.493 30.912 21.953 41.016 ;
     RECT  21.269 42.192 22.381 43.224 ;
     RECT  21.449 44.448 22.385 53.592 ;
     RECT  22.385 44.448 22.417 49.896 ;
     RECT  21.953 32.784 22.453 41.016 ;
     RECT  22.381 42.144 22.453 43.224 ;
     RECT  21.809 21.456 22.777 24.984 ;
     RECT  21.809 25.968 22.777 29.88 ;
     RECT  22.777 21.456 22.813 29.88 ;
     RECT  21.953 30.912 22.813 31.8 ;
     RECT  22.385 50.928 22.817 53.592 ;
     RECT  21.485 2.88 22.844 20.472 ;
     RECT  22.813 21.456 22.844 31.8 ;
     RECT  22.844 2.88 22.961 31.8 ;
     RECT  22.453 32.784 23.209 43.224 ;
     RECT  22.961 30.912 23.317 31.8 ;
     RECT  23.209 32.784 23.317 43.368 ;
     RECT  22.417 44.352 23.497 49.896 ;
     RECT  22.817 50.928 23.497 52.296 ;
     RECT  23.317 30.912 23.749 43.368 ;
     RECT  23.497 44.352 23.749 52.296 ;
     RECT  22.961 2.88 24.008 29.88 ;
     RECT  23.749 30.912 24.008 52.296 ;
     RECT  22.817 53.568 24.008 53.592 ;
     RECT  24.008 2.148 24.112 54.012 ;
     RECT  24.112 2.418 24.304 53.742 ;
     RECT  24.304 40.032 24.329 48.792 ;
     RECT  24.304 2.832 24.445 38.856 ;
     RECT  24.445 26.304 24.761 38.856 ;
     RECT  24.761 26.352 24.905 38.856 ;
     RECT  24.329 40.032 25.121 43.32 ;
     RECT  24.304 49.872 25.477 50.952 ;
     RECT  24.304 51.936 25.477 52.296 ;
     RECT  24.445 2.832 25.549 25.272 ;
     RECT  25.477 49.872 25.657 52.296 ;
     RECT  24.329 44.352 25.717 48.792 ;
     RECT  25.657 49.872 25.717 53.016 ;
     RECT  25.121 42.288 25.765 43.32 ;
     RECT  25.717 44.352 25.765 53.016 ;
     RECT  24.905 30.912 25.873 38.856 ;
     RECT  25.121 40.032 25.873 41.16 ;
     RECT  24.905 26.352 25.981 29.928 ;
     RECT  25.549 2.832 25.985 25.32 ;
     RECT  25.765 42.288 26.017 53.016 ;
     RECT  25.873 30.912 26.057 41.16 ;
     RECT  25.981 26.304 26.485 29.928 ;
     RECT  26.057 30.912 26.485 40.488 ;
     RECT  26.485 26.304 26.741 40.488 ;
     RECT  26.741 26.304 26.777 33.672 ;
     RECT  26.017 42.288 26.917 53.352 ;
     RECT  25.985 4.08 26.921 25.32 ;
     RECT  26.741 34.656 26.921 40.488 ;
     RECT  25.985 2.832 27.313 3.096 ;
     RECT  26.921 4.08 27.313 25.272 ;
     RECT  27.313 2.832 27.317 25.272 ;
     RECT  26.917 42.192 27.457 53.352 ;
     RECT  27.317 2.832 27.637 20.472 ;
     RECT  27.637 2.304 27.733 20.472 ;
     RECT  27.457 42.192 27.749 53.592 ;
     RECT  27.733 2.256 27.821 20.472 ;
     RECT  27.749 42.192 28.037 48.792 ;
     RECT  26.921 34.704 28.177 40.488 ;
     RECT  27.317 21.936 28.357 25.272 ;
     RECT  26.777 26.352 28.357 33.672 ;
     RECT  28.177 34.704 28.357 40.92 ;
     RECT  28.357 21.936 28.441 41.064 ;
     RECT  28.441 21.936 28.969 40.92 ;
     RECT  28.969 21.648 29.041 40.92 ;
     RECT  27.749 50.016 29.041 53.592 ;
     RECT  28.037 42.24 29.077 48.792 ;
     RECT  29.041 49.776 29.077 53.592 ;
     RECT  27.821 2.304 29.221 20.472 ;
     RECT  29.041 21.456 29.221 40.92 ;
     RECT  29.077 42.24 29.293 53.592 ;
     RECT  29.221 2.304 29.408 40.92 ;
     RECT  29.293 42 29.408 53.592 ;
     RECT  29.408 2.148 29.512 54.012 ;
     RECT  29.512 2.418 29.704 53.742 ;
     RECT  29.704 2.64 29.837 53.592 ;
     RECT  29.837 21.936 30.035 53.592 ;
     RECT  30.035 21.984 30.197 53.592 ;
     RECT  30.197 21.984 30.809 53.112 ;
     RECT  29.837 2.64 31.045 20.664 ;
     RECT  31.045 2.64 31.133 20.856 ;
     RECT  31.133 2.64 31.493 20.664 ;
     RECT  30.809 21.984 31.997 52.92 ;
     RECT  31.997 40.272 32.053 52.92 ;
     RECT  32.053 40.272 32.357 53.784 ;
     RECT  31.493 2.832 32.425 20.664 ;
     RECT  31.997 21.984 32.429 39.288 ;
     RECT  32.429 21.984 32.537 38.952 ;
     RECT  32.357 40.272 32.573 53.352 ;
     RECT  32.425 2.832 32.677 21 ;
     RECT  32.573 40.272 33.041 49.176 ;
     RECT  33.041 40.848 33.113 49.176 ;
     RECT  32.537 21.984 33.257 38.904 ;
     RECT  32.677 2.4 33.325 21 ;
     RECT  33.257 21.984 33.325 38.808 ;
     RECT  33.113 44.4 33.541 49.176 ;
     RECT  32.573 50.16 33.541 53.352 ;
     RECT  33.325 2.4 33.653 38.808 ;
     RECT  33.541 44.4 33.757 53.352 ;
     RECT  33.757 44.4 33.797 53.544 ;
     RECT  33.797 49.776 33.827 53.544 ;
     RECT  33.797 44.4 34.117 48.744 ;
     RECT  33.113 40.848 34.297 43.176 ;
     RECT  34.117 44.352 34.297 48.744 ;
     RECT  33.653 2.832 34.369 38.808 ;
     RECT  34.369 2.832 34.808 39.24 ;
     RECT  34.297 40.848 34.808 48.744 ;
     RECT  33.827 50.112 34.808 53.544 ;
     RECT  34.808 2.148 34.912 54.012 ;
     RECT  34.912 2.418 35.104 53.742 ;
     RECT  35.104 50.112 35.165 53.544 ;
     RECT  35.104 2.832 35.381 48.984 ;
     RECT  35.381 2.832 36.389 48.936 ;
     RECT  36.389 41.616 36.569 48.936 ;
     RECT  36.389 2.832 36.641 40.536 ;
     RECT  36.641 2.976 36.857 40.536 ;
     RECT  36.569 43.296 36.969 48.936 ;
     RECT  36.857 3.264 37.073 40.536 ;
     RECT  36.969 43.296 37.249 49.032 ;
     RECT  35.165 50.112 37.249 53.112 ;
     RECT  37.249 43.296 37.285 53.112 ;
     RECT  37.073 3.408 37.469 40.536 ;
     RECT  37.469 26.352 37.609 40.536 ;
     RECT  36.569 41.616 37.609 42.072 ;
     RECT  37.285 43.296 37.757 53.592 ;
     RECT  37.609 26.352 37.825 42.072 ;
     RECT  37.757 43.296 38.113 53.304 ;
     RECT  38.113 43.248 38.117 53.304 ;
     RECT  37.825 26.352 38.149 42.12 ;
     RECT  38.117 43.248 38.149 52.968 ;
     RECT  38.149 26.352 38.441 52.968 ;
     RECT  37.469 3.408 38.545 25.272 ;
     RECT  38.441 26.352 38.545 39.24 ;
     RECT  38.441 40.32 38.693 52.968 ;
     RECT  38.693 40.32 38.765 48.984 ;
     RECT  38.765 43.296 38.837 48.984 ;
     RECT  38.693 50.112 39.589 52.968 ;
     RECT  38.545 3.408 39.661 39.24 ;
     RECT  38.765 40.32 39.661 42.072 ;
     RECT  39.661 3.408 39.841 42.072 ;
     RECT  39.841 3.36 39.877 42.072 ;
     RECT  39.589 50.112 39.877 53.064 ;
     RECT  39.877 3.36 39.913 42.216 ;
     RECT  38.837 43.344 40.093 48.984 ;
     RECT  39.877 50.112 40.093 53.352 ;
     RECT  39.913 3.36 40.129 42.264 ;
     RECT  40.129 3.36 40.208 42.312 ;
     RECT  40.093 43.344 40.208 53.352 ;
     RECT  40.208 2.148 40.312 54.012 ;
     RECT  40.312 2.418 40.504 53.742 ;
     RECT  40.504 2.928 40.889 21 ;
     RECT  40.504 22.08 41.033 52.968 ;
     RECT  40.889 2.928 41.363 20.952 ;
     RECT  41.033 22.08 41.429 40.68 ;
     RECT  41.363 2.928 41.677 20.568 ;
     RECT  41.033 41.76 41.821 52.968 ;
     RECT  41.821 41.76 42.005 53.016 ;
     RECT  42.005 43.968 42.217 53.016 ;
     RECT  41.429 39.744 42.433 40.68 ;
     RECT  42.217 43.968 42.577 53.352 ;
     RECT  41.677 2.832 42.649 20.568 ;
     RECT  42.433 39.744 42.721 40.728 ;
     RECT  42.005 41.76 42.721 42.744 ;
     RECT  42.649 2.832 42.829 20.952 ;
     RECT  41.429 22.08 42.901 38.712 ;
     RECT  42.721 39.744 42.901 42.744 ;
     RECT  42.577 43.968 43.117 53.592 ;
     RECT  43.117 43.92 43.297 53.592 ;
     RECT  42.901 22.08 43.441 42.744 ;
     RECT  43.297 43.824 43.441 53.592 ;
     RECT  43.441 22.08 43.589 53.592 ;
     RECT  42.829 2.496 44.089 20.952 ;
     RECT  43.589 22.08 44.201 52.968 ;
     RECT  44.089 2.496 44.629 21 ;
     RECT  44.629 2.496 44.828 21.096 ;
     RECT  44.201 22.08 45.205 52.824 ;
     RECT  44.828 2.304 45.608 21.096 ;
     RECT  45.205 22.08 45.608 53.064 ;
     RECT  45.608 2.148 45.712 54.012 ;
     RECT  45.712 2.418 45.904 53.742 ;
     RECT  45.904 50.112 46.433 53.064 ;
     RECT  45.904 22.512 47.149 42.552 ;
     RECT  45.904 3.6 47.221 21.144 ;
     RECT  47.149 22.512 47.221 43.128 ;
     RECT  45.904 44.16 47.269 48.984 ;
     RECT  46.433 50.112 47.269 52.824 ;
     RECT  47.269 44.16 47.293 52.824 ;
     RECT  47.221 3.6 47.363 43.128 ;
     RECT  47.363 3.6 47.473 42.888 ;
     RECT  47.293 0.576 47.617 0.6 ;
     RECT  47.473 2.88 47.941 42.888 ;
     RECT  47.293 44.112 48.013 52.824 ;
     RECT  48.013 44.112 48.157 53.112 ;
     RECT  48.157 44.112 48.193 53.304 ;
     RECT  47.941 2.736 48.413 42.888 ;
     RECT  48.413 2.736 48.476 20.52 ;
     RECT  48.413 21.504 48.517 42.888 ;
     RECT  48.517 21.504 48.553 42.936 ;
     RECT  48.553 21.504 48.733 43.08 ;
     RECT  48.193 44.112 48.733 53.592 ;
     RECT  47.617 0.096 48.755 0.6 ;
     RECT  48.476 2.256 48.797 20.52 ;
     RECT  48.733 21.504 49.061 53.592 ;
     RECT  49.061 52.464 49.133 53.592 ;
     RECT  48.755 0.576 49.235 0.6 ;
     RECT  49.061 21.504 49.313 51.48 ;
     RECT  49.313 21.6 49.385 51.48 ;
     RECT  49.385 21.744 49.493 51.48 ;
     RECT  49.733 0.096 49.817 0.12 ;
     RECT  49.493 21.792 50.101 51.48 ;
     RECT  49.133 52.464 50.101 53.352 ;
     RECT  48.797 1.728 50.149 20.52 ;
     RECT  50.149 1.152 50.285 20.52 ;
     RECT  50.285 1.728 50.461 20.52 ;
     RECT  50.101 21.792 50.813 53.4 ;
     RECT  50.461 1.728 50.929 20.616 ;
     RECT  50.813 21.648 50.929 53.4 ;
     RECT  50.929 1.728 50.965 53.4 ;
     RECT  50.965 1.728 51.008 53.592 ;
     RECT  51.008 1.728 51.112 54.012 ;
     RECT  50.869 0.144 51.251 0.168 ;
     RECT  51.112 1.728 51.304 53.742 ;
     RECT  51.304 1.728 51.365 53.592 ;
     RECT  51.365 53.328 51.833 53.592 ;
     RECT  51.365 1.728 52.661 52.248 ;
     RECT  52.661 24.864 52.733 52.248 ;
     RECT  52.661 1.728 52.949 23.736 ;
     RECT  51.833 53.568 53.453 53.592 ;
     RECT  52.949 2.496 53.525 23.736 ;
     RECT  53.525 2.592 53.629 23.736 ;
     RECT  52.733 25.008 54.205 52.248 ;
     RECT  54.205 25.008 54.493 53.16 ;
     RECT  53.629 2.592 54.677 23.832 ;
     RECT  54.493 24.96 54.677 53.16 ;
     RECT  54.677 3.696 54.853 23.832 ;
     RECT  54.677 24.96 54.853 51.96 ;
     RECT  54.853 3.696 54.995 51.96 ;
     RECT  54.677 53.04 55.429 53.16 ;
     RECT  54.677 2.64 55.717 2.664 ;
     RECT  54.995 3.696 55.717 51.384 ;
     RECT  55.717 2.64 55.964 51.384 ;
     RECT  55.964 2.256 56.293 51.384 ;
     RECT  56.293 2.256 56.408 51.48 ;
     RECT  55.429 53.04 56.408 53.352 ;
     RECT  56.408 2.148 56.512 54.012 ;
     RECT  56.512 2.418 56.704 53.742 ;
     RECT  56.704 4.224 56.867 53.352 ;
     RECT  56.867 4.224 57.017 53.064 ;
     RECT  56.704 2.736 57.197 3.048 ;
     RECT  57.017 4.512 57.593 53.064 ;
     RECT  57.593 24.624 57.629 53.064 ;
     RECT  57.629 24.816 57.635 53.064 ;
     RECT  57.635 24.816 57.665 53.016 ;
     RECT  57.665 50.064 57.845 53.016 ;
     RECT  57.197 2.736 58.057 2.904 ;
     RECT  58.057 2.592 58.453 2.904 ;
     RECT  58.453 2.592 58.705 3.48 ;
     RECT  57.593 4.512 58.705 23.64 ;
     RECT  57.665 24.816 58.709 48.984 ;
     RECT  57.845 50.112 58.777 53.016 ;
     RECT  58.705 2.592 58.853 23.64 ;
     RECT  58.709 24.912 58.961 48.984 ;
     RECT  58.961 25.056 58.997 48.984 ;
     RECT  58.853 2.592 59.033 20.376 ;
     RECT  58.997 25.152 59.173 48.984 ;
     RECT  58.777 50.112 59.173 53.304 ;
     RECT  59.033 2.688 59.249 20.376 ;
     RECT  58.853 21.36 59.357 23.64 ;
     RECT  59.173 25.152 59.389 53.304 ;
     RECT  59.389 25.152 59.461 54.168 ;
     RECT  59.461 25.152 59.465 54.792 ;
     RECT  59.465 38.688 59.713 54.792 ;
     RECT  59.249 2.784 59.933 20.376 ;
     RECT  59.933 4.656 59.965 20.376 ;
     RECT  59.933 2.784 60.365 3.48 ;
     RECT  59.713 38.688 60.371 55.32 ;
     RECT  60.365 2.784 60.437 2.808 ;
     RECT  59.357 22.08 60.577 23.64 ;
     RECT  59.465 25.152 60.757 37.176 ;
     RECT  60.371 38.688 60.833 54.888 ;
     RECT  60.577 21.696 61.009 23.688 ;
     RECT  60.757 24.96 61.045 37.176 ;
     RECT  61.045 24.96 61.297 37.56 ;
     RECT  60.833 38.688 61.297 52.008 ;
     RECT  61.009 21.696 61.333 23.88 ;
     RECT  61.297 24.96 61.333 52.008 ;
     RECT  60.833 52.992 61.523 54.888 ;
     RECT  61.477 3.6 61.585 3.624 ;
     RECT  60.677 56.016 61.621 56.04 ;
     RECT  61.621 55.296 61.625 56.04 ;
     RECT  61.585 2.832 61.693 3.624 ;
     RECT  59.965 4.656 61.693 20.568 ;
     RECT  61.693 2.832 61.808 3.672 ;
     RECT  61.693 4.656 61.808 20.664 ;
     RECT  61.333 21.696 61.808 52.008 ;
     RECT  61.523 52.992 61.808 54.168 ;
     RECT  61.625 55.296 61.811 55.32 ;
     RECT  61.808 2.148 61.912 54.168 ;
     RECT  61.912 2.418 61.985 54.168 ;
     RECT  61.985 2.418 62.104 54.12 ;
     RECT  62.104 20.64 62.165 37.608 ;
     RECT  62.104 43.104 62.165 54.12 ;
     RECT  62.104 2.688 62.237 19.368 ;
     RECT  62.165 20.832 62.273 37.608 ;
     RECT  62.237 2.688 63.137 19.272 ;
     RECT  62.165 43.104 63.205 53.592 ;
     RECT  62.104 38.592 63.299 42.12 ;
     RECT  63.137 8.976 63.421 19.272 ;
     RECT  62.273 20.832 63.425 37.464 ;
     RECT  63.137 2.688 63.443 7.848 ;
     RECT  63.425 20.832 63.461 37.224 ;
     RECT  63.299 38.592 63.493 41.928 ;
     RECT  63.205 43.104 63.745 53.976 ;
     RECT  63.421 8.976 63.749 19.512 ;
     RECT  63.749 9.12 63.929 19.512 ;
     RECT  63.929 9.12 63.965 19.368 ;
     RECT  63.443 3.12 64.001 7.848 ;
     RECT  64.001 4.512 64.037 7.848 ;
     RECT  63.461 20.832 64.069 37.176 ;
     RECT  64.001 3.12 64.181 3.48 ;
     RECT  64.037 4.656 64.249 7.848 ;
     RECT  64.069 20.496 64.259 37.176 ;
     RECT  63.493 38.208 64.429 41.928 ;
     RECT  63.745 43.104 64.429 54.12 ;
     RECT  64.429 38.208 64.469 54.12 ;
     RECT  64.181 3.12 64.721 3.144 ;
     RECT  64.469 38.544 64.729 54.12 ;
     RECT  63.965 19.2 64.793 19.368 ;
     RECT  64.729 38.544 64.793 53.976 ;
     RECT  63.965 9.12 64.829 18.168 ;
     RECT  64.793 19.2 64.865 19.32 ;
     RECT  64.865 19.2 64.937 19.272 ;
     RECT  64.937 19.2 65.045 19.224 ;
     RECT  64.259 20.496 65.117 34.248 ;
     RECT  64.249 4.656 65.189 7.992 ;
     RECT  65.189 6.816 65.219 7.992 ;
     RECT  65.219 6.912 65.473 7.992 ;
     RECT  64.829 9.12 65.473 17.976 ;
     RECT  64.259 35.232 65.473 37.176 ;
     RECT  65.473 6.912 65.513 17.976 ;
     RECT  65.117 21.504 65.513 34.248 ;
     RECT  65.473 35.232 65.545 37.56 ;
     RECT  65.513 21.504 65.657 34.152 ;
     RECT  64.793 38.64 65.941 53.976 ;
     RECT  65.545 35.232 66.013 37.608 ;
     RECT  65.941 38.64 66.013 54.024 ;
     RECT  65.657 21.504 66.053 34.104 ;
     RECT  65.189 4.656 66.193 5.352 ;
     RECT  65.117 20.496 66.476 20.52 ;
     RECT  66.053 21.504 66.476 33.384 ;
     RECT  65.513 6.912 66.625 9.144 ;
     RECT  65.513 10.128 66.769 17.976 ;
     RECT  66.193 4.656 66.805 5.544 ;
     RECT  66.625 0.144 66.841 0.168 ;
     RECT  66.757 1.728 66.86 1.752 ;
     RECT  66.805 4.128 66.901 5.544 ;
     RECT  66.841 0.096 66.908 0.168 ;
     RECT  66.86 1.728 66.908 2.28 ;
     RECT  66.769 10.128 66.913 18.552 ;
     RECT  66.625 55.2 66.995 55.224 ;
     RECT  66.476 20.496 67.093 33.384 ;
     RECT  66.013 35.232 67.129 54.024 ;
     RECT  67.093 20.4 67.165 33.384 ;
     RECT  67.129 34.896 67.165 54.168 ;
     RECT  66.908 0.096 67.208 2.28 ;
     RECT  66.901 3.408 67.208 5.544 ;
     RECT  66.625 6.672 67.208 9.144 ;
     RECT  66.913 10.128 67.208 19.08 ;
     RECT  67.165 20.4 67.208 54.168 ;
     RECT  67.208 0.096 67.212 54.168 ;
     RECT  67.212 0.096 67.385 54.216 ;
     RECT  67.385 0.144 67.504 54.216 ;
     RECT  67.504 25.536 67.525 54.216 ;
     RECT  67.504 0.144 67.619 16.056 ;
     RECT  67.619 0.192 67.673 16.056 ;
     RECT  67.525 25.536 67.673 54.264 ;
     RECT  67.673 25.536 67.709 54.12 ;
     RECT  67.504 17.04 67.781 20.424 ;
     RECT  67.709 25.536 67.781 54.024 ;
     RECT  67.781 17.04 67.859 19.272 ;
     RECT  67.673 1.152 67.889 16.056 ;
     RECT  67.889 1.728 67.925 16.056 ;
     RECT  67.925 10.992 68.033 16.056 ;
     RECT  67.859 17.232 68.069 19.272 ;
     RECT  68.033 10.992 68.435 15.816 ;
     RECT  67.925 1.728 68.501 9.96 ;
     RECT  68.501 1.728 68.537 7.944 ;
     RECT  68.501 9.36 68.645 9.96 ;
     RECT  67.781 25.536 68.681 34.104 ;
     RECT  67.781 35.232 68.713 54.024 ;
     RECT  68.681 29.28 68.785 34.104 ;
     RECT  68.713 35.232 68.785 54.12 ;
     RECT  68.069 17.376 68.821 19.272 ;
     RECT  67.781 20.4 68.821 20.424 ;
     RECT  67.504 21.6 68.821 24.264 ;
     RECT  68.537 1.728 68.897 2.424 ;
     RECT  68.897 2.112 69.041 2.424 ;
     RECT  68.785 29.28 69.077 54.12 ;
     RECT  68.537 3.408 69.221 7.944 ;
     RECT  69.221 3.408 69.293 7.464 ;
     RECT  69.077 31.248 69.293 54.12 ;
     RECT  69.293 7.392 69.329 7.464 ;
     RECT  68.645 9.936 69.361 9.96 ;
     RECT  69.041 2.208 69.443 2.424 ;
     RECT  68.435 11.376 69.473 15.816 ;
     RECT  68.821 17.376 69.493 24.264 ;
     RECT  68.281 55.296 69.577 55.32 ;
     RECT  69.473 14.448 69.581 15.816 ;
     RECT  69.473 11.376 69.587 13.416 ;
     RECT  69.443 2.256 69.721 2.424 ;
     RECT  69.293 3.408 69.721 6.312 ;
     RECT  69.493 17.376 69.829 24.36 ;
     RECT  69.329 7.44 69.869 7.464 ;
     RECT  69.829 17.376 69.913 24.552 ;
     RECT  69.361 9.936 69.977 10.392 ;
     RECT  69.581 14.496 70.045 15.816 ;
     RECT  69.913 17.376 70.045 24.36 ;
     RECT  69.721 2.256 70.085 6.312 ;
     RECT  70.085 2.832 70.157 6.312 ;
     RECT  69.293 31.296 70.201 54.12 ;
     RECT  69.977 9.936 70.265 9.96 ;
     RECT  70.157 5.28 70.499 6.312 ;
     RECT  69.077 29.28 70.513 30.216 ;
     RECT  70.201 31.296 70.513 54.024 ;
     RECT  70.499 5.28 70.54 5.592 ;
     RECT  68.681 25.536 70.585 28.008 ;
     RECT  70.513 29.28 70.585 54.024 ;
     RECT  69.587 12.24 70.589 13.416 ;
     RECT  70.045 14.496 70.589 24.36 ;
     RECT  69.577 55.296 70.657 55.368 ;
     RECT  70.585 25.536 70.769 54.024 ;
     RECT  70.657 55.296 70.835 56.04 ;
     RECT  70.589 12.384 70.841 13.416 ;
     RECT  70.157 2.832 71.021 4.152 ;
     RECT  70.769 28.512 71.021 54.024 ;
     RECT  70.835 55.296 71.123 55.368 ;
     RECT  71.021 3.552 71.125 4.152 ;
     RECT  70.769 25.536 71.173 27.336 ;
     RECT  70.589 14.496 71.219 23.928 ;
     RECT  71.125 3.552 71.273 4.536 ;
     RECT  71.219 14.496 71.273 15.24 ;
     RECT  71.021 35.232 71.341 54.024 ;
     RECT  69.937 8.736 71.345 8.76 ;
     RECT  71.273 14.496 71.345 15 ;
     RECT  71.273 3.984 71.525 4.536 ;
     RECT  71.123 55.344 71.891 55.368 ;
     RECT  71.173 25.344 72.133 27.336 ;
     RECT  71.219 16.224 72.181 23.928 ;
     RECT  72.133 25.008 72.181 27.336 ;
     RECT  71.021 28.512 72.205 34.2 ;
     RECT  71.341 35.232 72.205 54.12 ;
     RECT  70.841 13.056 72.313 13.416 ;
     RECT  71.345 14.496 72.313 14.76 ;
     RECT  71.377 6.864 72.385 6.888 ;
     RECT  72.181 16.224 72.421 27.336 ;
     RECT  72.205 28.464 72.421 34.2 ;
     RECT  72.205 35.232 72.467 54.696 ;
     RECT  71.525 3.984 72.469 4.44 ;
     RECT  72.469 3.12 72.529 4.44 ;
     RECT  72.529 2.832 72.608 4.44 ;
     RECT  70.54 5.568 72.608 5.592 ;
     RECT  72.385 6.672 72.608 6.888 ;
     RECT  72.061 8.976 72.608 9 ;
     RECT  72.313 13.056 72.608 14.76 ;
     RECT  72.421 16.224 72.608 34.2 ;
     RECT  72.467 35.232 72.608 54.168 ;
     RECT  72.469 55.968 72.659 55.992 ;
     RECT  72.608 2.148 72.712 54.168 ;
     RECT  72.712 2.352 72.904 54.168 ;
     RECT  72.904 12.384 73.073 23.928 ;
     RECT  72.904 26.112 73.109 54.168 ;
     RECT  73.109 26.112 73.181 33.384 ;
     RECT  72.904 2.352 73.433 2.856 ;
     RECT  73.181 26.304 73.433 33.384 ;
     RECT  72.904 10.416 73.541 11.4 ;
     RECT  73.433 26.304 73.541 28.008 ;
     RECT  73.109 34.704 73.573 54.168 ;
     RECT  73.285 55.296 73.573 55.32 ;
     RECT  72.904 5.472 73.577 5.496 ;
     RECT  73.073 19.92 73.613 23.928 ;
     RECT  73.613 19.92 73.685 22.872 ;
     RECT  73.541 26.304 73.721 26.952 ;
     RECT  73.541 27.984 73.721 28.008 ;
     RECT  73.721 26.304 73.829 26.904 ;
     RECT  72.904 6.48 73.933 7.032 ;
     RECT  72.904 8.976 73.933 9.096 ;
     RECT  73.541 10.8 73.933 11.4 ;
     RECT  73.073 12.384 73.933 18.744 ;
     RECT  73.933 8.976 73.973 9.72 ;
     RECT  73.613 23.904 74.041 23.928 ;
     RECT  73.933 25.2 74.041 25.32 ;
     RECT  74.041 23.904 74.045 25.32 ;
     RECT  73.933 6.48 74.077 7.704 ;
     RECT  73.933 10.8 74.185 18.744 ;
     RECT  74.185 10.8 74.189 18.84 ;
     RECT  73.573 34.704 74.195 55.32 ;
     RECT  74.045 24.048 74.221 25.32 ;
     RECT  73.829 26.304 74.221 26.328 ;
     RECT  73.433 28.992 74.261 33.384 ;
     RECT  74.261 31.104 74.293 33.384 ;
     RECT  74.195 34.704 74.293 54.168 ;
     RECT  74.189 10.8 74.297 17.064 ;
     RECT  74.189 18.432 74.369 18.84 ;
     RECT  74.195 55.296 74.387 55.32 ;
     RECT  72.904 4.416 74.401 4.44 ;
     RECT  74.293 31.104 74.405 54.168 ;
     RECT  74.369 18.816 74.513 18.84 ;
     RECT  74.077 6.48 74.585 7.8 ;
     RECT  74.401 3.888 74.617 4.44 ;
     RECT  74.585 6.528 74.617 7.8 ;
     RECT  74.297 10.8 74.621 14.76 ;
     RECT  74.297 15.888 74.765 17.064 ;
     RECT  73.433 2.352 74.821 2.808 ;
     RECT  74.617 3.888 74.821 4.584 ;
     RECT  73.973 9.696 74.869 9.72 ;
     RECT  74.621 10.8 74.869 14.664 ;
     RECT  73.685 20.064 74.873 22.776 ;
     RECT  74.261 28.992 74.905 29.976 ;
     RECT  74.821 2.352 74.909 4.584 ;
     RECT  74.909 4.416 74.915 4.584 ;
     RECT  74.617 6.528 75.013 8.184 ;
     RECT  74.221 24.048 75.096 26.328 ;
     RECT  74.869 9.696 75.305 14.664 ;
     RECT  74.909 2.352 75.377 2.808 ;
     RECT  74.905 28.512 75.409 29.976 ;
     RECT  74.405 31.104 75.409 31.8 ;
     RECT  74.405 32.88 75.409 54.168 ;
     RECT  74.765 15.888 75.493 16.44 ;
     RECT  74.873 20.064 75.5 22.488 ;
     RECT  75.409 28.512 75.589 31.8 ;
     RECT  75.409 32.88 75.589 54.696 ;
     RECT  75.013 6.528 75.637 8.52 ;
     RECT  75.637 5.616 75.724 8.52 ;
     RECT  75.305 9.696 75.729 14.136 ;
     RECT  74.915 4.56 75.733 4.584 ;
     RECT  75.096 24.048 75.733 26.52 ;
     RECT  75.589 28.512 75.769 54.696 ;
     RECT  75.769 28.512 75.773 55.32 ;
     RECT  75.733 23.712 75.841 26.52 ;
     RECT  75.733 4.56 75.845 4.92 ;
     RECT  75.724 6.528 76.061 8.52 ;
     RECT  75.773 32.88 76.133 55.32 ;
     RECT  76.133 32.88 76.169 33.384 ;
     RECT  75.729 10.272 76.273 14.136 ;
     RECT  75.541 18 76.309 18.024 ;
     RECT  75.377 2.352 76.313 2.376 ;
     RECT  76.061 6.768 76.313 8.52 ;
     RECT  76.309 17.856 76.345 18.024 ;
     RECT  75.845 4.656 76.349 4.92 ;
     RECT  76.133 34.704 76.349 55.32 ;
     RECT  76.273 10.272 76.381 14.712 ;
     RECT  75.493 15.792 76.381 16.44 ;
     RECT  75.841 23.616 76.385 26.52 ;
     RECT  75.5 19.632 76.453 22.488 ;
     RECT  75.773 28.512 76.453 31.8 ;
     RECT  76.313 6.768 76.457 8.088 ;
     RECT  76.453 19.392 76.489 22.488 ;
     RECT  76.385 23.616 76.489 24.168 ;
     RECT  76.453 28.464 76.489 31.8 ;
     RECT  76.349 34.992 76.595 55.32 ;
     RECT  76.381 10.272 76.597 16.44 ;
     RECT  76.345 17.856 76.597 18.216 ;
     RECT  76.597 10.272 76.637 18.216 ;
     RECT  76.385 25.2 76.705 26.52 ;
     RECT  76.637 10.272 76.709 12.936 ;
     RECT  76.489 19.392 76.709 24.168 ;
     RECT  76.637 18.192 76.741 18.216 ;
     RECT  76.709 19.392 76.741 23.928 ;
     RECT  76.705 25.2 76.813 26.76 ;
     RECT  76.489 27.888 76.813 31.8 ;
     RECT  76.457 6.768 76.817 8.04 ;
     RECT  76.813 25.2 76.853 31.8 ;
     RECT  76.817 6.768 76.889 7.896 ;
     RECT  76.637 14.208 76.925 17.16 ;
     RECT  76.925 14.208 76.931 14.856 ;
     RECT  76.741 18.192 76.961 23.928 ;
     RECT  76.169 32.88 77.029 32.904 ;
     RECT  76.961 18.192 77.033 23.88 ;
     RECT  76.853 26.496 77.065 31.8 ;
     RECT  77.029 32.784 77.065 32.904 ;
     RECT  76.933 4.224 77.173 4.248 ;
     RECT  76.933 5.472 77.173 5.496 ;
     RECT  77.173 5.472 77.209 5.736 ;
     RECT  76.889 6.768 77.209 7.464 ;
     RECT  76.595 34.992 77.213 54.216 ;
     RECT  77.213 34.992 77.267 54.168 ;
     RECT  76.595 55.296 77.533 55.32 ;
     RECT  77.533 55.296 77.555 56.04 ;
     RECT  77.555 55.344 77.651 56.04 ;
     RECT  76.709 10.272 77.756 12.84 ;
     RECT  77.065 26.496 77.893 32.904 ;
     RECT  77.173 3.408 78.008 4.248 ;
     RECT  77.209 5.472 78.008 7.464 ;
     RECT  77.756 9.552 78.008 12.84 ;
     RECT  76.931 14.208 78.008 14.232 ;
     RECT  76.925 16.32 78.008 17.16 ;
     RECT  77.033 18.192 78.008 23.736 ;
     RECT  76.853 25.2 78.008 25.224 ;
     RECT  77.893 26.496 78.008 33.672 ;
     RECT  77.267 34.992 78.008 54.12 ;
     RECT  78.008 2.148 78.112 54.12 ;
     RECT  78.112 2.418 78.304 54.12 ;
     RECT  78.304 11.472 78.419 13.32 ;
     RECT  78.304 15.84 78.419 18.168 ;
     RECT  78.304 31.68 78.419 36.936 ;
     RECT  78.304 19.584 78.437 19.608 ;
     RECT  78.304 38.4 78.473 54.12 ;
     RECT  78.419 31.68 78.515 33.816 ;
     RECT  78.304 14.688 78.545 14.712 ;
     RECT  78.304 27.072 78.545 29.352 ;
     RECT  78.304 10.176 78.581 10.392 ;
     RECT  78.545 27.36 78.581 29.064 ;
     RECT  78.515 31.68 78.581 32.52 ;
     RECT  77.651 55.344 78.613 55.992 ;
     RECT  78.581 10.176 78.617 10.2 ;
     RECT  78.419 11.472 78.617 12.504 ;
     RECT  78.419 15.84 78.617 17.544 ;
     RECT  78.581 28.224 78.617 29.064 ;
     RECT  78.515 33.792 78.617 33.816 ;
     RECT  78.419 35.28 78.617 36.936 ;
     RECT  78.617 12 78.689 12.504 ;
     RECT  78.617 15.84 78.689 16.776 ;
     RECT  78.304 25.2 78.689 25.368 ;
     RECT  78.617 28.992 78.689 29.064 ;
     RECT  78.581 31.728 78.689 32.52 ;
     RECT  78.617 35.28 78.689 35.304 ;
     RECT  78.689 15.84 78.725 15.864 ;
     RECT  78.473 38.688 78.725 54.12 ;
     RECT  78.613 55.296 78.757 55.992 ;
     RECT  78.689 29.04 78.761 29.064 ;
     RECT  78.689 25.344 78.797 25.368 ;
     RECT  78.617 36.528 78.797 36.936 ;
     RECT  78.797 36.528 78.833 36.552 ;
     RECT  78.689 12.48 78.941 12.504 ;
     RECT  78.304 6.864 78.977 6.984 ;
     RECT  78.725 38.928 78.977 54.12 ;
     RECT  78.977 38.928 79.036 43.08 ;
     RECT  79.036 39.312 79.049 43.08 ;
     RECT  79.049 39.312 79.057 42.792 ;
     RECT  78.977 44.064 79.193 54.12 ;
     RECT  78.304 4.368 79.265 4.392 ;
     RECT  78.977 6.864 79.265 6.888 ;
     RECT  79.193 44.16 79.283 54.12 ;
     RECT  79.057 39.36 79.301 42.792 ;
     RECT  79.283 44.736 79.381 54.12 ;
     RECT  79.301 41.088 79.445 42.792 ;
     RECT  78.757 55.296 79.571 56.04 ;
     RECT  79.571 55.296 79.585 55.416 ;
     RECT  79.381 44.736 79.612 53.64 ;
     RECT  79.301 39.36 79.619 39.912 ;
     RECT  79.445 42 79.697 42.792 ;
     RECT  79.612 45.024 79.715 53.64 ;
     RECT  79.715 45.168 79.763 53.64 ;
     RECT  79.763 45.168 79.769 45.192 ;
     RECT  79.763 46.176 79.769 53.64 ;
     RECT  79.697 42.576 79.805 42.792 ;
     RECT  79.769 46.176 79.805 46.776 ;
     RECT  79.769 47.76 79.805 53.64 ;
     RECT  79.619 39.36 79.811 39.384 ;
     RECT  79.805 46.176 79.849 46.248 ;
     RECT  79.805 48.048 80.243 53.64 ;
     RECT  79.585 54.672 80.549 55.416 ;
     RECT  80.549 54.672 80.633 56.04 ;
     RECT  80.633 54.672 80.723 55.416 ;
     RECT  79.849 46.224 80.741 46.248 ;
     RECT  80.243 48.144 80.915 53.64 ;
     RECT  80.723 54.672 80.924 55.32 ;
     RECT  80.924 54.144 81.107 55.32 ;
     RECT  81.107 54.144 81.203 54.744 ;
     RECT  81.203 54.144 81.299 54.168 ;
     RECT  80.915 48.144 81.893 52.968 ;
     RECT  81.893 48.336 82.044 52.968 ;
    LAYER M5 ;
     RECT  66.768 0.016 68.808 1.763 ;
     RECT  48.336 0.016 51.336 1.859 ;
     RECT  2.4 2.137 2.52 2.151 ;
     RECT  7.8 2.137 7.92 2.151 ;
     RECT  13.2 2.137 13.32 2.151 ;
     RECT  18.6 2.137 18.72 2.151 ;
     RECT  24 2.137 24.12 2.151 ;
     RECT  29.4 2.137 29.52 2.151 ;
     RECT  34.8 2.137 34.92 2.151 ;
     RECT  40.2 2.137 40.32 2.151 ;
     RECT  45.6 2.137 45.72 2.151 ;
     RECT  56.4 2.137 56.52 2.151 ;
     RECT  61.8 2.137 61.92 2.151 ;
     RECT  72.6 2.137 72.72 2.151 ;
     RECT  78 2.137 78.12 2.151 ;
     RECT  66.912 1.763 68.808 2.197 ;
     RECT  56.4 2.151 56.712 2.245 ;
     RECT  45.6 2.151 45.912 2.293 ;
     RECT  66.912 2.197 69.432 2.435 ;
     RECT  44.88 2.293 45.912 2.725 ;
     RECT  24 2.151 24.312 2.821 ;
     RECT  34.8 2.151 35.112 2.821 ;
     RECT  27.744 2.245 27.768 2.867 ;
     RECT  48.336 1.859 51.312 2.915 ;
     RECT  10.944 2.245 10.968 3.059 ;
     RECT  72.6 2.151 72.912 3.109 ;
     RECT  9.648 2.245 9.672 3.155 ;
     RECT  7.8 2.151 8.112 3.205 ;
     RECT  29.4 2.151 29.712 3.205 ;
     RECT  19.92 2.629 19.944 3.397 ;
     RECT  66.912 2.435 68.424 3.397 ;
     RECT  69.408 2.435 69.432 3.397 ;
     RECT  19.92 3.397 20.088 3.443 ;
     RECT  56.016 2.245 56.712 3.443 ;
     RECT  74.832 2.341 74.856 3.587 ;
     RECT  34.176 2.821 35.112 3.589 ;
     RECT  36.336 3.397 36.36 3.589 ;
     RECT  13.2 2.151 13.512 3.733 ;
     RECT  43.92 2.725 45.912 3.827 ;
     RECT  34.176 3.589 36.36 3.875 ;
     RECT  63.408 2.677 63.432 3.875 ;
     RECT  40.2 2.151 40.512 3.877 ;
     RECT  29.4 3.205 30.264 3.923 ;
     RECT  34.8 3.875 36.36 3.925 ;
     RECT  48.24 3.301 48.264 3.925 ;
     RECT  12.528 3.733 13.512 3.973 ;
     RECT  10.848 3.397 10.872 4.019 ;
     RECT  54.72 3.733 54.744 4.019 ;
     RECT  72.48 3.109 72.912 4.019 ;
     RECT  66.912 3.397 69.432 4.067 ;
     RECT  66.912 4.067 68.28 4.115 ;
     RECT  66.912 4.115 67.704 4.117 ;
     RECT  12.528 3.973 14.232 4.259 ;
     RECT  34.8 3.925 37.08 4.355 ;
     RECT  20.064 3.443 20.088 4.499 ;
     RECT  7.008 3.205 8.112 4.501 ;
     RECT  58.848 2.581 58.872 4.501 ;
     RECT  39.888 3.877 40.512 4.691 ;
     RECT  24 2.821 24.984 4.693 ;
     RECT  23.616 4.693 24.984 4.837 ;
     RECT  26.256 4.453 26.28 4.837 ;
     RECT  44.88 3.827 45.912 4.933 ;
     RECT  69.312 4.067 69.432 5.171 ;
     RECT  23.616 4.837 26.28 5.219 ;
     RECT  48.048 3.925 48.264 5.219 ;
     RECT  69.312 5.171 69.336 5.219 ;
     RECT  71.136 4.501 71.16 5.269 ;
     RECT  13.2 4.259 14.232 5.315 ;
     RECT  61.8 2.151 62.112 5.365 ;
     RECT  22.8 5.221 22.824 5.411 ;
     RECT  44.784 4.933 45.912 5.461 ;
     RECT  74.88 4.405 74.904 5.605 ;
     RECT  38.64 3.589 38.664 5.653 ;
     RECT  40.2 4.691 40.512 5.653 ;
     RECT  29.4 3.923 29.712 5.701 ;
     RECT  17.376 3.397 17.4 5.747 ;
     RECT  24 5.219 25.512 5.747 ;
     RECT  34.8 4.355 35.112 5.749 ;
     RECT  18.6 2.151 18.912 5.845 ;
     RECT  36.336 4.355 37.08 5.891 ;
     RECT  56.16 3.443 56.712 5.987 ;
     RECT  49.776 2.915 51.312 6.037 ;
     RECT  44.784 5.461 46.2 6.085 ;
     RECT  19.92 5.077 19.944 6.227 ;
     RECT  29.28 5.701 29.712 6.227 ;
     RECT  21.168 5.845 21.192 6.229 ;
     RECT  17.424 5.845 18.912 6.323 ;
     RECT  70.464 5.269 71.16 6.323 ;
     RECT  13.2 5.315 13.512 6.373 ;
     RECT  56.4 5.987 56.712 6.421 ;
     RECT  72.6 4.019 72.912 6.517 ;
     RECT  74.88 5.605 75.672 6.563 ;
     RECT  34.704 5.749 35.112 6.613 ;
     RECT  24 5.747 24.312 6.805 ;
     RECT  23.616 6.805 24.312 6.853 ;
     RECT  44.784 6.085 46.584 6.853 ;
     RECT  48.24 5.219 48.264 6.853 ;
     RECT  61.008 5.365 62.112 6.853 ;
     RECT  25.488 5.747 25.512 6.899 ;
     RECT  49.776 6.037 52.104 6.995 ;
     RECT  63.264 6.853 63.288 6.995 ;
     RECT  36.336 5.891 36.936 6.997 ;
     RECT  22.704 6.853 24.312 7.043 ;
     RECT  31.248 5.461 31.272 7.043 ;
     RECT  72.6 6.517 73.512 7.043 ;
     RECT  76.944 4.213 76.968 7.043 ;
     RECT  61.008 6.853 62.232 7.139 ;
     RECT  13.2 6.373 13.848 7.189 ;
     RECT  44.784 6.853 48.264 7.189 ;
     RECT  49.776 6.995 51.312 7.189 ;
     RECT  54.96 5.029 54.984 7.189 ;
     RECT  56.4 6.421 56.808 7.189 ;
     RECT  44.784 7.189 51.312 7.235 ;
     RECT  2.4 2.151 2.712 7.237 ;
     RECT  5.856 6.229 5.88 7.237 ;
     RECT  58.848 4.501 59.256 7.237 ;
     RECT  36.144 6.997 36.936 7.283 ;
     RECT  74.88 6.563 75.384 7.283 ;
     RECT  21.168 6.229 21.624 7.285 ;
     RECT  47.856 7.235 51.312 7.331 ;
     RECT  13.104 7.189 13.848 7.379 ;
     RECT  0.24 7.285 0.264 7.381 ;
     RECT  54.96 7.189 56.808 7.381 ;
     RECT  38.64 5.653 40.512 7.427 ;
     RECT  65.184 6.805 65.208 7.475 ;
     RECT  54.96 7.381 57.624 7.571 ;
     RECT  41.616 5.701 41.64 7.619 ;
     RECT  53.808 4.453 53.832 7.621 ;
     RECT  66.816 4.117 67.704 7.669 ;
     RECT  9.216 6.229 9.24 7.811 ;
     RECT  44.784 7.235 46.584 7.811 ;
     RECT  61.008 7.139 62.112 7.955 ;
     RECT  23.616 7.043 24.312 7.957 ;
     RECT  19.92 7.333 19.944 8.003 ;
     RECT  49.584 7.331 51.312 8.003 ;
     RECT  0.192 7.381 0.264 8.005 ;
     RECT  40.2 7.427 40.512 8.005 ;
     RECT  20.928 7.285 21.624 8.147 ;
     RECT  75.216 7.283 75.384 8.195 ;
     RECT  0.144 8.005 0.264 8.243 ;
     RECT  40.2 8.005 40.728 8.243 ;
     RECT  38.64 7.427 38.76 8.293 ;
     RECT  38.352 8.293 38.76 8.339 ;
     RECT  17.424 6.323 17.448 8.437 ;
     RECT  18.6 6.323 18.912 8.437 ;
     RECT  29.4 6.227 29.712 8.437 ;
     RECT  49.776 8.003 51.312 8.437 ;
     RECT  52.896 7.621 53.832 8.437 ;
     RECT  49.776 8.437 53.832 8.725 ;
     RECT  54.96 7.571 56.808 8.771 ;
     RECT  23.616 7.957 24.456 8.821 ;
     RECT  55.824 8.771 56.808 8.821 ;
     RECT  10.8 7.381 10.824 8.867 ;
     RECT  49.776 8.725 53.976 8.867 ;
     RECT  34.416 6.613 35.112 9.061 ;
     RECT  36.144 7.283 36.888 9.061 ;
     RECT  58.704 7.237 59.256 9.061 ;
     RECT  55.824 8.821 57.288 9.107 ;
     RECT  0.144 8.243 0.168 9.155 ;
     RECT  23.568 8.821 24.456 9.155 ;
     RECT  58.704 9.061 60.072 9.155 ;
     RECT  15.744 8.533 15.768 9.203 ;
     RECT  66.816 7.669 67.8 9.349 ;
     RECT  13.104 7.379 13.656 9.397 ;
     RECT  28.56 8.437 29.712 9.397 ;
     RECT  17.424 8.437 18.912 9.445 ;
     RECT  47.856 7.331 48.264 9.491 ;
     RECT  28.56 9.397 30.456 9.539 ;
     RECT  78 2.151 78.312 9.541 ;
     RECT  17.424 9.445 19.272 9.587 ;
     RECT  5.184 7.237 5.88 9.637 ;
     RECT  59.232 9.155 60.072 9.683 ;
     RECT  75.216 8.195 75.24 9.685 ;
     RECT  4.272 9.637 5.88 9.779 ;
     RECT  44.784 7.811 46.2 9.781 ;
     RECT  20.928 8.147 21.192 9.827 ;
     RECT  23.568 9.155 24.312 9.829 ;
     RECT  44.592 9.781 46.2 9.923 ;
     RECT  55.824 9.107 56.712 10.021 ;
     RECT  29.4 9.539 30.456 10.115 ;
     RECT  12.336 9.397 13.656 10.213 ;
     RECT  23.52 9.829 24.312 10.213 ;
     RECT  12.336 10.213 13.752 10.259 ;
     RECT  15.936 9.541 15.96 10.259 ;
     RECT  34.416 9.061 36.888 10.307 ;
     RECT  75.216 9.685 75.672 10.307 ;
     RECT  20.928 9.827 20.952 10.357 ;
     RECT  43.344 8.821 43.368 10.595 ;
     RECT  33.264 9.925 33.288 10.597 ;
     RECT  34.416 10.307 35.112 10.597 ;
     RECT  32.208 9.925 32.232 10.643 ;
     RECT  40.2 8.243 40.512 10.693 ;
     RECT  17.424 9.587 17.448 10.789 ;
     RECT  18.6 9.587 19.272 10.789 ;
     RECT  38.352 8.339 38.664 10.789 ;
     RECT  64.368 7.957 64.392 10.835 ;
     RECT  59.232 9.683 59.976 10.883 ;
     RECT  25.536 7.237 25.56 10.885 ;
     RECT  29.4 10.115 29.712 10.885 ;
     RECT  53.808 8.867 53.976 10.885 ;
     RECT  55.344 10.021 56.712 10.885 ;
     RECT  66.816 9.349 68.424 10.885 ;
     RECT  17.424 10.789 19.272 10.933 ;
     RECT  40.08 10.693 40.512 11.029 ;
     RECT  41.568 9.637 41.592 11.029 ;
     RECT  4.272 9.779 5.736 11.075 ;
     RECT  16.944 10.933 19.272 11.075 ;
     RECT  33.264 10.597 35.112 11.075 ;
     RECT  40.08 11.029 41.592 11.075 ;
     RECT  48.24 9.491 48.264 11.077 ;
     RECT  49.776 8.867 52.152 11.077 ;
     RECT  48.24 11.077 52.152 11.219 ;
     RECT  53.808 10.885 56.712 11.219 ;
     RECT  6.96 4.501 8.112 11.317 ;
     RECT  49.776 11.219 52.152 11.317 ;
     RECT  53.808 11.219 53.976 11.317 ;
     RECT  17.424 11.075 19.272 11.365 ;
     RECT  28.416 10.885 29.712 11.365 ;
     RECT  40.08 11.075 41.208 11.365 ;
     RECT  66.384 10.885 68.424 11.411 ;
     RECT  17.424 11.365 19.368 11.459 ;
     RECT  49.776 11.317 53.976 11.459 ;
     RECT  69.552 11.365 69.576 11.461 ;
     RECT  77.808 9.541 78.312 11.509 ;
     RECT  77.808 11.509 78.408 11.555 ;
     RECT  38.064 10.789 38.664 11.603 ;
     RECT  36.144 10.307 36.888 11.605 ;
     RECT  66.384 11.411 67.704 11.699 ;
     RECT  48.24 11.219 48.744 11.749 ;
     RECT  36.144 11.605 37.08 11.795 ;
     RECT  20.88 10.357 20.952 11.845 ;
     RECT  39.744 11.365 41.208 11.891 ;
     RECT  13.2 10.259 13.752 11.893 ;
     RECT  6.384 11.317 8.112 11.941 ;
     RECT  61.8 7.955 62.112 11.941 ;
     RECT  17.424 11.459 17.448 11.987 ;
     RECT  27.888 11.365 29.712 11.987 ;
     RECT  48.048 11.749 48.744 11.987 ;
     RECT  66.816 11.699 67.704 11.987 ;
     RECT  49.776 11.459 53.832 12.035 ;
     RECT  23.472 10.213 24.312 12.037 ;
     RECT  25.296 10.885 25.56 12.037 ;
     RECT  33.648 11.075 35.112 12.083 ;
     RECT  55.344 11.219 56.712 12.133 ;
     RECT  12.528 11.893 13.752 12.179 ;
     RECT  22.176 11.269 22.2 12.227 ;
     RECT  23.472 12.037 25.56 12.229 ;
     RECT  55.344 12.133 56.808 12.275 ;
     RECT  68.832 11.461 69.576 12.323 ;
     RECT  6.384 11.941 8.28 12.371 ;
     RECT  48.24 11.987 48.744 12.421 ;
     RECT  49.776 12.035 52.488 12.421 ;
     RECT  27.888 11.987 28.104 12.469 ;
     RECT  23.184 12.229 25.56 12.515 ;
     RECT  33.696 12.083 35.112 12.517 ;
     RECT  36.144 11.795 36.456 12.517 ;
     RECT  20.88 11.845 21.144 12.563 ;
     RECT  40.2 11.891 41.208 12.563 ;
     RECT  66.96 11.987 67.704 12.563 ;
     RECT  45.408 9.923 46.2 12.565 ;
     RECT  23.184 12.515 24.84 12.611 ;
     RECT  18.6 11.459 19.368 12.755 ;
     RECT  33.696 12.517 36.456 12.755 ;
     RECT  7.104 12.371 8.28 12.757 ;
     RECT  9.36 8.341 9.384 12.757 ;
     RECT  27.408 12.469 28.104 12.757 ;
     RECT  61.68 11.941 62.112 12.757 ;
     RECT  38.304 11.603 38.664 12.805 ;
     RECT  53.808 12.035 53.832 12.805 ;
     RECT  55.344 12.275 56.712 12.805 ;
     RECT  61.68 12.757 62.376 12.899 ;
     RECT  53.808 12.805 56.712 12.947 ;
     RECT  40.2 12.563 40.512 12.997 ;
     RECT  4.272 11.075 5.304 13.043 ;
     RECT  59.328 12.085 59.352 13.045 ;
     RECT  75.504 11.413 75.528 13.045 ;
     RECT  45.12 12.565 46.2 13.139 ;
     RECT  48.24 12.421 52.488 13.141 ;
     RECT  53.808 12.947 53.832 13.141 ;
     RECT  45.12 13.139 46.056 13.237 ;
     RECT  32.304 12.037 32.328 13.283 ;
     RECT  41.856 13.141 41.88 13.283 ;
     RECT  69.552 12.323 69.576 13.283 ;
     RECT  4.56 13.043 5.304 13.331 ;
     RECT  34.128 12.755 36.456 13.331 ;
     RECT  61.68 12.899 62.112 13.331 ;
     RECT  78 11.555 78.408 13.331 ;
     RECT  5.28 13.331 5.304 13.333 ;
     RECT  59.328 13.045 59.784 13.333 ;
     RECT  59.328 13.333 60.36 13.379 ;
     RECT  40.032 12.997 40.512 13.429 ;
     RECT  43.296 13.333 43.32 13.475 ;
     RECT  16.56 12.517 16.584 13.523 ;
     RECT  26.736 12.757 28.104 13.525 ;
     RECT  48.24 13.141 53.832 13.571 ;
     RECT  39.984 13.429 40.512 13.573 ;
     RECT  26.496 13.525 28.104 13.667 ;
     RECT  39.984 13.573 41.16 13.667 ;
     RECT  12.528 12.179 13.656 13.715 ;
     RECT  40.032 13.667 41.16 13.763 ;
     RECT  44.832 13.237 46.056 13.763 ;
     RECT  59.568 13.379 60.36 13.763 ;
     RECT  65.808 11.941 65.832 13.765 ;
     RECT  67.2 12.563 67.704 13.765 ;
     RECT  40.08 13.763 41.16 13.907 ;
     RECT  23.52 12.611 24.648 13.957 ;
     RECT  59.568 13.763 60.024 14.099 ;
     RECT  26.736 13.667 28.104 14.147 ;
     RECT  7.104 12.757 9.384 14.197 ;
     RECT  29.28 11.987 29.712 14.197 ;
     RECT  75.504 13.045 76.488 14.197 ;
     RECT  5.28 13.333 6.024 14.243 ;
     RECT  38.304 12.805 39 14.339 ;
     RECT  20.88 12.563 20.952 14.341 ;
     RECT  20.544 14.341 20.952 14.387 ;
     RECT  61.8 13.331 62.112 14.389 ;
     RECT  11.472 13.333 11.496 14.435 ;
     RECT  15.936 14.245 15.96 14.437 ;
     RECT  7.104 14.197 9.624 14.485 ;
     RECT  48.24 13.571 53.592 14.579 ;
     RECT  30.816 12.949 30.84 14.627 ;
     RECT  44.976 13.763 46.056 14.627 ;
     RECT  61.8 14.389 62.424 14.677 ;
     RECT  71.136 6.323 71.16 14.677 ;
     RECT  12.912 13.715 13.656 14.725 ;
     RECT  48.24 14.579 52.488 14.725 ;
     RECT  7.104 14.485 10.104 14.771 ;
     RECT  5.28 14.243 5.304 14.773 ;
     RECT  55.344 12.947 56.712 14.773 ;
     RECT  15.504 14.437 15.96 14.867 ;
     RECT  27.408 14.147 28.104 14.867 ;
     RECT  29.184 14.197 29.712 14.867 ;
     RECT  68.928 13.957 68.952 14.867 ;
     RECT  75.504 14.197 76.92 14.867 ;
     RECT  55.296 14.773 56.712 15.109 ;
     RECT  44.976 14.627 45.912 15.205 ;
     RECT  53.568 14.579 53.592 15.205 ;
     RECT  34.8 13.331 36.456 15.301 ;
     RECT  65.808 13.765 67.704 15.301 ;
     RECT  2.4 7.237 3.24 15.349 ;
     RECT  4.608 14.773 5.304 15.349 ;
     RECT  9.36 14.771 10.104 15.349 ;
     RECT  65.808 15.301 67.752 15.349 ;
     RECT  71.136 14.677 71.208 15.397 ;
     RECT  53.568 15.205 53.64 15.443 ;
     RECT  15.504 14.867 15.528 15.445 ;
     RECT  23.52 13.957 25.224 15.445 ;
     RECT  29.28 14.867 29.712 15.493 ;
     RECT  44.448 15.205 45.912 15.493 ;
     RECT  47.568 14.725 52.488 15.539 ;
     RECT  40.2 13.907 41.16 15.541 ;
     RECT  22.8 15.445 25.224 15.587 ;
     RECT  28.08 14.867 28.104 15.829 ;
     RECT  29.28 15.493 30.216 15.875 ;
     RECT  61.8 14.677 62.664 15.923 ;
     RECT  75.504 14.867 76.68 15.923 ;
     RECT  70.224 15.397 71.208 15.971 ;
     RECT  9.36 15.349 10.296 16.019 ;
     RECT  47.568 15.539 52.152 16.019 ;
     RECT  59.568 14.099 59.784 16.067 ;
     RECT  15.408 15.445 15.528 16.211 ;
     RECT  61.8 15.923 62.376 16.259 ;
     RECT  29.28 15.875 29.832 16.309 ;
     RECT  43.584 15.493 45.912 16.309 ;
     RECT  47.568 16.019 51.312 16.309 ;
     RECT  30.816 16.309 30.84 16.405 ;
     RECT  59.568 16.067 59.592 16.405 ;
     RECT  17.136 15.349 17.16 16.451 ;
     RECT  30.816 16.405 31.032 16.451 ;
     RECT  70.224 15.971 71.16 16.451 ;
     RECT  29.088 16.309 29.832 16.547 ;
     RECT  34.176 15.301 36.456 16.549 ;
     RECT  7.104 14.771 8.112 16.595 ;
     RECT  23.136 15.587 25.224 16.595 ;
     RECT  27.792 15.829 28.104 16.595 ;
     RECT  29.28 16.547 29.832 16.595 ;
     RECT  43.584 16.309 51.312 16.595 ;
     RECT  33.888 16.549 36.456 16.693 ;
     RECT  37.632 16.549 37.656 16.693 ;
     RECT  33.888 16.693 37.656 16.837 ;
     RECT  38.976 14.339 39 16.837 ;
     RECT  78 13.331 78.312 16.837 ;
     RECT  12.096 14.725 13.656 16.883 ;
     RECT  44.928 16.595 51.312 16.931 ;
     RECT  15.936 16.405 15.96 16.933 ;
     RECT  31.008 16.451 31.032 16.933 ;
     RECT  23.136 16.595 24.84 16.979 ;
     RECT  61.8 16.259 62.112 16.981 ;
     RECT  2.4 15.349 5.304 17.029 ;
     RECT  9.36 16.019 9.624 17.029 ;
     RECT  20.544 14.387 20.904 17.029 ;
     RECT  40.2 15.541 41.352 17.029 ;
     RECT  43.584 16.595 43.608 17.029 ;
     RECT  59.04 16.405 59.592 17.029 ;
     RECT  60.816 16.981 62.112 17.029 ;
     RECT  43.488 17.029 43.608 17.075 ;
     RECT  65.808 15.349 67.848 17.075 ;
     RECT  40.08 17.029 41.352 17.077 ;
     RECT  2.4 17.029 5.688 17.123 ;
     RECT  33.888 16.837 39 17.123 ;
     RECT  59.04 17.029 62.112 17.123 ;
     RECT  37.632 17.123 39 17.219 ;
     RECT  40.08 17.077 41.4 17.219 ;
     RECT  44.928 16.931 46.632 17.555 ;
     RECT  65.808 17.075 67.752 17.603 ;
     RECT  29.28 16.595 29.712 17.605 ;
     RECT  31.008 16.933 31.8 17.605 ;
     RECT  59.04 17.123 60.12 17.605 ;
     RECT  71.136 16.451 71.16 17.605 ;
     RECT  72.6 7.043 72.912 17.605 ;
     RECT  43.488 17.075 43.512 17.651 ;
     RECT  15.936 16.933 16.872 17.699 ;
     RECT  23.52 16.979 24.84 17.699 ;
     RECT  28.08 16.595 28.104 17.699 ;
     RECT  40.08 17.219 41.352 17.701 ;
     RECT  10.944 17.653 10.968 17.795 ;
     RECT  53.568 15.443 53.592 17.845 ;
     RECT  53.568 17.845 54.024 17.891 ;
     RECT  65.808 17.603 65.832 17.891 ;
     RECT  55.248 15.109 56.712 17.893 ;
     RECT  9.36 17.029 9.72 17.941 ;
     RECT  76.464 15.923 76.68 17.989 ;
     RECT  3.984 17.123 5.688 18.035 ;
     RECT  54 17.891 54.024 18.035 ;
     RECT  20.544 17.029 21.288 18.131 ;
     RECT  55.248 17.893 57 18.179 ;
     RECT  58.368 17.605 60.12 18.179 ;
     RECT  78 16.837 78.408 18.179 ;
     RECT  45.6 17.555 46.632 18.181 ;
     RECT  47.616 16.931 51.312 18.181 ;
     RECT  71.136 17.605 72.912 18.181 ;
     RECT  23.52 17.699 24.648 18.227 ;
     RECT  23.52 18.227 24.456 18.275 ;
     RECT  58.368 18.179 59.592 18.419 ;
     RECT  13.056 16.883 13.656 18.517 ;
     RECT  12.96 18.517 13.656 18.565 ;
     RECT  20.784 18.131 21.288 18.565 ;
     RECT  23.904 18.275 24.456 18.611 ;
     RECT  23.904 18.611 24.408 18.659 ;
     RECT  40.032 17.701 41.352 18.707 ;
     RECT  43.584 18.469 43.608 18.707 ;
     RECT  20.784 18.565 21.528 18.709 ;
     RECT  29.28 17.605 31.8 18.755 ;
     RECT  38.976 17.219 39 18.755 ;
     RECT  75.552 17.989 76.68 18.757 ;
     RECT  78 18.179 78.312 18.757 ;
     RECT  9.36 17.941 9.96 18.803 ;
     RECT  12.96 18.565 14.232 18.803 ;
     RECT  70.992 18.181 72.912 18.853 ;
     RECT  40.08 18.707 41.352 18.899 ;
     RECT  13.056 18.803 14.232 18.947 ;
     RECT  4.608 18.035 5.688 18.995 ;
     RECT  70.224 18.853 72.912 19.043 ;
     RECT  70.992 19.043 72.912 19.139 ;
     RECT  20.784 18.709 21.624 19.333 ;
     RECT  5.088 18.995 5.688 19.379 ;
     RECT  75.552 18.757 78.312 19.427 ;
     RECT  55.248 18.179 56.712 19.477 ;
     RECT  29.28 18.755 29.976 19.573 ;
     RECT  18.6 12.755 19.032 19.621 ;
     RECT  20.736 19.333 21.624 19.667 ;
     RECT  58.608 18.419 59.592 19.763 ;
     RECT  29.232 19.573 29.976 19.909 ;
     RECT  18.48 19.621 19.032 19.955 ;
     RECT  58.608 19.763 59.544 20.003 ;
     RECT  75.552 19.427 75.576 20.053 ;
     RECT  13.2 18.947 14.232 20.099 ;
     RECT  22.848 19.237 22.872 20.099 ;
     RECT  45.6 18.181 51.312 20.099 ;
     RECT  74.88 20.053 75.576 20.099 ;
     RECT  76.656 19.427 78.312 20.099 ;
     RECT  16.848 17.699 16.872 20.147 ;
     RECT  20.784 19.667 21.624 20.243 ;
     RECT  71.136 19.139 72.912 20.243 ;
     RECT  18.6 19.955 19.032 20.339 ;
     RECT  33.888 17.123 36.456 20.387 ;
     RECT  48.24 20.099 51.312 20.531 ;
     RECT  31.008 18.755 31.8 20.579 ;
     RECT  29.232 19.909 30.024 20.675 ;
     RECT  31.056 20.579 31.8 20.675 ;
     RECT  72.288 20.243 72.912 20.677 ;
     RECT  7.8 16.595 8.112 20.725 ;
     RECT  9.36 18.803 9.384 20.725 ;
     RECT  66.816 17.603 67.752 20.725 ;
     RECT  31.056 20.675 31.08 20.867 ;
     RECT  55.152 19.477 56.712 20.867 ;
     RECT  33.888 20.387 35.88 20.915 ;
     RECT  40.2 18.899 41.352 20.963 ;
     RECT  45.6 20.099 47.256 20.965 ;
     RECT  69.84 20.197 69.864 20.965 ;
     RECT  72.288 20.677 73.224 20.965 ;
     RECT  5.28 19.379 5.688 21.059 ;
     RECT  44.784 20.965 47.256 21.061 ;
     RECT  24 18.659 24.408 21.109 ;
     RECT  44.64 21.061 47.256 21.155 ;
     RECT  68.832 19.237 68.856 21.155 ;
     RECT  22.896 21.013 22.92 21.395 ;
     RECT  33.888 20.915 35.832 21.395 ;
     RECT  13.2 20.099 13.608 21.493 ;
     RECT  13.104 21.493 13.608 21.539 ;
     RECT  52.368 20.485 52.392 21.635 ;
     RECT  71.136 20.243 71.16 21.637 ;
     RECT  72.288 20.965 73.752 21.637 ;
     RECT  71.136 21.637 73.752 21.683 ;
     RECT  24 21.109 24.456 21.827 ;
     RECT  47.232 21.155 47.256 21.923 ;
     RECT  55.248 20.867 56.712 21.925 ;
     RECT  29.4 20.675 30.024 21.973 ;
     RECT  48.24 20.531 48.264 21.973 ;
     RECT  66.528 20.725 67.752 22.019 ;
     RECT  29.232 21.973 30.024 22.115 ;
     RECT  29.28 22.115 30.024 22.117 ;
     RECT  76.656 20.099 76.68 22.163 ;
     RECT  2.4 17.123 2.712 22.165 ;
     RECT  34.8 21.395 35.832 22.165 ;
     RECT  44.64 21.155 45.912 22.165 ;
     RECT  54.96 21.925 56.712 22.165 ;
     RECT  58.608 20.003 58.632 22.165 ;
     RECT  29.28 22.117 30.936 22.211 ;
     RECT  4.128 21.445 4.152 22.213 ;
     RECT  3.984 22.213 4.152 22.259 ;
     RECT  54.96 22.165 56.808 22.259 ;
     RECT  69.84 20.965 70.056 22.645 ;
     RECT  40.2 20.963 40.512 22.693 ;
     RECT  7.8 20.725 9.384 22.835 ;
     RECT  58.608 22.165 58.872 22.835 ;
     RECT  56.4 22.259 56.808 22.931 ;
     RECT  29.28 22.211 29.712 23.027 ;
     RECT  47.424 21.973 48.264 23.029 ;
     RECT  49.776 20.531 51.312 23.029 ;
     RECT  54.96 22.259 54.984 23.125 ;
     RECT  67.2 22.019 67.752 23.173 ;
     RECT  68.784 23.125 68.808 23.173 ;
     RECT  47.424 23.029 51.312 23.267 ;
     RECT  34.8 22.165 36.168 23.317 ;
     RECT  56.4 22.931 56.712 23.317 ;
     RECT  48.24 23.267 51.312 23.363 ;
     RECT  54.864 23.125 54.984 23.363 ;
     RECT  58.608 22.835 58.728 23.363 ;
     RECT  38.256 22.741 38.28 23.365 ;
     RECT  39.36 22.693 40.512 23.365 ;
     RECT  2.4 22.165 2.904 23.411 ;
     RECT  38.256 23.365 40.512 23.411 ;
     RECT  39.888 23.411 40.512 23.413 ;
     RECT  43.92 22.165 45.912 23.555 ;
     RECT  53.568 22.741 53.592 23.555 ;
     RECT  39.888 23.413 40.632 23.651 ;
     RECT  34.224 23.317 36.168 23.843 ;
     RECT  26.304 23.365 26.328 24.083 ;
     RECT  14.832 21.205 14.856 24.131 ;
     RECT  39.888 23.651 40.512 24.131 ;
     RECT  54.864 23.363 54.888 24.131 ;
     RECT  18.6 20.339 18.912 24.229 ;
     RECT  38.256 23.411 38.76 24.275 ;
     RECT  67.2 23.173 68.808 24.275 ;
     RECT  5.28 21.059 5.4 24.277 ;
     RECT  5.136 24.277 5.4 24.323 ;
     RECT  30.72 22.211 30.936 24.323 ;
     RECT  48.24 23.363 48.504 24.323 ;
     RECT  69.84 22.645 70.536 24.325 ;
     RECT  9.36 22.835 9.384 24.469 ;
     RECT  10.416 23.893 10.44 24.469 ;
     RECT  56.16 23.317 56.712 24.613 ;
     RECT  9.36 24.469 10.44 24.659 ;
     RECT  22.8 22.501 22.824 24.659 ;
     RECT  38.736 24.275 38.76 24.659 ;
     RECT  61.8 17.123 62.112 24.853 ;
     RECT  13.104 21.539 13.512 25.045 ;
     RECT  61.632 24.853 62.112 25.045 ;
     RECT  49.776 23.363 51.312 25.093 ;
     RECT  52.368 24.325 52.392 25.093 ;
     RECT  30.72 24.323 30.744 25.139 ;
     RECT  18.6 24.229 19.416 25.141 ;
     RECT  34.224 23.843 35.112 25.141 ;
     RECT  61.44 25.045 62.112 25.141 ;
     RECT  18.6 25.141 19.944 25.187 ;
     RECT  2.4 23.411 2.712 25.237 ;
     RECT  3.984 22.259 4.008 25.237 ;
     RECT  13.104 25.045 13.656 25.283 ;
     RECT  60.576 25.141 62.112 25.283 ;
     RECT  74.88 20.099 74.904 25.285 ;
     RECT  69.504 24.325 70.536 25.333 ;
     RECT  71.568 21.683 73.752 25.333 ;
     RECT  33.936 25.141 35.112 25.379 ;
     RECT  40.2 24.131 40.512 25.429 ;
     RECT  66.048 22.021 66.072 25.475 ;
     RECT  64.896 20.485 64.92 25.525 ;
     RECT  24 21.827 24.408 25.715 ;
     RECT  34.224 25.379 35.112 25.715 ;
     RECT  56.16 24.613 56.808 25.715 ;
     RECT  74.88 25.285 75.192 25.715 ;
     RECT  58.608 23.363 58.632 25.717 ;
     RECT  2.4 25.237 4.008 25.763 ;
     RECT  64.56 25.525 64.92 25.861 ;
     RECT  22.848 25.045 22.872 26.003 ;
     RECT  29.4 23.027 29.712 26.005 ;
     RECT  44.64 23.555 45.912 26.101 ;
     RECT  61.056 25.283 62.112 26.293 ;
     RECT  75.168 25.715 75.192 26.531 ;
     RECT  44.256 26.101 45.912 26.533 ;
     RECT  5.136 24.323 5.304 26.677 ;
     RECT  58.608 25.717 58.92 26.723 ;
     RECT  48.24 24.323 48.264 26.725 ;
     RECT  49.776 25.093 52.392 26.725 ;
     RECT  78 20.099 78.312 26.725 ;
     RECT  64.176 25.861 64.92 26.771 ;
     RECT  13.2 25.283 13.656 26.819 ;
     RECT  19.92 25.187 19.944 26.819 ;
     RECT  42.336 25.573 42.36 26.819 ;
     RECT  48.24 26.725 52.392 26.819 ;
     RECT  54.528 25.669 54.552 27.059 ;
     RECT  63.12 26.821 63.144 27.059 ;
     RECT  66.144 26.773 66.168 27.061 ;
     RECT  67.2 24.275 68.424 27.061 ;
     RECT  66.144 27.061 68.424 27.203 ;
     RECT  44.256 26.533 46.536 27.301 ;
     RECT  48.24 26.819 49.8 27.301 ;
     RECT  5.04 26.677 5.304 27.347 ;
     RECT  44.256 27.301 49.8 27.347 ;
     RECT  44.64 27.347 49.8 27.395 ;
     RECT  64.176 26.771 64.584 27.395 ;
     RECT  34.272 25.715 35.112 27.589 ;
     RECT  36.144 23.843 36.168 27.589 ;
     RECT  38.256 27.445 38.28 27.635 ;
     RECT  34.272 27.589 36.168 27.733 ;
     RECT  29.04 26.005 29.712 27.779 ;
     RECT  42.624 27.589 42.648 27.779 ;
     RECT  66.144 27.203 66.168 27.827 ;
     RECT  76.752 26.725 78.312 27.827 ;
     RECT  60.912 26.293 62.112 27.829 ;
     RECT  44.928 27.395 49.8 27.875 ;
     RECT  76.752 27.827 76.92 27.877 ;
     RECT  13.2 26.819 13.512 27.925 ;
     RECT  58.608 26.723 58.632 27.925 ;
     RECT  33.312 27.733 36.168 27.971 ;
     RECT  58.368 27.925 58.632 27.971 ;
     RECT  40.032 25.429 40.512 28.213 ;
     RECT  42.768 28.117 42.792 28.259 ;
     RECT  50.88 26.819 52.392 28.355 ;
     RECT  60.528 27.829 62.112 28.357 ;
     RECT  39.744 28.213 40.512 28.499 ;
     RECT  13.2 27.925 13.608 28.547 ;
     RECT  50.88 28.355 51.312 28.549 ;
     RECT  54.384 27.829 54.408 28.595 ;
     RECT  44.928 27.875 46.728 28.739 ;
     RECT  33.312 27.971 33.336 28.787 ;
     RECT  28.176 27.781 28.2 28.789 ;
     RECT  29.184 27.779 29.712 28.789 ;
     RECT  50.784 28.549 51.312 28.883 ;
     RECT  58.368 27.971 58.392 28.981 ;
     RECT  64.56 27.395 64.584 28.981 ;
     RECT  21.6 20.243 21.624 29.029 ;
     RECT  37.056 28.357 37.08 29.077 ;
     RECT  37.056 29.077 37.176 29.123 ;
     RECT  45.6 28.739 46.728 29.123 ;
     RECT  37.152 29.123 37.176 29.219 ;
     RECT  59.904 28.357 62.112 29.267 ;
     RECT  52.368 28.355 52.392 29.365 ;
     RECT  7.8 22.835 8.112 29.509 ;
     RECT  40.08 28.499 40.512 29.557 ;
     RECT  67.2 27.203 68.424 29.557 ;
     RECT  76.512 27.877 76.92 29.605 ;
     RECT  78 27.827 78.312 29.605 ;
     RECT  11.856 29.509 11.88 29.651 ;
     RECT  57.696 28.981 58.392 29.651 ;
     RECT  48.24 27.875 49.8 29.699 ;
     RECT  56.16 25.715 56.712 29.699 ;
     RECT  43.872 28.309 43.896 29.747 ;
     RECT  34.8 27.971 35.208 29.795 ;
     RECT  20.64 29.029 21.624 29.939 ;
     RECT  75.264 28.981 75.288 29.941 ;
     RECT  74.976 29.941 75.288 29.989 ;
     RECT  76.512 29.605 78.312 29.989 ;
     RECT  74.976 29.989 78.312 30.035 ;
     RECT  45.6 29.123 46.008 30.133 ;
     RECT  5.28 27.347 5.304 30.181 ;
     RECT  34.8 29.795 35.112 30.181 ;
     RECT  52.368 29.365 53.112 30.227 ;
     RECT  18.6 25.187 18.912 30.229 ;
     RECT  50.88 28.883 51.312 30.229 ;
     RECT  60.384 29.267 62.112 30.275 ;
     RECT  67.2 29.557 68.52 30.277 ;
     RECT  28.176 28.789 29.712 30.323 ;
     RECT  31.248 28.549 31.272 30.323 ;
     RECT  48.24 29.699 48.984 30.563 ;
     RECT  64.56 28.981 65.208 30.565 ;
     RECT  39.888 29.557 40.512 30.611 ;
     RECT  3.984 25.763 4.008 30.613 ;
     RECT  5.136 30.181 5.304 30.613 ;
     RECT  61.056 30.275 62.112 30.613 ;
     RECT  7.8 29.509 8.28 30.661 ;
     RECT  64.08 30.565 65.208 30.709 ;
     RECT  5.136 30.613 5.688 30.755 ;
     RECT  6.72 30.661 8.28 30.803 ;
     RECT  33.84 30.181 35.112 30.803 ;
     RECT  5.136 30.755 5.304 30.851 ;
     RECT  57.84 29.651 58.392 30.851 ;
     RECT  6.816 30.803 8.28 30.899 ;
     RECT  50.832 30.229 51.312 30.947 ;
     RECT  32.448 30.373 32.472 30.997 ;
     RECT  24 25.715 24.312 31.045 ;
     RECT  69.504 25.333 73.752 31.093 ;
     RECT  74.976 30.035 76.92 31.093 ;
     RECT  69.504 31.093 76.92 31.189 ;
     RECT  77.904 30.035 78.312 31.189 ;
     RECT  69.504 31.189 78.312 31.283 ;
     RECT  7.8 30.899 8.28 31.285 ;
     RECT  9.36 24.659 9.624 31.285 ;
     RECT  43.872 31.237 43.896 31.285 ;
     RECT  15.696 27.349 15.72 31.379 ;
     RECT  45.6 30.133 46.728 31.379 ;
     RECT  48.24 30.563 48.6 31.379 ;
     RECT  69.504 31.283 75.288 31.379 ;
     RECT  43.632 31.285 43.896 31.381 ;
     RECT  45.6 31.379 45.912 31.381 ;
     RECT  56.4 29.699 56.712 31.429 ;
     RECT  52.368 30.227 52.392 31.475 ;
     RECT  50.88 30.947 51.312 31.523 ;
     RECT  48.576 31.379 48.6 31.571 ;
     RECT  63.936 30.709 65.208 31.619 ;
     RECT  56.4 31.429 56.808 31.667 ;
     RECT  76.512 31.283 78.312 31.717 ;
     RECT  11.472 31.045 11.496 31.765 ;
     RECT  42.24 30.709 42.264 31.811 ;
     RECT  76.512 31.717 78.504 31.859 ;
     RECT  21.6 29.939 21.624 31.861 ;
     RECT  11.28 31.765 11.496 31.955 ;
     RECT  17.904 30.229 18.912 31.955 ;
     RECT  66.24 30.277 68.52 31.955 ;
     RECT  2.4 25.763 2.712 31.957 ;
     RECT  3.936 30.613 4.008 31.957 ;
     RECT  29.184 30.323 29.712 32.003 ;
     RECT  18.6 31.955 18.912 32.005 ;
     RECT  32.448 30.997 33.096 32.099 ;
     RECT  66.336 31.955 68.52 32.195 ;
     RECT  64.08 31.619 65.208 32.245 ;
     RECT  11.28 31.955 11.304 32.293 ;
     RECT  69.504 31.379 75 32.341 ;
     RECT  76.512 31.859 76.92 32.341 ;
     RECT  61.056 30.613 62.952 32.435 ;
     RECT  16.8 30.133 16.824 32.437 ;
     RECT  26.4 31.093 26.424 32.437 ;
     RECT  64.08 32.245 65.352 32.483 ;
     RECT  51 31.523 51.312 32.965 ;
     RECT  61.056 32.435 62.112 32.965 ;
     RECT  5.28 30.851 5.304 33.013 ;
     RECT  16.8 32.437 17.208 33.059 ;
     RECT  2.4 31.957 4.008 33.061 ;
     RECT  5.28 33.013 5.832 33.061 ;
     RECT  49.008 33.061 49.128 33.203 ;
     RECT  49.008 33.203 49.032 33.251 ;
     RECT  33.072 32.099 33.096 33.347 ;
     RECT  7.8 31.285 9.624 33.397 ;
     RECT  10.848 32.293 11.304 33.397 ;
     RECT  47.136 33.397 47.16 33.539 ;
     RECT  30.912 31.285 30.936 33.731 ;
     RECT  21.504 31.861 21.624 33.827 ;
     RECT  43.632 31.381 45.912 33.973 ;
     RECT  60.96 32.965 62.112 34.069 ;
     RECT  2.4 33.061 5.832 34.115 ;
     RECT  16.8 33.059 16.824 34.117 ;
     RECT  25.824 32.437 26.424 34.211 ;
     RECT  7.8 33.397 11.304 34.259 ;
     RECT  16.752 34.117 16.824 34.259 ;
     RECT  4.992 34.115 5.832 34.355 ;
     RECT  60.96 34.069 62.664 34.403 ;
     RECT  43.632 33.973 46.104 34.451 ;
     RECT  10.848 34.259 11.304 34.501 ;
     RECT  53.664 33.349 53.688 34.643 ;
     RECT  58.368 30.851 58.392 34.741 ;
     RECT  58.368 34.741 59.112 34.931 ;
     RECT  47.904 34.117 47.928 34.979 ;
     RECT  43.632 34.451 45.912 35.029 ;
     RECT  40.2 30.611 40.512 35.269 ;
     RECT  4.992 34.355 5.304 35.363 ;
     RECT  58.368 34.931 58.728 35.363 ;
     RECT  77.904 31.859 78.504 35.459 ;
     RECT  5.088 35.363 5.304 35.603 ;
     RECT  7.8 34.259 9.624 35.701 ;
     RECT  78 35.459 78.504 35.747 ;
     RECT  16.752 34.259 16.776 35.749 ;
     RECT  16.608 35.749 16.776 35.845 ;
     RECT  34.8 30.803 35.112 35.845 ;
     RECT  54.144 35.173 54.216 35.845 ;
     RECT  39.792 35.269 40.512 35.891 ;
     RECT  39.888 35.891 40.512 35.987 ;
     RECT  64.224 32.483 65.352 35.989 ;
     RECT  67.2 32.195 68.52 36.083 ;
     RECT  50.688 32.965 51.312 36.085 ;
     RECT  48.96 33.589 48.984 36.131 ;
     RECT  54.144 35.845 55.272 36.131 ;
     RECT  56.4 31.667 56.712 36.133 ;
     RECT  55.248 36.131 55.272 36.179 ;
     RECT  60.96 34.403 62.112 36.181 ;
     RECT  63.216 35.989 63.24 36.181 ;
     RECT  60.96 36.181 63.24 36.323 ;
     RECT  16.608 35.845 17.544 36.371 ;
     RECT  23.28 31.045 24.312 36.373 ;
     RECT  34.8 35.845 36.072 36.421 ;
     RECT  58.368 35.363 58.392 36.421 ;
     RECT  6.816 35.701 9.624 36.515 ;
     RECT  17.52 36.371 17.544 36.515 ;
     RECT  18.6 32.005 19.896 36.515 ;
     RECT  54.144 36.131 54.264 36.515 ;
     RECT  22.752 36.373 24.312 36.611 ;
     RECT  63.216 36.323 63.24 36.611 ;
     RECT  13.2 28.547 13.512 36.613 ;
     RECT  60.96 36.323 62.112 36.659 ;
     RECT  78 35.747 78.408 36.659 ;
     RECT  28.176 30.323 28.2 36.901 ;
     RECT  29.4 32.003 29.712 36.901 ;
     RECT  15.408 33.589 15.432 36.947 ;
     RECT  69.504 32.341 76.92 36.949 ;
     RECT  78 36.659 78.312 36.949 ;
     RECT  10.848 34.501 11.448 36.997 ;
     RECT  34.8 36.421 36.984 37.043 ;
     RECT  64.224 35.989 65.544 37.141 ;
     RECT  64.224 37.141 65.736 37.187 ;
     RECT  10.752 36.997 11.448 37.235 ;
     RECT  26.4 34.211 26.424 37.285 ;
     RECT  22.752 36.611 22.776 37.331 ;
     RECT  50.688 36.085 51.96 37.379 ;
     RECT  28.176 36.901 29.712 37.381 ;
     RECT  31.152 36.901 31.176 37.381 ;
     RECT  23.904 36.611 24.312 37.427 ;
     RECT  42.912 35.029 45.912 37.477 ;
     RECT  56.4 36.133 57.192 37.571 ;
     RECT  61.056 36.659 62.112 37.571 ;
     RECT  13.2 36.613 14.424 37.573 ;
     RECT  28.176 37.381 31.176 37.573 ;
     RECT  40.2 35.987 40.512 37.573 ;
     RECT  28.176 37.573 31.464 37.619 ;
     RECT  56.4 37.571 56.808 37.859 ;
     RECT  58.368 36.421 59.256 37.859 ;
     RECT  26.208 37.285 26.424 37.861 ;
     RECT  26.208 37.861 26.76 37.907 ;
     RECT  29.4 37.619 31.464 37.907 ;
     RECT  36.96 37.043 36.984 37.907 ;
     RECT  64.272 37.187 65.736 37.909 ;
     RECT  54.192 36.515 54.264 37.957 ;
     RECT  12.576 37.573 14.424 38.101 ;
     RECT  54.192 37.957 54.744 38.101 ;
     RECT  40.2 37.573 41.016 38.149 ;
     RECT  67.2 36.083 68.424 38.149 ;
     RECT  69.504 36.949 78.312 38.149 ;
     RECT  28.176 37.619 28.392 38.195 ;
     RECT  31.392 37.907 31.464 38.195 ;
     RECT  54.192 38.101 55.128 38.195 ;
     RECT  26.736 37.907 26.76 38.197 ;
     RECT  10.752 37.235 11.112 38.243 ;
     RECT  29.4 37.907 29.832 38.387 ;
     RECT  7.8 36.515 9.624 38.483 ;
     RECT  42.768 37.477 45.912 38.579 ;
     RECT  18.6 36.515 18.912 38.677 ;
     RECT  67.2 38.149 78.312 38.677 ;
     RECT  12.576 38.101 14.712 38.725 ;
     RECT  28.368 38.195 28.392 38.725 ;
     RECT  29.4 38.387 29.712 38.725 ;
     RECT  38.784 37.477 38.808 38.771 ;
     RECT  64.272 37.909 66.168 38.821 ;
     RECT  26.736 38.197 27.144 38.867 ;
     RECT  67.2 38.677 78.552 38.917 ;
     RECT  40.08 38.149 41.016 38.963 ;
     RECT  51 37.379 51.96 39.157 ;
     RECT  58.368 37.859 58.392 39.253 ;
     RECT  67.2 38.917 78.984 39.301 ;
     RECT  67.2 39.301 79.032 39.349 ;
     RECT  58.032 39.253 58.392 39.395 ;
     RECT  63.408 38.821 66.168 39.395 ;
     RECT  12.576 38.725 15.288 39.443 ;
     RECT  40.08 38.963 40.632 39.491 ;
     RECT  54.24 38.195 55.128 39.539 ;
     RECT  9.36 38.483 9.624 39.541 ;
     RECT  10.848 38.243 11.112 39.541 ;
     RECT  43.632 38.579 45.912 39.637 ;
     RECT  51 39.157 52.728 39.829 ;
     RECT  43.104 39.637 46.344 39.875 ;
     RECT  54.72 39.539 55.128 39.875 ;
     RECT  12.576 39.443 14.424 39.923 ;
     RECT  21.6 33.827 21.624 39.923 ;
     RECT  54.72 39.875 54.744 39.923 ;
     RECT  61.584 37.571 62.112 39.973 ;
     RECT  37.776 38.437 37.8 40.067 ;
     RECT  40.2 39.491 40.632 40.163 ;
     RECT  43.104 39.875 43.944 40.163 ;
     RECT  9.36 39.541 11.112 40.307 ;
     RECT  16.56 38.101 16.584 40.307 ;
     RECT  31.392 38.195 31.416 40.307 ;
     RECT  10.944 40.307 11.112 40.309 ;
     RECT  12.768 39.923 14.424 40.355 ;
     RECT  64.272 39.395 66.168 40.355 ;
     RECT  56.4 37.859 56.712 40.357 ;
     RECT  61.584 39.973 62.664 40.357 ;
     RECT  58.032 39.395 58.056 40.403 ;
     RECT  24 37.427 24.312 40.405 ;
     RECT  43.104 40.163 43.128 40.451 ;
     RECT  45.6 39.875 46.344 40.451 ;
     RECT  26.736 38.867 26.76 40.499 ;
     RECT  36.48 39.205 36.504 40.547 ;
     RECT  12.768 40.355 14.04 40.595 ;
     RECT  17.856 38.677 18.912 40.835 ;
     RECT  51 39.829 52.872 41.027 ;
     RECT  9.36 40.307 9.672 41.075 ;
     RECT  24 40.405 25.08 41.075 ;
     RECT  28.368 38.725 29.712 41.075 ;
     RECT  60.912 40.357 62.664 41.075 ;
     RECT  9.6 41.075 9.672 41.123 ;
     RECT  54.624 40.741 54.648 41.171 ;
     RECT  40.2 40.163 40.512 41.221 ;
     RECT  10.944 40.309 11.544 41.411 ;
     RECT  10.944 41.411 11.112 41.413 ;
     RECT  7.8 38.483 8.112 41.461 ;
     RECT  61.584 41.075 62.664 41.651 ;
     RECT  59.904 40.405 59.928 41.653 ;
     RECT  51 41.027 52.728 41.747 ;
     RECT  67.2 39.349 79.8 41.989 ;
     RECT  24 41.075 25.032 42.133 ;
     RECT  61.584 41.651 62.112 42.133 ;
     RECT  64.272 40.355 65.736 42.181 ;
     RECT  66.72 41.989 79.8 42.181 ;
     RECT  39.888 41.221 40.512 42.227 ;
     RECT  55.872 40.357 56.712 42.275 ;
     RECT  23.232 42.133 25.032 42.277 ;
     RECT  23.232 42.277 25.128 42.419 ;
     RECT  17.232 41.221 17.256 42.563 ;
     RECT  38.592 42.325 38.616 42.563 ;
     RECT  59.184 41.653 59.928 42.611 ;
     RECT  7.056 41.461 8.52 42.709 ;
     RECT  28.752 41.075 29.712 42.709 ;
     RECT  34.8 37.043 35.112 42.709 ;
     RECT  36.144 42.133 36.168 42.709 ;
     RECT  51 41.747 51.312 42.709 ;
     RECT  2.4 34.115 4.008 42.757 ;
     RECT  23.232 42.419 24.408 43.093 ;
     RECT  32.496 41.365 32.52 43.141 ;
     RECT  32.496 43.141 32.76 43.187 ;
     RECT  61.344 42.133 62.112 43.187 ;
     RECT  5.28 35.603 5.304 43.237 ;
     RECT  6.48 42.709 8.52 43.237 ;
     RECT  40.2 42.227 40.512 43.285 ;
     RECT  55.392 43.141 55.416 43.285 ;
     RECT  59.904 42.611 59.928 43.285 ;
     RECT  34.8 42.709 36.168 43.331 ;
     RECT  56.4 42.275 56.712 43.333 ;
     RECT  63.264 42.085 63.288 43.333 ;
     RECT  64.272 42.181 79.8 43.333 ;
     RECT  22.464 43.093 24.408 43.379 ;
     RECT  26.928 42.181 26.952 43.379 ;
     RECT  63.264 43.333 79.8 43.379 ;
     RECT  59.904 43.285 60.168 43.573 ;
     RECT  56.4 43.333 56.808 43.621 ;
     RECT  59.616 43.573 60.168 43.621 ;
     RECT  43.92 41.365 43.944 43.765 ;
     RECT  2.4 42.757 4.104 43.813 ;
     RECT  50.88 42.709 51.312 43.859 ;
     RECT  43.92 43.765 44.088 43.861 ;
     RECT  30.816 42.709 30.84 43.955 ;
     RECT  40.2 43.285 41.064 43.955 ;
     RECT  5.28 43.237 8.52 44.051 ;
     RECT  2.4 43.813 4.2 44.053 ;
     RECT  5.28 44.051 5.496 44.053 ;
     RECT  32.736 43.187 32.76 44.099 ;
     RECT  6.48 44.051 8.52 44.149 ;
     RECT  9.6 41.123 9.624 44.149 ;
     RECT  55.248 43.285 55.416 44.149 ;
     RECT  56.4 43.621 57.336 44.149 ;
     RECT  6.48 44.149 9.624 44.339 ;
     RECT  21.072 42.709 21.096 44.339 ;
     RECT  2.4 44.053 5.496 44.341 ;
     RECT  55.248 44.149 57.336 44.341 ;
     RECT  36.144 43.331 36.168 44.437 ;
     RECT  45.6 40.451 45.912 44.437 ;
     RECT  28.704 42.709 29.712 44.483 ;
     RECT  47.328 42.709 47.352 44.483 ;
     RECT  52.704 41.747 52.728 44.483 ;
     RECT  61.536 43.187 62.112 44.483 ;
     RECT  63.84 43.379 79.8 44.483 ;
     RECT  43.392 43.861 44.088 44.629 ;
     RECT  42.528 44.629 44.088 44.675 ;
     RECT  18.6 40.835 18.912 44.677 ;
     RECT  55.152 44.341 57.336 44.725 ;
     RECT  24 43.379 24.408 44.771 ;
     RECT  24 44.771 24.312 44.821 ;
     RECT  42.528 44.675 42.552 44.965 ;
     RECT  36.144 44.437 36.888 45.011 ;
     RECT  45.504 44.437 45.912 45.203 ;
     RECT  12.768 40.595 13.512 45.205 ;
     RECT  59.472 43.621 60.168 45.301 ;
     RECT  45.6 45.203 45.912 45.397 ;
     RECT  2.208 44.341 5.496 45.445 ;
     RECT  6.528 44.339 9.624 45.445 ;
     RECT  33.168 45.445 33.192 45.541 ;
     RECT  36.144 45.011 36.36 45.635 ;
     RECT  42.144 44.965 42.552 45.635 ;
     RECT  58.896 45.301 60.168 45.635 ;
     RECT  42.288 45.635 42.552 45.683 ;
     RECT  31.344 44.965 31.368 45.685 ;
     RECT  38.976 45.061 39 45.779 ;
     RECT  22.464 43.379 22.488 45.781 ;
     RECT  23.568 44.821 24.312 45.781 ;
     RECT  61.584 44.483 62.112 45.781 ;
     RECT  61.584 45.781 62.712 45.973 ;
     RECT  12.144 45.205 13.512 46.021 ;
     RECT  51 43.859 51.312 46.069 ;
     RECT  28.752 44.483 29.712 46.211 ;
     RECT  30.816 45.685 31.368 46.211 ;
     RECT  54 45.541 54.024 46.211 ;
     RECT  58.896 45.635 58.92 46.211 ;
     RECT  64.08 44.483 79.8 46.211 ;
     RECT  10.8 41.413 11.112 46.213 ;
     RECT  12.144 46.021 13.608 46.213 ;
     RECT  33.024 45.541 33.192 46.213 ;
     RECT  34.8 43.331 35.112 46.213 ;
     RECT  45.6 45.397 46.68 46.213 ;
     RECT  49.248 44.437 49.272 46.213 ;
     RECT  33.024 46.213 35.112 46.259 ;
     RECT  49.008 46.213 49.272 46.309 ;
     RECT  10.8 46.213 13.608 46.355 ;
     RECT  64.08 46.211 79.752 46.357 ;
     RECT  45.6 46.213 47.112 46.499 ;
     RECT  33.072 46.259 35.112 46.549 ;
     RECT  47.088 46.499 47.112 46.595 ;
     RECT  33.072 46.549 35.208 46.643 ;
     RECT  22.464 45.781 24.312 46.645 ;
     RECT  33.84 46.643 35.208 46.691 ;
     RECT  61.488 45.973 62.712 46.693 ;
     RECT  63.936 46.357 79.752 46.693 ;
     RECT  12.144 46.355 13.608 46.787 ;
     RECT  33.84 46.691 35.112 46.787 ;
     RECT  42.288 45.683 42.312 46.787 ;
     RECT  17.616 44.677 18.912 46.835 ;
     RECT  50.544 46.069 51.312 46.885 ;
     RECT  2.208 45.445 9.624 46.933 ;
     RECT  10.8 46.355 11.112 46.933 ;
     RECT  50.544 46.885 51.672 47.027 ;
     RECT  17.856 46.835 18.912 47.029 ;
     RECT  22.464 46.645 24.456 47.075 ;
     RECT  22.464 47.075 22.872 47.125 ;
     RECT  17.856 47.029 19.032 47.221 ;
     RECT  20.064 46.933 20.088 47.221 ;
     RECT  17.856 47.221 20.088 47.269 ;
     RECT  2.208 46.933 11.112 47.363 ;
     RECT  17.856 47.269 20.616 47.413 ;
     RECT  22.224 47.125 22.872 47.413 ;
     RECT  29.4 46.211 29.712 47.605 ;
     RECT  17.856 47.413 22.872 47.747 ;
     RECT  40.2 43.955 40.512 47.749 ;
     RECT  48.432 46.309 49.272 47.749 ;
     RECT  55.152 44.725 57.432 47.797 ;
     RECT  30.816 46.211 30.84 47.845 ;
     RECT  42.768 47.365 42.792 47.891 ;
     RECT  44.064 44.675 44.088 47.893 ;
     RECT  30.816 47.845 31.464 47.939 ;
     RECT  44.064 47.893 44.184 47.939 ;
     RECT  2.208 47.363 10.824 47.987 ;
     RECT  39.648 47.749 40.512 47.989 ;
     RECT  61.488 46.693 79.752 48.037 ;
     RECT  15.696 47.221 15.72 48.083 ;
     RECT  61.488 48.037 80.232 48.179 ;
     RECT  36.336 45.635 36.36 48.181 ;
     RECT  52.896 47.413 52.92 48.227 ;
     RECT  2.208 47.987 10.776 48.275 ;
     RECT  59.904 47.413 59.928 48.277 ;
     RECT  61.488 48.179 79.752 48.277 ;
     RECT  36.336 48.181 37.08 48.323 ;
     RECT  25.536 44.341 25.56 48.421 ;
     RECT  25.488 48.421 25.56 48.469 ;
     RECT  13.104 46.787 13.608 48.515 ;
     RECT  18.6 47.747 22.872 48.611 ;
     RECT  47.904 47.749 49.272 48.659 ;
     RECT  51 47.027 51.672 48.707 ;
     RECT  44.16 47.939 44.184 48.901 ;
     RECT  45.6 46.499 45.912 48.901 ;
     RECT  59.904 48.277 79.752 48.901 ;
     RECT  31.44 47.939 31.464 48.947 ;
     RECT  39.648 47.989 40.824 48.995 ;
     RECT  40.2 48.995 40.824 48.997 ;
     RECT  36.336 48.323 37.032 49.043 ;
     RECT  44.16 48.901 45.912 49.043 ;
     RECT  2.208 48.275 10.536 49.091 ;
     RECT  59.52 48.901 79.752 49.091 ;
     RECT  22.128 48.611 22.872 49.189 ;
     RECT  18.6 48.611 20.616 49.285 ;
     RECT  2.208 49.091 10.248 49.475 ;
     RECT  49.248 48.659 49.272 49.477 ;
     RECT  49.248 49.477 49.656 49.619 ;
     RECT  22.128 49.189 22.968 49.717 ;
     RECT  25.488 48.469 25.752 49.763 ;
     RECT  40.2 48.997 41.544 49.763 ;
     RECT  47.904 48.659 47.928 49.765 ;
     RECT  47.28 49.765 47.928 49.811 ;
     RECT  11.904 49.525 11.928 49.861 ;
     RECT  59.52 49.091 59.544 49.907 ;
     RECT  54.96 47.797 57.432 50.051 ;
     RECT  60.672 49.091 79.704 50.051 ;
     RECT  5.28 49.475 10.248 50.053 ;
     RECT  5.28 50.053 10.488 50.195 ;
     RECT  11.904 49.861 12.12 50.291 ;
     RECT  54.96 50.051 55.416 50.341 ;
     RECT  12.096 50.291 12.12 50.387 ;
     RECT  18.48 49.285 20.616 50.389 ;
     RECT  29.088 47.605 29.712 50.579 ;
     RECT  5.472 50.195 10.488 50.581 ;
     RECT  44.16 49.043 44.184 50.629 ;
     RECT  45.6 49.043 45.912 50.629 ;
     RECT  56.4 50.051 57.432 50.675 ;
     RECT  18.432 50.389 20.616 50.677 ;
     RECT  21.696 49.717 22.968 50.677 ;
     RECT  49.632 49.619 49.656 50.725 ;
     RECT  54.672 50.341 55.416 50.771 ;
     RECT  54.672 50.771 55.272 50.819 ;
     RECT  60.768 50.051 79.704 50.819 ;
     RECT  40.2 49.763 40.824 50.867 ;
     RECT  49.248 50.725 49.656 50.915 ;
     RECT  49.632 50.915 49.656 50.917 ;
     RECT  51 48.707 51.312 50.917 ;
     RECT  49.632 50.917 51.312 50.963 ;
     RECT  2.208 49.475 4.296 50.965 ;
     RECT  40.2 50.867 40.632 51.011 ;
     RECT  42.576 50.053 42.6 51.107 ;
     RECT  36.336 49.043 36.36 51.157 ;
     RECT  36.336 51.157 36.456 51.203 ;
     RECT  54.672 50.819 54.984 51.205 ;
     RECT  13.104 48.515 13.512 51.253 ;
     RECT  18.432 50.677 22.968 51.253 ;
     RECT  5.472 50.581 10.776 51.301 ;
     RECT  33.792 49.765 33.816 51.491 ;
     RECT  2.208 50.965 4.44 51.493 ;
     RECT  44.16 50.629 45.912 51.875 ;
     RECT  36.432 51.203 36.456 51.923 ;
     RECT  44.16 51.875 44.184 51.923 ;
     RECT  61.44 50.819 79.704 51.923 ;
     RECT  25.488 49.763 25.512 51.971 ;
     RECT  47.28 49.811 47.304 51.971 ;
     RECT  54.192 51.205 54.984 51.971 ;
     RECT  13.104 51.253 13.608 52.163 ;
     RECT  56.4 50.675 56.712 52.213 ;
     RECT  54.192 51.971 54.216 52.259 ;
     RECT  26.88 51.253 26.904 52.307 ;
     RECT  1.68 51.493 4.44 52.309 ;
     RECT  5.472 51.301 11.112 52.309 ;
     RECT  76.752 51.923 79.704 52.453 ;
     RECT  18.288 51.253 22.968 52.499 ;
     RECT  30.768 51.781 30.792 52.499 ;
     RECT  61.44 51.923 75.72 52.499 ;
     RECT  76.752 52.453 80.328 52.499 ;
     RECT  18.288 52.499 21.096 52.595 ;
     RECT  34.8 46.787 35.112 52.645 ;
     RECT  34.8 52.645 36.024 52.931 ;
     RECT  56.4 52.213 57.624 53.075 ;
     RECT  50.112 50.963 51.312 53.267 ;
     RECT  76.848 52.499 80.328 53.317 ;
     RECT  56.4 53.075 56.856 53.363 ;
     RECT  1.68 52.309 11.112 53.557 ;
     RECT  18.288 52.595 21.048 53.557 ;
     RECT  61.44 52.499 74.664 53.557 ;
     RECT  75.696 52.499 75.72 53.557 ;
     RECT  76.848 53.317 80.904 53.557 ;
     RECT  13.2 52.163 13.608 53.603 ;
     RECT  22.752 52.499 22.968 53.603 ;
     RECT  42.72 52.981 42.744 53.603 ;
     RECT  1.584 53.557 11.208 53.605 ;
     RECT  17.808 53.557 21.048 53.651 ;
     RECT  32.064 49.525 32.088 53.795 ;
     RECT  1.584 53.605 11.304 53.797 ;
     RECT  1.584 53.797 11.4 53.941 ;
     RECT  17.808 53.651 20.712 53.941 ;
     RECT  60.432 53.557 80.904 53.941 ;
     RECT  13.2 53.603 13.512 54.009 ;
     RECT  24 47.075 24.312 54.009 ;
     RECT  29.4 50.579 29.712 54.009 ;
     RECT  34.8 52.931 35.112 54.009 ;
     RECT  40.2 51.011 40.512 54.009 ;
     RECT  45.6 51.875 45.912 54.009 ;
     RECT  51 53.267 51.312 54.009 ;
     RECT  56.4 53.363 56.712 54.009 ;
     RECT  13.2 54.009 13.32 54.023 ;
     RECT  24 54.009 24.12 54.023 ;
     RECT  29.4 54.009 29.52 54.023 ;
     RECT  34.8 54.009 34.92 54.023 ;
     RECT  40.2 54.009 40.32 54.023 ;
     RECT  45.6 54.009 45.72 54.023 ;
     RECT  51 54.009 51.12 54.023 ;
     RECT  56.4 54.009 56.52 54.023 ;
     RECT  59.856 53.941 80.904 54.133 ;
     RECT  17.616 53.941 20.712 56.051 ;
     RECT  1.488 53.941 11.4 56.144 ;
     RECT  17.616 56.051 20.616 56.144 ;
     RECT  59.856 54.133 81.288 56.144 ;
  END
END ot_hgi_coll_fj_n2s1
END LIBRARY
